VERSION 5.8 ;
BUSBITCHARS "[]" ;
DIVIDERCHAR "/" ;
UNITS
    DATABASE MICRONS 1000 ;
END UNITS

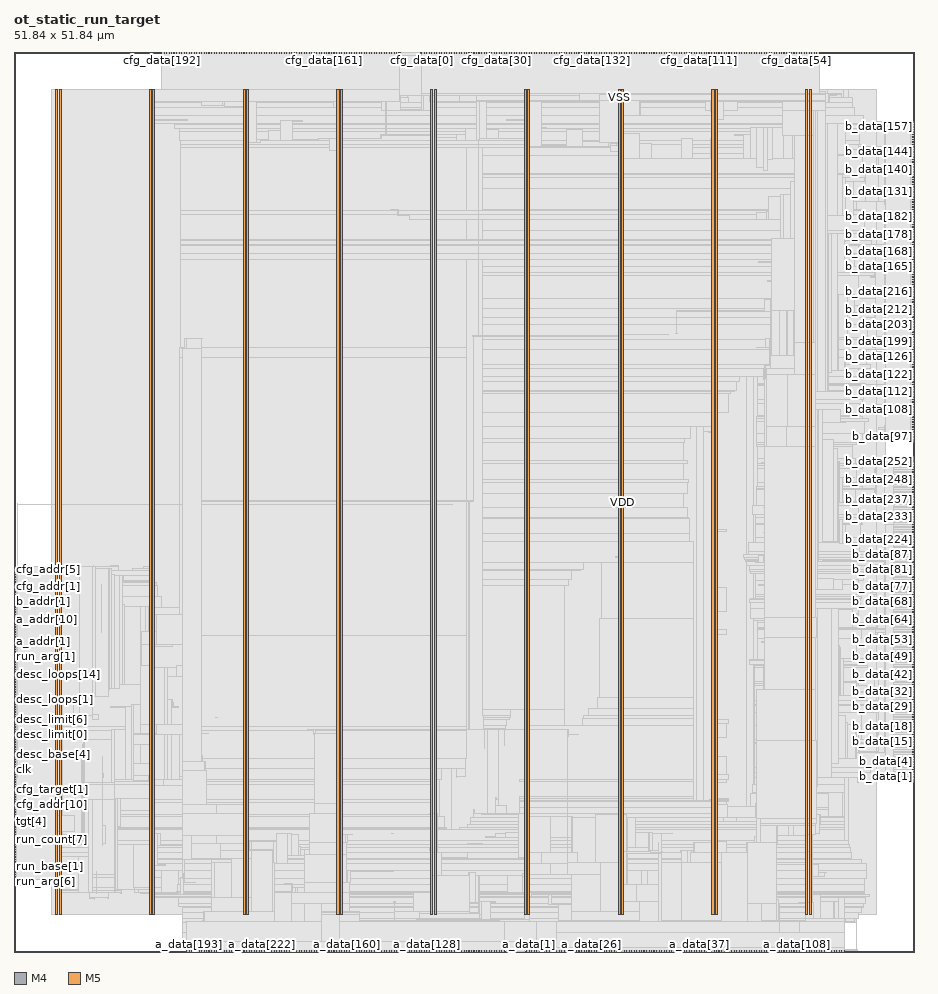
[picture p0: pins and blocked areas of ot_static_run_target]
MACRO ot_static_run_target
  FOREIGN ot_static_run_target 0 0 ;
  CLASS BLOCK ;
  SIZE 51.84 BY 51.84 ;
  PIN a_addr[0]
    DIRECTION OUTPUT ;
    USE SIGNAL ;
    PORT
      LAYER M4 ;
        RECT  0 17.712 0.084 17.736 ;
    END
  END a_addr[0]
  PIN a_addr[10]
    DIRECTION OUTPUT ;
    USE SIGNAL ;
    PORT
      LAYER M4 ;
        RECT  0 19.152 0.084 19.176 ;
    END
  END a_addr[10]
  PIN a_addr[1]
    DIRECTION OUTPUT ;
    USE SIGNAL ;
    PORT
      LAYER M4 ;
        RECT  0 17.856 0.084 17.88 ;
    END
  END a_addr[1]
  PIN a_addr[2]
    DIRECTION OUTPUT ;
    USE SIGNAL ;
    PORT
      LAYER M4 ;
        RECT  0 18 0.084 18.024 ;
    END
  END a_addr[2]
  PIN a_addr[3]
    DIRECTION OUTPUT ;
    USE SIGNAL ;
    PORT
      LAYER M4 ;
        RECT  0 18.144 0.084 18.168 ;
    END
  END a_addr[3]
  PIN a_addr[4]
    DIRECTION OUTPUT ;
    USE SIGNAL ;
    PORT
      LAYER M4 ;
        RECT  0 18.288 0.084 18.312 ;
    END
  END a_addr[4]
  PIN a_addr[5]
    DIRECTION OUTPUT ;
    USE SIGNAL ;
    PORT
      LAYER M4 ;
        RECT  0 18.432 0.084 18.456 ;
    END
  END a_addr[5]
  PIN a_addr[6]
    DIRECTION OUTPUT ;
    USE SIGNAL ;
    PORT
      LAYER M4 ;
        RECT  0 18.576 0.084 18.6 ;
    END
  END a_addr[6]
  PIN a_addr[7]
    DIRECTION OUTPUT ;
    USE SIGNAL ;
    PORT
      LAYER M4 ;
        RECT  0 18.72 0.084 18.744 ;
    END
  END a_addr[7]
  PIN a_addr[8]
    DIRECTION OUTPUT ;
    USE SIGNAL ;
    PORT
      LAYER M4 ;
        RECT  0 18.864 0.084 18.888 ;
    END
  END a_addr[8]
  PIN a_addr[9]
    DIRECTION OUTPUT ;
    USE SIGNAL ;
    PORT
      LAYER M4 ;
        RECT  0 19.008 0.084 19.032 ;
    END
  END a_addr[9]
  PIN a_data[0]
    DIRECTION OUTPUT ;
    USE SIGNAL ;
    PORT
      LAYER M5 ;
        RECT  29.52 0 29.544 0.084 ;
    END
  END a_data[0]
  PIN a_data[100]
    DIRECTION OUTPUT ;
    USE SIGNAL ;
    PORT
      LAYER M5 ;
        RECT  43.92 0 43.944 0.084 ;
    END
  END a_data[100]
  PIN a_data[101]
    DIRECTION OUTPUT ;
    USE SIGNAL ;
    PORT
      LAYER M5 ;
        RECT  44.064 0 44.088 0.084 ;
    END
  END a_data[101]
  PIN a_data[102]
    DIRECTION OUTPUT ;
    USE SIGNAL ;
    PORT
      LAYER M5 ;
        RECT  44.208 0 44.232 0.084 ;
    END
  END a_data[102]
  PIN a_data[103]
    DIRECTION OUTPUT ;
    USE SIGNAL ;
    PORT
      LAYER M5 ;
        RECT  44.352 0 44.376 0.084 ;
    END
  END a_data[103]
  PIN a_data[104]
    DIRECTION OUTPUT ;
    USE SIGNAL ;
    PORT
      LAYER M5 ;
        RECT  44.496 0 44.52 0.084 ;
    END
  END a_data[104]
  PIN a_data[105]
    DIRECTION OUTPUT ;
    USE SIGNAL ;
    PORT
      LAYER M5 ;
        RECT  44.64 0 44.664 0.084 ;
    END
  END a_data[105]
  PIN a_data[106]
    DIRECTION OUTPUT ;
    USE SIGNAL ;
    PORT
      LAYER M5 ;
        RECT  44.784 0 44.808 0.084 ;
    END
  END a_data[106]
  PIN a_data[107]
    DIRECTION OUTPUT ;
    USE SIGNAL ;
    PORT
      LAYER M5 ;
        RECT  44.928 0 44.952 0.084 ;
    END
  END a_data[107]
  PIN a_data[108]
    DIRECTION OUTPUT ;
    USE SIGNAL ;
    PORT
      LAYER M5 ;
        RECT  45.072 0 45.096 0.084 ;
    END
  END a_data[108]
  PIN a_data[109]
    DIRECTION OUTPUT ;
    USE SIGNAL ;
    PORT
      LAYER M5 ;
        RECT  45.216 0 45.24 0.084 ;
    END
  END a_data[109]
  PIN a_data[10]
    DIRECTION OUTPUT ;
    USE SIGNAL ;
    PORT
      LAYER M5 ;
        RECT  30.96 0 30.984 0.084 ;
    END
  END a_data[10]
  PIN a_data[110]
    DIRECTION OUTPUT ;
    USE SIGNAL ;
    PORT
      LAYER M5 ;
        RECT  45.36 0 45.384 0.084 ;
    END
  END a_data[110]
  PIN a_data[111]
    DIRECTION OUTPUT ;
    USE SIGNAL ;
    PORT
      LAYER M5 ;
        RECT  45.504 0 45.528 0.084 ;
    END
  END a_data[111]
  PIN a_data[112]
    DIRECTION OUTPUT ;
    USE SIGNAL ;
    PORT
      LAYER M5 ;
        RECT  45.648 0 45.672 0.084 ;
    END
  END a_data[112]
  PIN a_data[113]
    DIRECTION OUTPUT ;
    USE SIGNAL ;
    PORT
      LAYER M5 ;
        RECT  45.792 0 45.816 0.084 ;
    END
  END a_data[113]
  PIN a_data[114]
    DIRECTION OUTPUT ;
    USE SIGNAL ;
    PORT
      LAYER M5 ;
        RECT  45.936 0 45.96 0.084 ;
    END
  END a_data[114]
  PIN a_data[115]
    DIRECTION OUTPUT ;
    USE SIGNAL ;
    PORT
      LAYER M5 ;
        RECT  46.08 0 46.104 0.084 ;
    END
  END a_data[115]
  PIN a_data[116]
    DIRECTION OUTPUT ;
    USE SIGNAL ;
    PORT
      LAYER M5 ;
        RECT  46.224 0 46.248 0.084 ;
    END
  END a_data[116]
  PIN a_data[117]
    DIRECTION OUTPUT ;
    USE SIGNAL ;
    PORT
      LAYER M5 ;
        RECT  46.368 0 46.392 0.084 ;
    END
  END a_data[117]
  PIN a_data[118]
    DIRECTION OUTPUT ;
    USE SIGNAL ;
    PORT
      LAYER M5 ;
        RECT  46.512 0 46.536 0.084 ;
    END
  END a_data[118]
  PIN a_data[119]
    DIRECTION OUTPUT ;
    USE SIGNAL ;
    PORT
      LAYER M5 ;
        RECT  46.656 0 46.68 0.084 ;
    END
  END a_data[119]
  PIN a_data[11]
    DIRECTION OUTPUT ;
    USE SIGNAL ;
    PORT
      LAYER M5 ;
        RECT  31.104 0 31.128 0.084 ;
    END
  END a_data[11]
  PIN a_data[120]
    DIRECTION OUTPUT ;
    USE SIGNAL ;
    PORT
      LAYER M5 ;
        RECT  46.8 0 46.824 0.084 ;
    END
  END a_data[120]
  PIN a_data[121]
    DIRECTION OUTPUT ;
    USE SIGNAL ;
    PORT
      LAYER M5 ;
        RECT  46.944 0 46.968 0.084 ;
    END
  END a_data[121]
  PIN a_data[122]
    DIRECTION OUTPUT ;
    USE SIGNAL ;
    PORT
      LAYER M5 ;
        RECT  47.088 0 47.112 0.084 ;
    END
  END a_data[122]
  PIN a_data[123]
    DIRECTION OUTPUT ;
    USE SIGNAL ;
    PORT
      LAYER M5 ;
        RECT  47.232 0 47.256 0.084 ;
    END
  END a_data[123]
  PIN a_data[124]
    DIRECTION OUTPUT ;
    USE SIGNAL ;
    PORT
      LAYER M5 ;
        RECT  47.376 0 47.4 0.084 ;
    END
  END a_data[124]
  PIN a_data[125]
    DIRECTION OUTPUT ;
    USE SIGNAL ;
    PORT
      LAYER M5 ;
        RECT  47.52 0 47.544 0.084 ;
    END
  END a_data[125]
  PIN a_data[126]
    DIRECTION OUTPUT ;
    USE SIGNAL ;
    PORT
      LAYER M5 ;
        RECT  47.664 0 47.688 0.084 ;
    END
  END a_data[126]
  PIN a_data[127]
    DIRECTION OUTPUT ;
    USE SIGNAL ;
    PORT
      LAYER M5 ;
        RECT  47.808 0 47.832 0.084 ;
    END
  END a_data[127]
  PIN a_data[128]
    DIRECTION OUTPUT ;
    USE SIGNAL ;
    PORT
      LAYER M5 ;
        RECT  23.76 0 23.784 0.084 ;
    END
  END a_data[128]
  PIN a_data[129]
    DIRECTION OUTPUT ;
    USE SIGNAL ;
    PORT
      LAYER M5 ;
        RECT  23.904 0 23.928 0.084 ;
    END
  END a_data[129]
  PIN a_data[12]
    DIRECTION OUTPUT ;
    USE SIGNAL ;
    PORT
      LAYER M5 ;
        RECT  31.248 0 31.272 0.084 ;
    END
  END a_data[12]
  PIN a_data[130]
    DIRECTION OUTPUT ;
    USE SIGNAL ;
    PORT
      LAYER M5 ;
        RECT  24.048 0 24.072 0.084 ;
    END
  END a_data[130]
  PIN a_data[131]
    DIRECTION OUTPUT ;
    USE SIGNAL ;
    PORT
      LAYER M5 ;
        RECT  24.192 0 24.216 0.084 ;
    END
  END a_data[131]
  PIN a_data[132]
    DIRECTION OUTPUT ;
    USE SIGNAL ;
    PORT
      LAYER M5 ;
        RECT  24.336 0 24.36 0.084 ;
    END
  END a_data[132]
  PIN a_data[133]
    DIRECTION OUTPUT ;
    USE SIGNAL ;
    PORT
      LAYER M5 ;
        RECT  24.48 0 24.504 0.084 ;
    END
  END a_data[133]
  PIN a_data[134]
    DIRECTION OUTPUT ;
    USE SIGNAL ;
    PORT
      LAYER M5 ;
        RECT  24.624 0 24.648 0.084 ;
    END
  END a_data[134]
  PIN a_data[135]
    DIRECTION OUTPUT ;
    USE SIGNAL ;
    PORT
      LAYER M5 ;
        RECT  24.768 0 24.792 0.084 ;
    END
  END a_data[135]
  PIN a_data[136]
    DIRECTION OUTPUT ;
    USE SIGNAL ;
    PORT
      LAYER M5 ;
        RECT  24.912 0 24.936 0.084 ;
    END
  END a_data[136]
  PIN a_data[137]
    DIRECTION OUTPUT ;
    USE SIGNAL ;
    PORT
      LAYER M5 ;
        RECT  25.056 0 25.08 0.084 ;
    END
  END a_data[137]
  PIN a_data[138]
    DIRECTION OUTPUT ;
    USE SIGNAL ;
    PORT
      LAYER M5 ;
        RECT  25.2 0 25.224 0.084 ;
    END
  END a_data[138]
  PIN a_data[139]
    DIRECTION OUTPUT ;
    USE SIGNAL ;
    PORT
      LAYER M5 ;
        RECT  25.344 0 25.368 0.084 ;
    END
  END a_data[139]
  PIN a_data[13]
    DIRECTION OUTPUT ;
    USE SIGNAL ;
    PORT
      LAYER M5 ;
        RECT  31.392 0 31.416 0.084 ;
    END
  END a_data[13]
  PIN a_data[140]
    DIRECTION OUTPUT ;
    USE SIGNAL ;
    PORT
      LAYER M5 ;
        RECT  25.488 0 25.512 0.084 ;
    END
  END a_data[140]
  PIN a_data[141]
    DIRECTION OUTPUT ;
    USE SIGNAL ;
    PORT
      LAYER M5 ;
        RECT  25.632 0 25.656 0.084 ;
    END
  END a_data[141]
  PIN a_data[142]
    DIRECTION OUTPUT ;
    USE SIGNAL ;
    PORT
      LAYER M5 ;
        RECT  25.776 0 25.8 0.084 ;
    END
  END a_data[142]
  PIN a_data[143]
    DIRECTION OUTPUT ;
    USE SIGNAL ;
    PORT
      LAYER M5 ;
        RECT  25.92 0 25.944 0.084 ;
    END
  END a_data[143]
  PIN a_data[144]
    DIRECTION OUTPUT ;
    USE SIGNAL ;
    PORT
      LAYER M5 ;
        RECT  26.064 0 26.088 0.084 ;
    END
  END a_data[144]
  PIN a_data[145]
    DIRECTION OUTPUT ;
    USE SIGNAL ;
    PORT
      LAYER M5 ;
        RECT  26.208 0 26.232 0.084 ;
    END
  END a_data[145]
  PIN a_data[146]
    DIRECTION OUTPUT ;
    USE SIGNAL ;
    PORT
      LAYER M5 ;
        RECT  26.352 0 26.376 0.084 ;
    END
  END a_data[146]
  PIN a_data[147]
    DIRECTION OUTPUT ;
    USE SIGNAL ;
    PORT
      LAYER M5 ;
        RECT  26.496 0 26.52 0.084 ;
    END
  END a_data[147]
  PIN a_data[148]
    DIRECTION OUTPUT ;
    USE SIGNAL ;
    PORT
      LAYER M5 ;
        RECT  26.64 0 26.664 0.084 ;
    END
  END a_data[148]
  PIN a_data[149]
    DIRECTION OUTPUT ;
    USE SIGNAL ;
    PORT
      LAYER M5 ;
        RECT  26.784 0 26.808 0.084 ;
    END
  END a_data[149]
  PIN a_data[14]
    DIRECTION OUTPUT ;
    USE SIGNAL ;
    PORT
      LAYER M5 ;
        RECT  31.536 0 31.56 0.084 ;
    END
  END a_data[14]
  PIN a_data[150]
    DIRECTION OUTPUT ;
    USE SIGNAL ;
    PORT
      LAYER M5 ;
        RECT  26.928 0 26.952 0.084 ;
    END
  END a_data[150]
  PIN a_data[151]
    DIRECTION OUTPUT ;
    USE SIGNAL ;
    PORT
      LAYER M5 ;
        RECT  27.072 0 27.096 0.084 ;
    END
  END a_data[151]
  PIN a_data[152]
    DIRECTION OUTPUT ;
    USE SIGNAL ;
    PORT
      LAYER M5 ;
        RECT  27.216 0 27.24 0.084 ;
    END
  END a_data[152]
  PIN a_data[153]
    DIRECTION OUTPUT ;
    USE SIGNAL ;
    PORT
      LAYER M5 ;
        RECT  27.36 0 27.384 0.084 ;
    END
  END a_data[153]
  PIN a_data[154]
    DIRECTION OUTPUT ;
    USE SIGNAL ;
    PORT
      LAYER M5 ;
        RECT  27.504 0 27.528 0.084 ;
    END
  END a_data[154]
  PIN a_data[155]
    DIRECTION OUTPUT ;
    USE SIGNAL ;
    PORT
      LAYER M5 ;
        RECT  27.648 0 27.672 0.084 ;
    END
  END a_data[155]
  PIN a_data[156]
    DIRECTION OUTPUT ;
    USE SIGNAL ;
    PORT
      LAYER M5 ;
        RECT  27.792 0 27.816 0.084 ;
    END
  END a_data[156]
  PIN a_data[157]
    DIRECTION OUTPUT ;
    USE SIGNAL ;
    PORT
      LAYER M5 ;
        RECT  27.936 0 27.96 0.084 ;
    END
  END a_data[157]
  PIN a_data[158]
    DIRECTION OUTPUT ;
    USE SIGNAL ;
    PORT
      LAYER M5 ;
        RECT  28.08 0 28.104 0.084 ;
    END
  END a_data[158]
  PIN a_data[159]
    DIRECTION OUTPUT ;
    USE SIGNAL ;
    PORT
      LAYER M5 ;
        RECT  28.224 0 28.248 0.084 ;
    END
  END a_data[159]
  PIN a_data[15]
    DIRECTION OUTPUT ;
    USE SIGNAL ;
    PORT
      LAYER M5 ;
        RECT  31.68 0 31.704 0.084 ;
    END
  END a_data[15]
  PIN a_data[160]
    DIRECTION OUTPUT ;
    USE SIGNAL ;
    PORT
      LAYER M5 ;
        RECT  19.152 0 19.176 0.084 ;
    END
  END a_data[160]
  PIN a_data[161]
    DIRECTION OUTPUT ;
    USE SIGNAL ;
    PORT
      LAYER M5 ;
        RECT  19.296 0 19.32 0.084 ;
    END
  END a_data[161]
  PIN a_data[162]
    DIRECTION OUTPUT ;
    USE SIGNAL ;
    PORT
      LAYER M5 ;
        RECT  19.44 0 19.464 0.084 ;
    END
  END a_data[162]
  PIN a_data[163]
    DIRECTION OUTPUT ;
    USE SIGNAL ;
    PORT
      LAYER M5 ;
        RECT  19.584 0 19.608 0.084 ;
    END
  END a_data[163]
  PIN a_data[164]
    DIRECTION OUTPUT ;
    USE SIGNAL ;
    PORT
      LAYER M5 ;
        RECT  19.728 0 19.752 0.084 ;
    END
  END a_data[164]
  PIN a_data[165]
    DIRECTION OUTPUT ;
    USE SIGNAL ;
    PORT
      LAYER M5 ;
        RECT  19.872 0 19.896 0.084 ;
    END
  END a_data[165]
  PIN a_data[166]
    DIRECTION OUTPUT ;
    USE SIGNAL ;
    PORT
      LAYER M5 ;
        RECT  20.016 0 20.04 0.084 ;
    END
  END a_data[166]
  PIN a_data[167]
    DIRECTION OUTPUT ;
    USE SIGNAL ;
    PORT
      LAYER M5 ;
        RECT  20.16 0 20.184 0.084 ;
    END
  END a_data[167]
  PIN a_data[168]
    DIRECTION OUTPUT ;
    USE SIGNAL ;
    PORT
      LAYER M5 ;
        RECT  20.304 0 20.328 0.084 ;
    END
  END a_data[168]
  PIN a_data[169]
    DIRECTION OUTPUT ;
    USE SIGNAL ;
    PORT
      LAYER M5 ;
        RECT  20.448 0 20.472 0.084 ;
    END
  END a_data[169]
  PIN a_data[16]
    DIRECTION OUTPUT ;
    USE SIGNAL ;
    PORT
      LAYER M5 ;
        RECT  31.824 0 31.848 0.084 ;
    END
  END a_data[16]
  PIN a_data[170]
    DIRECTION OUTPUT ;
    USE SIGNAL ;
    PORT
      LAYER M5 ;
        RECT  20.592 0 20.616 0.084 ;
    END
  END a_data[170]
  PIN a_data[171]
    DIRECTION OUTPUT ;
    USE SIGNAL ;
    PORT
      LAYER M5 ;
        RECT  20.736 0 20.76 0.084 ;
    END
  END a_data[171]
  PIN a_data[172]
    DIRECTION OUTPUT ;
    USE SIGNAL ;
    PORT
      LAYER M5 ;
        RECT  20.88 0 20.904 0.084 ;
    END
  END a_data[172]
  PIN a_data[173]
    DIRECTION OUTPUT ;
    USE SIGNAL ;
    PORT
      LAYER M5 ;
        RECT  21.024 0 21.048 0.084 ;
    END
  END a_data[173]
  PIN a_data[174]
    DIRECTION OUTPUT ;
    USE SIGNAL ;
    PORT
      LAYER M5 ;
        RECT  21.168 0 21.192 0.084 ;
    END
  END a_data[174]
  PIN a_data[175]
    DIRECTION OUTPUT ;
    USE SIGNAL ;
    PORT
      LAYER M5 ;
        RECT  21.312 0 21.336 0.084 ;
    END
  END a_data[175]
  PIN a_data[176]
    DIRECTION OUTPUT ;
    USE SIGNAL ;
    PORT
      LAYER M5 ;
        RECT  21.456 0 21.48 0.084 ;
    END
  END a_data[176]
  PIN a_data[177]
    DIRECTION OUTPUT ;
    USE SIGNAL ;
    PORT
      LAYER M5 ;
        RECT  21.6 0 21.624 0.084 ;
    END
  END a_data[177]
  PIN a_data[178]
    DIRECTION OUTPUT ;
    USE SIGNAL ;
    PORT
      LAYER M5 ;
        RECT  21.744 0 21.768 0.084 ;
    END
  END a_data[178]
  PIN a_data[179]
    DIRECTION OUTPUT ;
    USE SIGNAL ;
    PORT
      LAYER M5 ;
        RECT  21.888 0 21.912 0.084 ;
    END
  END a_data[179]
  PIN a_data[17]
    DIRECTION OUTPUT ;
    USE SIGNAL ;
    PORT
      LAYER M5 ;
        RECT  31.968 0 31.992 0.084 ;
    END
  END a_data[17]
  PIN a_data[180]
    DIRECTION OUTPUT ;
    USE SIGNAL ;
    PORT
      LAYER M5 ;
        RECT  22.032 0 22.056 0.084 ;
    END
  END a_data[180]
  PIN a_data[181]
    DIRECTION OUTPUT ;
    USE SIGNAL ;
    PORT
      LAYER M5 ;
        RECT  22.176 0 22.2 0.084 ;
    END
  END a_data[181]
  PIN a_data[182]
    DIRECTION OUTPUT ;
    USE SIGNAL ;
    PORT
      LAYER M5 ;
        RECT  22.32 0 22.344 0.084 ;
    END
  END a_data[182]
  PIN a_data[183]
    DIRECTION OUTPUT ;
    USE SIGNAL ;
    PORT
      LAYER M5 ;
        RECT  22.464 0 22.488 0.084 ;
    END
  END a_data[183]
  PIN a_data[184]
    DIRECTION OUTPUT ;
    USE SIGNAL ;
    PORT
      LAYER M5 ;
        RECT  22.608 0 22.632 0.084 ;
    END
  END a_data[184]
  PIN a_data[185]
    DIRECTION OUTPUT ;
    USE SIGNAL ;
    PORT
      LAYER M5 ;
        RECT  22.752 0 22.776 0.084 ;
    END
  END a_data[185]
  PIN a_data[186]
    DIRECTION OUTPUT ;
    USE SIGNAL ;
    PORT
      LAYER M5 ;
        RECT  22.896 0 22.92 0.084 ;
    END
  END a_data[186]
  PIN a_data[187]
    DIRECTION OUTPUT ;
    USE SIGNAL ;
    PORT
      LAYER M5 ;
        RECT  23.04 0 23.064 0.084 ;
    END
  END a_data[187]
  PIN a_data[188]
    DIRECTION OUTPUT ;
    USE SIGNAL ;
    PORT
      LAYER M5 ;
        RECT  23.184 0 23.208 0.084 ;
    END
  END a_data[188]
  PIN a_data[189]
    DIRECTION OUTPUT ;
    USE SIGNAL ;
    PORT
      LAYER M5 ;
        RECT  23.328 0 23.352 0.084 ;
    END
  END a_data[189]
  PIN a_data[18]
    DIRECTION OUTPUT ;
    USE SIGNAL ;
    PORT
      LAYER M5 ;
        RECT  32.112 0 32.136 0.084 ;
    END
  END a_data[18]
  PIN a_data[190]
    DIRECTION OUTPUT ;
    USE SIGNAL ;
    PORT
      LAYER M5 ;
        RECT  23.472 0 23.496 0.084 ;
    END
  END a_data[190]
  PIN a_data[191]
    DIRECTION OUTPUT ;
    USE SIGNAL ;
    PORT
      LAYER M5 ;
        RECT  23.616 0 23.64 0.084 ;
    END
  END a_data[191]
  PIN a_data[192]
    DIRECTION OUTPUT ;
    USE SIGNAL ;
    PORT
      LAYER M5 ;
        RECT  9.936 0 9.96 0.084 ;
    END
  END a_data[192]
  PIN a_data[193]
    DIRECTION OUTPUT ;
    USE SIGNAL ;
    PORT
      LAYER M5 ;
        RECT  10.08 0 10.104 0.084 ;
    END
  END a_data[193]
  PIN a_data[194]
    DIRECTION OUTPUT ;
    USE SIGNAL ;
    PORT
      LAYER M5 ;
        RECT  10.224 0 10.248 0.084 ;
    END
  END a_data[194]
  PIN a_data[195]
    DIRECTION OUTPUT ;
    USE SIGNAL ;
    PORT
      LAYER M5 ;
        RECT  10.368 0 10.392 0.084 ;
    END
  END a_data[195]
  PIN a_data[196]
    DIRECTION OUTPUT ;
    USE SIGNAL ;
    PORT
      LAYER M5 ;
        RECT  10.512 0 10.536 0.084 ;
    END
  END a_data[196]
  PIN a_data[197]
    DIRECTION OUTPUT ;
    USE SIGNAL ;
    PORT
      LAYER M5 ;
        RECT  10.656 0 10.68 0.084 ;
    END
  END a_data[197]
  PIN a_data[198]
    DIRECTION OUTPUT ;
    USE SIGNAL ;
    PORT
      LAYER M5 ;
        RECT  10.8 0 10.824 0.084 ;
    END
  END a_data[198]
  PIN a_data[199]
    DIRECTION OUTPUT ;
    USE SIGNAL ;
    PORT
      LAYER M5 ;
        RECT  10.944 0 10.968 0.084 ;
    END
  END a_data[199]
  PIN a_data[19]
    DIRECTION OUTPUT ;
    USE SIGNAL ;
    PORT
      LAYER M5 ;
        RECT  32.256 0 32.28 0.084 ;
    END
  END a_data[19]
  PIN a_data[1]
    DIRECTION OUTPUT ;
    USE SIGNAL ;
    PORT
      LAYER M5 ;
        RECT  29.664 0 29.688 0.084 ;
    END
  END a_data[1]
  PIN a_data[200]
    DIRECTION OUTPUT ;
    USE SIGNAL ;
    PORT
      LAYER M5 ;
        RECT  11.088 0 11.112 0.084 ;
    END
  END a_data[200]
  PIN a_data[201]
    DIRECTION OUTPUT ;
    USE SIGNAL ;
    PORT
      LAYER M5 ;
        RECT  11.232 0 11.256 0.084 ;
    END
  END a_data[201]
  PIN a_data[202]
    DIRECTION OUTPUT ;
    USE SIGNAL ;
    PORT
      LAYER M5 ;
        RECT  11.376 0 11.4 0.084 ;
    END
  END a_data[202]
  PIN a_data[203]
    DIRECTION OUTPUT ;
    USE SIGNAL ;
    PORT
      LAYER M5 ;
        RECT  11.52 0 11.544 0.084 ;
    END
  END a_data[203]
  PIN a_data[204]
    DIRECTION OUTPUT ;
    USE SIGNAL ;
    PORT
      LAYER M5 ;
        RECT  11.664 0 11.688 0.084 ;
    END
  END a_data[204]
  PIN a_data[205]
    DIRECTION OUTPUT ;
    USE SIGNAL ;
    PORT
      LAYER M5 ;
        RECT  11.808 0 11.832 0.084 ;
    END
  END a_data[205]
  PIN a_data[206]
    DIRECTION OUTPUT ;
    USE SIGNAL ;
    PORT
      LAYER M5 ;
        RECT  11.952 0 11.976 0.084 ;
    END
  END a_data[206]
  PIN a_data[207]
    DIRECTION OUTPUT ;
    USE SIGNAL ;
    PORT
      LAYER M5 ;
        RECT  12.096 0 12.12 0.084 ;
    END
  END a_data[207]
  PIN a_data[208]
    DIRECTION OUTPUT ;
    USE SIGNAL ;
    PORT
      LAYER M5 ;
        RECT  12.24 0 12.264 0.084 ;
    END
  END a_data[208]
  PIN a_data[209]
    DIRECTION OUTPUT ;
    USE SIGNAL ;
    PORT
      LAYER M5 ;
        RECT  12.384 0 12.408 0.084 ;
    END
  END a_data[209]
  PIN a_data[20]
    DIRECTION OUTPUT ;
    USE SIGNAL ;
    PORT
      LAYER M5 ;
        RECT  32.4 0 32.424 0.084 ;
    END
  END a_data[20]
  PIN a_data[210]
    DIRECTION OUTPUT ;
    USE SIGNAL ;
    PORT
      LAYER M5 ;
        RECT  12.528 0 12.552 0.084 ;
    END
  END a_data[210]
  PIN a_data[211]
    DIRECTION OUTPUT ;
    USE SIGNAL ;
    PORT
      LAYER M5 ;
        RECT  12.672 0 12.696 0.084 ;
    END
  END a_data[211]
  PIN a_data[212]
    DIRECTION OUTPUT ;
    USE SIGNAL ;
    PORT
      LAYER M5 ;
        RECT  12.816 0 12.84 0.084 ;
    END
  END a_data[212]
  PIN a_data[213]
    DIRECTION OUTPUT ;
    USE SIGNAL ;
    PORT
      LAYER M5 ;
        RECT  12.96 0 12.984 0.084 ;
    END
  END a_data[213]
  PIN a_data[214]
    DIRECTION OUTPUT ;
    USE SIGNAL ;
    PORT
      LAYER M5 ;
        RECT  13.104 0 13.128 0.084 ;
    END
  END a_data[214]
  PIN a_data[215]
    DIRECTION OUTPUT ;
    USE SIGNAL ;
    PORT
      LAYER M5 ;
        RECT  13.248 0 13.272 0.084 ;
    END
  END a_data[215]
  PIN a_data[216]
    DIRECTION OUTPUT ;
    USE SIGNAL ;
    PORT
      LAYER M5 ;
        RECT  13.392 0 13.416 0.084 ;
    END
  END a_data[216]
  PIN a_data[217]
    DIRECTION OUTPUT ;
    USE SIGNAL ;
    PORT
      LAYER M5 ;
        RECT  13.536 0 13.56 0.084 ;
    END
  END a_data[217]
  PIN a_data[218]
    DIRECTION OUTPUT ;
    USE SIGNAL ;
    PORT
      LAYER M5 ;
        RECT  13.68 0 13.704 0.084 ;
    END
  END a_data[218]
  PIN a_data[219]
    DIRECTION OUTPUT ;
    USE SIGNAL ;
    PORT
      LAYER M5 ;
        RECT  13.824 0 13.848 0.084 ;
    END
  END a_data[219]
  PIN a_data[21]
    DIRECTION OUTPUT ;
    USE SIGNAL ;
    PORT
      LAYER M5 ;
        RECT  32.544 0 32.568 0.084 ;
    END
  END a_data[21]
  PIN a_data[220]
    DIRECTION OUTPUT ;
    USE SIGNAL ;
    PORT
      LAYER M5 ;
        RECT  13.968 0 13.992 0.084 ;
    END
  END a_data[220]
  PIN a_data[221]
    DIRECTION OUTPUT ;
    USE SIGNAL ;
    PORT
      LAYER M5 ;
        RECT  14.112 0 14.136 0.084 ;
    END
  END a_data[221]
  PIN a_data[222]
    DIRECTION OUTPUT ;
    USE SIGNAL ;
    PORT
      LAYER M5 ;
        RECT  14.256 0 14.28 0.084 ;
    END
  END a_data[222]
  PIN a_data[223]
    DIRECTION OUTPUT ;
    USE SIGNAL ;
    PORT
      LAYER M5 ;
        RECT  14.4 0 14.424 0.084 ;
    END
  END a_data[223]
  PIN a_data[224]
    DIRECTION OUTPUT ;
    USE SIGNAL ;
    PORT
      LAYER M5 ;
        RECT  14.544 0 14.568 0.084 ;
    END
  END a_data[224]
  PIN a_data[225]
    DIRECTION OUTPUT ;
    USE SIGNAL ;
    PORT
      LAYER M5 ;
        RECT  14.688 0 14.712 0.084 ;
    END
  END a_data[225]
  PIN a_data[226]
    DIRECTION OUTPUT ;
    USE SIGNAL ;
    PORT
      LAYER M5 ;
        RECT  14.832 0 14.856 0.084 ;
    END
  END a_data[226]
  PIN a_data[227]
    DIRECTION OUTPUT ;
    USE SIGNAL ;
    PORT
      LAYER M5 ;
        RECT  14.976 0 15 0.084 ;
    END
  END a_data[227]
  PIN a_data[228]
    DIRECTION OUTPUT ;
    USE SIGNAL ;
    PORT
      LAYER M5 ;
        RECT  15.12 0 15.144 0.084 ;
    END
  END a_data[228]
  PIN a_data[229]
    DIRECTION OUTPUT ;
    USE SIGNAL ;
    PORT
      LAYER M5 ;
        RECT  15.264 0 15.288 0.084 ;
    END
  END a_data[229]
  PIN a_data[22]
    DIRECTION OUTPUT ;
    USE SIGNAL ;
    PORT
      LAYER M5 ;
        RECT  32.688 0 32.712 0.084 ;
    END
  END a_data[22]
  PIN a_data[230]
    DIRECTION OUTPUT ;
    USE SIGNAL ;
    PORT
      LAYER M5 ;
        RECT  15.408 0 15.432 0.084 ;
    END
  END a_data[230]
  PIN a_data[231]
    DIRECTION OUTPUT ;
    USE SIGNAL ;
    PORT
      LAYER M5 ;
        RECT  15.552 0 15.576 0.084 ;
    END
  END a_data[231]
  PIN a_data[232]
    DIRECTION OUTPUT ;
    USE SIGNAL ;
    PORT
      LAYER M5 ;
        RECT  15.696 0 15.72 0.084 ;
    END
  END a_data[232]
  PIN a_data[233]
    DIRECTION OUTPUT ;
    USE SIGNAL ;
    PORT
      LAYER M5 ;
        RECT  15.84 0 15.864 0.084 ;
    END
  END a_data[233]
  PIN a_data[234]
    DIRECTION OUTPUT ;
    USE SIGNAL ;
    PORT
      LAYER M5 ;
        RECT  15.984 0 16.008 0.084 ;
    END
  END a_data[234]
  PIN a_data[235]
    DIRECTION OUTPUT ;
    USE SIGNAL ;
    PORT
      LAYER M5 ;
        RECT  16.128 0 16.152 0.084 ;
    END
  END a_data[235]
  PIN a_data[236]
    DIRECTION OUTPUT ;
    USE SIGNAL ;
    PORT
      LAYER M5 ;
        RECT  16.272 0 16.296 0.084 ;
    END
  END a_data[236]
  PIN a_data[237]
    DIRECTION OUTPUT ;
    USE SIGNAL ;
    PORT
      LAYER M5 ;
        RECT  16.416 0 16.44 0.084 ;
    END
  END a_data[237]
  PIN a_data[238]
    DIRECTION OUTPUT ;
    USE SIGNAL ;
    PORT
      LAYER M5 ;
        RECT  16.56 0 16.584 0.084 ;
    END
  END a_data[238]
  PIN a_data[239]
    DIRECTION OUTPUT ;
    USE SIGNAL ;
    PORT
      LAYER M5 ;
        RECT  16.704 0 16.728 0.084 ;
    END
  END a_data[239]
  PIN a_data[23]
    DIRECTION OUTPUT ;
    USE SIGNAL ;
    PORT
      LAYER M5 ;
        RECT  32.832 0 32.856 0.084 ;
    END
  END a_data[23]
  PIN a_data[240]
    DIRECTION OUTPUT ;
    USE SIGNAL ;
    PORT
      LAYER M5 ;
        RECT  16.848 0 16.872 0.084 ;
    END
  END a_data[240]
  PIN a_data[241]
    DIRECTION OUTPUT ;
    USE SIGNAL ;
    PORT
      LAYER M5 ;
        RECT  16.992 0 17.016 0.084 ;
    END
  END a_data[241]
  PIN a_data[242]
    DIRECTION OUTPUT ;
    USE SIGNAL ;
    PORT
      LAYER M5 ;
        RECT  17.136 0 17.16 0.084 ;
    END
  END a_data[242]
  PIN a_data[243]
    DIRECTION OUTPUT ;
    USE SIGNAL ;
    PORT
      LAYER M5 ;
        RECT  17.28 0 17.304 0.084 ;
    END
  END a_data[243]
  PIN a_data[244]
    DIRECTION OUTPUT ;
    USE SIGNAL ;
    PORT
      LAYER M5 ;
        RECT  17.424 0 17.448 0.084 ;
    END
  END a_data[244]
  PIN a_data[245]
    DIRECTION OUTPUT ;
    USE SIGNAL ;
    PORT
      LAYER M5 ;
        RECT  17.568 0 17.592 0.084 ;
    END
  END a_data[245]
  PIN a_data[246]
    DIRECTION OUTPUT ;
    USE SIGNAL ;
    PORT
      LAYER M5 ;
        RECT  17.712 0 17.736 0.084 ;
    END
  END a_data[246]
  PIN a_data[247]
    DIRECTION OUTPUT ;
    USE SIGNAL ;
    PORT
      LAYER M5 ;
        RECT  17.856 0 17.88 0.084 ;
    END
  END a_data[247]
  PIN a_data[248]
    DIRECTION OUTPUT ;
    USE SIGNAL ;
    PORT
      LAYER M5 ;
        RECT  18 0 18.024 0.084 ;
    END
  END a_data[248]
  PIN a_data[249]
    DIRECTION OUTPUT ;
    USE SIGNAL ;
    PORT
      LAYER M5 ;
        RECT  18.144 0 18.168 0.084 ;
    END
  END a_data[249]
  PIN a_data[24]
    DIRECTION OUTPUT ;
    USE SIGNAL ;
    PORT
      LAYER M5 ;
        RECT  32.976 0 33 0.084 ;
    END
  END a_data[24]
  PIN a_data[250]
    DIRECTION OUTPUT ;
    USE SIGNAL ;
    PORT
      LAYER M5 ;
        RECT  18.288 0 18.312 0.084 ;
    END
  END a_data[250]
  PIN a_data[251]
    DIRECTION OUTPUT ;
    USE SIGNAL ;
    PORT
      LAYER M5 ;
        RECT  18.432 0 18.456 0.084 ;
    END
  END a_data[251]
  PIN a_data[252]
    DIRECTION OUTPUT ;
    USE SIGNAL ;
    PORT
      LAYER M5 ;
        RECT  18.576 0 18.6 0.084 ;
    END
  END a_data[252]
  PIN a_data[253]
    DIRECTION OUTPUT ;
    USE SIGNAL ;
    PORT
      LAYER M5 ;
        RECT  18.72 0 18.744 0.084 ;
    END
  END a_data[253]
  PIN a_data[254]
    DIRECTION OUTPUT ;
    USE SIGNAL ;
    PORT
      LAYER M5 ;
        RECT  18.864 0 18.888 0.084 ;
    END
  END a_data[254]
  PIN a_data[255]
    DIRECTION OUTPUT ;
    USE SIGNAL ;
    PORT
      LAYER M5 ;
        RECT  19.008 0 19.032 0.084 ;
    END
  END a_data[255]
  PIN a_data[25]
    DIRECTION OUTPUT ;
    USE SIGNAL ;
    PORT
      LAYER M5 ;
        RECT  33.12 0 33.144 0.084 ;
    END
  END a_data[25]
  PIN a_data[26]
    DIRECTION OUTPUT ;
    USE SIGNAL ;
    PORT
      LAYER M5 ;
        RECT  33.264 0 33.288 0.084 ;
    END
  END a_data[26]
  PIN a_data[27]
    DIRECTION OUTPUT ;
    USE SIGNAL ;
    PORT
      LAYER M5 ;
        RECT  33.408 0 33.432 0.084 ;
    END
  END a_data[27]
  PIN a_data[28]
    DIRECTION OUTPUT ;
    USE SIGNAL ;
    PORT
      LAYER M5 ;
        RECT  33.552 0 33.576 0.084 ;
    END
  END a_data[28]
  PIN a_data[29]
    DIRECTION OUTPUT ;
    USE SIGNAL ;
    PORT
      LAYER M5 ;
        RECT  33.696 0 33.72 0.084 ;
    END
  END a_data[29]
  PIN a_data[2]
    DIRECTION OUTPUT ;
    USE SIGNAL ;
    PORT
      LAYER M5 ;
        RECT  29.808 0 29.832 0.084 ;
    END
  END a_data[2]
  PIN a_data[30]
    DIRECTION OUTPUT ;
    USE SIGNAL ;
    PORT
      LAYER M5 ;
        RECT  33.84 0 33.864 0.084 ;
    END
  END a_data[30]
  PIN a_data[31]
    DIRECTION OUTPUT ;
    USE SIGNAL ;
    PORT
      LAYER M5 ;
        RECT  33.984 0 34.008 0.084 ;
    END
  END a_data[31]
  PIN a_data[32]
    DIRECTION OUTPUT ;
    USE SIGNAL ;
    PORT
      LAYER M5 ;
        RECT  38.736 0 38.76 0.084 ;
    END
  END a_data[32]
  PIN a_data[33]
    DIRECTION OUTPUT ;
    USE SIGNAL ;
    PORT
      LAYER M5 ;
        RECT  38.88 0 38.904 0.084 ;
    END
  END a_data[33]
  PIN a_data[34]
    DIRECTION OUTPUT ;
    USE SIGNAL ;
    PORT
      LAYER M5 ;
        RECT  39.024 0 39.048 0.084 ;
    END
  END a_data[34]
  PIN a_data[35]
    DIRECTION OUTPUT ;
    USE SIGNAL ;
    PORT
      LAYER M5 ;
        RECT  39.168 0 39.192 0.084 ;
    END
  END a_data[35]
  PIN a_data[36]
    DIRECTION OUTPUT ;
    USE SIGNAL ;
    PORT
      LAYER M5 ;
        RECT  39.312 0 39.336 0.084 ;
    END
  END a_data[36]
  PIN a_data[37]
    DIRECTION OUTPUT ;
    USE SIGNAL ;
    PORT
      LAYER M5 ;
        RECT  39.456 0 39.48 0.084 ;
    END
  END a_data[37]
  PIN a_data[38]
    DIRECTION OUTPUT ;
    USE SIGNAL ;
    PORT
      LAYER M5 ;
        RECT  39.6 0 39.624 0.084 ;
    END
  END a_data[38]
  PIN a_data[39]
    DIRECTION OUTPUT ;
    USE SIGNAL ;
    PORT
      LAYER M5 ;
        RECT  39.744 0 39.768 0.084 ;
    END
  END a_data[39]
  PIN a_data[3]
    DIRECTION OUTPUT ;
    USE SIGNAL ;
    PORT
      LAYER M5 ;
        RECT  29.952 0 29.976 0.084 ;
    END
  END a_data[3]
  PIN a_data[40]
    DIRECTION OUTPUT ;
    USE SIGNAL ;
    PORT
      LAYER M5 ;
        RECT  39.888 0 39.912 0.084 ;
    END
  END a_data[40]
  PIN a_data[41]
    DIRECTION OUTPUT ;
    USE SIGNAL ;
    PORT
      LAYER M5 ;
        RECT  40.032 0 40.056 0.084 ;
    END
  END a_data[41]
  PIN a_data[42]
    DIRECTION OUTPUT ;
    USE SIGNAL ;
    PORT
      LAYER M5 ;
        RECT  40.176 0 40.2 0.084 ;
    END
  END a_data[42]
  PIN a_data[43]
    DIRECTION OUTPUT ;
    USE SIGNAL ;
    PORT
      LAYER M5 ;
        RECT  40.32 0 40.344 0.084 ;
    END
  END a_data[43]
  PIN a_data[44]
    DIRECTION OUTPUT ;
    USE SIGNAL ;
    PORT
      LAYER M5 ;
        RECT  40.464 0 40.488 0.084 ;
    END
  END a_data[44]
  PIN a_data[45]
    DIRECTION OUTPUT ;
    USE SIGNAL ;
    PORT
      LAYER M5 ;
        RECT  40.608 0 40.632 0.084 ;
    END
  END a_data[45]
  PIN a_data[46]
    DIRECTION OUTPUT ;
    USE SIGNAL ;
    PORT
      LAYER M5 ;
        RECT  40.752 0 40.776 0.084 ;
    END
  END a_data[46]
  PIN a_data[47]
    DIRECTION OUTPUT ;
    USE SIGNAL ;
    PORT
      LAYER M5 ;
        RECT  40.896 0 40.92 0.084 ;
    END
  END a_data[47]
  PIN a_data[48]
    DIRECTION OUTPUT ;
    USE SIGNAL ;
    PORT
      LAYER M5 ;
        RECT  41.04 0 41.064 0.084 ;
    END
  END a_data[48]
  PIN a_data[49]
    DIRECTION OUTPUT ;
    USE SIGNAL ;
    PORT
      LAYER M5 ;
        RECT  41.184 0 41.208 0.084 ;
    END
  END a_data[49]
  PIN a_data[4]
    DIRECTION OUTPUT ;
    USE SIGNAL ;
    PORT
      LAYER M5 ;
        RECT  30.096 0 30.12 0.084 ;
    END
  END a_data[4]
  PIN a_data[50]
    DIRECTION OUTPUT ;
    USE SIGNAL ;
    PORT
      LAYER M5 ;
        RECT  41.328 0 41.352 0.084 ;
    END
  END a_data[50]
  PIN a_data[51]
    DIRECTION OUTPUT ;
    USE SIGNAL ;
    PORT
      LAYER M5 ;
        RECT  41.472 0 41.496 0.084 ;
    END
  END a_data[51]
  PIN a_data[52]
    DIRECTION OUTPUT ;
    USE SIGNAL ;
    PORT
      LAYER M5 ;
        RECT  41.616 0 41.64 0.084 ;
    END
  END a_data[52]
  PIN a_data[53]
    DIRECTION OUTPUT ;
    USE SIGNAL ;
    PORT
      LAYER M5 ;
        RECT  41.76 0 41.784 0.084 ;
    END
  END a_data[53]
  PIN a_data[54]
    DIRECTION OUTPUT ;
    USE SIGNAL ;
    PORT
      LAYER M5 ;
        RECT  41.904 0 41.928 0.084 ;
    END
  END a_data[54]
  PIN a_data[55]
    DIRECTION OUTPUT ;
    USE SIGNAL ;
    PORT
      LAYER M5 ;
        RECT  42.048 0 42.072 0.084 ;
    END
  END a_data[55]
  PIN a_data[56]
    DIRECTION OUTPUT ;
    USE SIGNAL ;
    PORT
      LAYER M5 ;
        RECT  42.192 0 42.216 0.084 ;
    END
  END a_data[56]
  PIN a_data[57]
    DIRECTION OUTPUT ;
    USE SIGNAL ;
    PORT
      LAYER M5 ;
        RECT  42.336 0 42.36 0.084 ;
    END
  END a_data[57]
  PIN a_data[58]
    DIRECTION OUTPUT ;
    USE SIGNAL ;
    PORT
      LAYER M5 ;
        RECT  42.48 0 42.504 0.084 ;
    END
  END a_data[58]
  PIN a_data[59]
    DIRECTION OUTPUT ;
    USE SIGNAL ;
    PORT
      LAYER M5 ;
        RECT  42.624 0 42.648 0.084 ;
    END
  END a_data[59]
  PIN a_data[5]
    DIRECTION OUTPUT ;
    USE SIGNAL ;
    PORT
      LAYER M5 ;
        RECT  30.24 0 30.264 0.084 ;
    END
  END a_data[5]
  PIN a_data[60]
    DIRECTION OUTPUT ;
    USE SIGNAL ;
    PORT
      LAYER M5 ;
        RECT  42.768 0 42.792 0.084 ;
    END
  END a_data[60]
  PIN a_data[61]
    DIRECTION OUTPUT ;
    USE SIGNAL ;
    PORT
      LAYER M5 ;
        RECT  42.912 0 42.936 0.084 ;
    END
  END a_data[61]
  PIN a_data[62]
    DIRECTION OUTPUT ;
    USE SIGNAL ;
    PORT
      LAYER M5 ;
        RECT  43.056 0 43.08 0.084 ;
    END
  END a_data[62]
  PIN a_data[63]
    DIRECTION OUTPUT ;
    USE SIGNAL ;
    PORT
      LAYER M5 ;
        RECT  43.2 0 43.224 0.084 ;
    END
  END a_data[63]
  PIN a_data[64]
    DIRECTION OUTPUT ;
    USE SIGNAL ;
    PORT
      LAYER M5 ;
        RECT  34.128 0 34.152 0.084 ;
    END
  END a_data[64]
  PIN a_data[65]
    DIRECTION OUTPUT ;
    USE SIGNAL ;
    PORT
      LAYER M5 ;
        RECT  34.272 0 34.296 0.084 ;
    END
  END a_data[65]
  PIN a_data[66]
    DIRECTION OUTPUT ;
    USE SIGNAL ;
    PORT
      LAYER M5 ;
        RECT  34.416 0 34.44 0.084 ;
    END
  END a_data[66]
  PIN a_data[67]
    DIRECTION OUTPUT ;
    USE SIGNAL ;
    PORT
      LAYER M5 ;
        RECT  34.56 0 34.584 0.084 ;
    END
  END a_data[67]
  PIN a_data[68]
    DIRECTION OUTPUT ;
    USE SIGNAL ;
    PORT
      LAYER M5 ;
        RECT  34.704 0 34.728 0.084 ;
    END
  END a_data[68]
  PIN a_data[69]
    DIRECTION OUTPUT ;
    USE SIGNAL ;
    PORT
      LAYER M5 ;
        RECT  34.848 0 34.872 0.084 ;
    END
  END a_data[69]
  PIN a_data[6]
    DIRECTION OUTPUT ;
    USE SIGNAL ;
    PORT
      LAYER M5 ;
        RECT  30.384 0 30.408 0.084 ;
    END
  END a_data[6]
  PIN a_data[70]
    DIRECTION OUTPUT ;
    USE SIGNAL ;
    PORT
      LAYER M5 ;
        RECT  34.992 0 35.016 0.084 ;
    END
  END a_data[70]
  PIN a_data[71]
    DIRECTION OUTPUT ;
    USE SIGNAL ;
    PORT
      LAYER M5 ;
        RECT  35.136 0 35.16 0.084 ;
    END
  END a_data[71]
  PIN a_data[72]
    DIRECTION OUTPUT ;
    USE SIGNAL ;
    PORT
      LAYER M5 ;
        RECT  35.28 0 35.304 0.084 ;
    END
  END a_data[72]
  PIN a_data[73]
    DIRECTION OUTPUT ;
    USE SIGNAL ;
    PORT
      LAYER M5 ;
        RECT  35.424 0 35.448 0.084 ;
    END
  END a_data[73]
  PIN a_data[74]
    DIRECTION OUTPUT ;
    USE SIGNAL ;
    PORT
      LAYER M5 ;
        RECT  35.568 0 35.592 0.084 ;
    END
  END a_data[74]
  PIN a_data[75]
    DIRECTION OUTPUT ;
    USE SIGNAL ;
    PORT
      LAYER M5 ;
        RECT  35.712 0 35.736 0.084 ;
    END
  END a_data[75]
  PIN a_data[76]
    DIRECTION OUTPUT ;
    USE SIGNAL ;
    PORT
      LAYER M5 ;
        RECT  35.856 0 35.88 0.084 ;
    END
  END a_data[76]
  PIN a_data[77]
    DIRECTION OUTPUT ;
    USE SIGNAL ;
    PORT
      LAYER M5 ;
        RECT  36 0 36.024 0.084 ;
    END
  END a_data[77]
  PIN a_data[78]
    DIRECTION OUTPUT ;
    USE SIGNAL ;
    PORT
      LAYER M5 ;
        RECT  36.144 0 36.168 0.084 ;
    END
  END a_data[78]
  PIN a_data[79]
    DIRECTION OUTPUT ;
    USE SIGNAL ;
    PORT
      LAYER M5 ;
        RECT  36.288 0 36.312 0.084 ;
    END
  END a_data[79]
  PIN a_data[7]
    DIRECTION OUTPUT ;
    USE SIGNAL ;
    PORT
      LAYER M5 ;
        RECT  30.528 0 30.552 0.084 ;
    END
  END a_data[7]
  PIN a_data[80]
    DIRECTION OUTPUT ;
    USE SIGNAL ;
    PORT
      LAYER M5 ;
        RECT  36.432 0 36.456 0.084 ;
    END
  END a_data[80]
  PIN a_data[81]
    DIRECTION OUTPUT ;
    USE SIGNAL ;
    PORT
      LAYER M5 ;
        RECT  36.576 0 36.6 0.084 ;
    END
  END a_data[81]
  PIN a_data[82]
    DIRECTION OUTPUT ;
    USE SIGNAL ;
    PORT
      LAYER M5 ;
        RECT  36.72 0 36.744 0.084 ;
    END
  END a_data[82]
  PIN a_data[83]
    DIRECTION OUTPUT ;
    USE SIGNAL ;
    PORT
      LAYER M5 ;
        RECT  36.864 0 36.888 0.084 ;
    END
  END a_data[83]
  PIN a_data[84]
    DIRECTION OUTPUT ;
    USE SIGNAL ;
    PORT
      LAYER M5 ;
        RECT  37.008 0 37.032 0.084 ;
    END
  END a_data[84]
  PIN a_data[85]
    DIRECTION OUTPUT ;
    USE SIGNAL ;
    PORT
      LAYER M5 ;
        RECT  37.152 0 37.176 0.084 ;
    END
  END a_data[85]
  PIN a_data[86]
    DIRECTION OUTPUT ;
    USE SIGNAL ;
    PORT
      LAYER M5 ;
        RECT  37.296 0 37.32 0.084 ;
    END
  END a_data[86]
  PIN a_data[87]
    DIRECTION OUTPUT ;
    USE SIGNAL ;
    PORT
      LAYER M5 ;
        RECT  37.44 0 37.464 0.084 ;
    END
  END a_data[87]
  PIN a_data[88]
    DIRECTION OUTPUT ;
    USE SIGNAL ;
    PORT
      LAYER M5 ;
        RECT  37.584 0 37.608 0.084 ;
    END
  END a_data[88]
  PIN a_data[89]
    DIRECTION OUTPUT ;
    USE SIGNAL ;
    PORT
      LAYER M5 ;
        RECT  37.728 0 37.752 0.084 ;
    END
  END a_data[89]
  PIN a_data[8]
    DIRECTION OUTPUT ;
    USE SIGNAL ;
    PORT
      LAYER M5 ;
        RECT  30.672 0 30.696 0.084 ;
    END
  END a_data[8]
  PIN a_data[90]
    DIRECTION OUTPUT ;
    USE SIGNAL ;
    PORT
      LAYER M5 ;
        RECT  37.872 0 37.896 0.084 ;
    END
  END a_data[90]
  PIN a_data[91]
    DIRECTION OUTPUT ;
    USE SIGNAL ;
    PORT
      LAYER M5 ;
        RECT  38.016 0 38.04 0.084 ;
    END
  END a_data[91]
  PIN a_data[92]
    DIRECTION OUTPUT ;
    USE SIGNAL ;
    PORT
      LAYER M5 ;
        RECT  38.16 0 38.184 0.084 ;
    END
  END a_data[92]
  PIN a_data[93]
    DIRECTION OUTPUT ;
    USE SIGNAL ;
    PORT
      LAYER M5 ;
        RECT  38.304 0 38.328 0.084 ;
    END
  END a_data[93]
  PIN a_data[94]
    DIRECTION OUTPUT ;
    USE SIGNAL ;
    PORT
      LAYER M5 ;
        RECT  38.448 0 38.472 0.084 ;
    END
  END a_data[94]
  PIN a_data[95]
    DIRECTION OUTPUT ;
    USE SIGNAL ;
    PORT
      LAYER M5 ;
        RECT  38.592 0 38.616 0.084 ;
    END
  END a_data[95]
  PIN a_data[96]
    DIRECTION OUTPUT ;
    USE SIGNAL ;
    PORT
      LAYER M5 ;
        RECT  43.344 0 43.368 0.084 ;
    END
  END a_data[96]
  PIN a_data[97]
    DIRECTION OUTPUT ;
    USE SIGNAL ;
    PORT
      LAYER M5 ;
        RECT  43.488 0 43.512 0.084 ;
    END
  END a_data[97]
  PIN a_data[98]
    DIRECTION OUTPUT ;
    USE SIGNAL ;
    PORT
      LAYER M5 ;
        RECT  43.632 0 43.656 0.084 ;
    END
  END a_data[98]
  PIN a_data[99]
    DIRECTION OUTPUT ;
    USE SIGNAL ;
    PORT
      LAYER M5 ;
        RECT  43.776 0 43.8 0.084 ;
    END
  END a_data[99]
  PIN a_data[9]
    DIRECTION OUTPUT ;
    USE SIGNAL ;
    PORT
      LAYER M5 ;
        RECT  30.816 0 30.84 0.084 ;
    END
  END a_data[9]
  PIN a_we
    DIRECTION OUTPUT ;
    USE SIGNAL ;
    PORT
      LAYER M4 ;
        RECT  0 19.296 0.084 19.32 ;
    END
  END a_we
  PIN active
    DIRECTION OUTPUT ;
    USE SIGNAL ;
    PORT
      LAYER M4 ;
        RECT  0 19.44 0.084 19.464 ;
    END
  END active
  PIN b_addr[0]
    DIRECTION OUTPUT ;
    USE SIGNAL ;
    PORT
      LAYER M4 ;
        RECT  0 19.584 0.084 19.608 ;
    END
  END b_addr[0]
  PIN b_addr[1]
    DIRECTION OUTPUT ;
    USE SIGNAL ;
    PORT
      LAYER M4 ;
        RECT  0 19.728 0.084 19.752 ;
    END
  END b_addr[1]
  PIN b_addr[2]
    DIRECTION OUTPUT ;
    USE SIGNAL ;
    PORT
      LAYER M4 ;
        RECT  0 19.872 0.084 19.896 ;
    END
  END b_addr[2]
  PIN b_addr[3]
    DIRECTION OUTPUT ;
    USE SIGNAL ;
    PORT
      LAYER M4 ;
        RECT  0 20.016 0.084 20.04 ;
    END
  END b_addr[3]
  PIN b_addr[4]
    DIRECTION OUTPUT ;
    USE SIGNAL ;
    PORT
      LAYER M4 ;
        RECT  0 20.16 0.084 20.184 ;
    END
  END b_addr[4]
  PIN b_addr[5]
    DIRECTION OUTPUT ;
    USE SIGNAL ;
    PORT
      LAYER M4 ;
        RECT  0 20.304 0.084 20.328 ;
    END
  END b_addr[5]
  PIN b_addr[6]
    DIRECTION OUTPUT ;
    USE SIGNAL ;
    PORT
      LAYER M4 ;
        RECT  0 20.448 0.084 20.472 ;
    END
  END b_addr[6]
  PIN b_addr[7]
    DIRECTION OUTPUT ;
    USE SIGNAL ;
    PORT
      LAYER M4 ;
        RECT  0 20.592 0.084 20.616 ;
    END
  END b_addr[7]
  PIN b_data[0]
    DIRECTION OUTPUT ;
    USE SIGNAL ;
    PORT
      LAYER M4 ;
        RECT  51.756 9.936 51.84 9.96 ;
    END
  END b_data[0]
  PIN b_data[100]
    DIRECTION OUTPUT ;
    USE SIGNAL ;
    PORT
      LAYER M4 ;
        RECT  51.756 30.096 51.84 30.12 ;
    END
  END b_data[100]
  PIN b_data[101]
    DIRECTION OUTPUT ;
    USE SIGNAL ;
    PORT
      LAYER M4 ;
        RECT  51.756 30.24 51.84 30.264 ;
    END
  END b_data[101]
  PIN b_data[102]
    DIRECTION OUTPUT ;
    USE SIGNAL ;
    PORT
      LAYER M4 ;
        RECT  51.756 30.384 51.84 30.408 ;
    END
  END b_data[102]
  PIN b_data[103]
    DIRECTION OUTPUT ;
    USE SIGNAL ;
    PORT
      LAYER M4 ;
        RECT  51.756 30.528 51.84 30.552 ;
    END
  END b_data[103]
  PIN b_data[104]
    DIRECTION OUTPUT ;
    USE SIGNAL ;
    PORT
      LAYER M4 ;
        RECT  51.756 30.672 51.84 30.696 ;
    END
  END b_data[104]
  PIN b_data[105]
    DIRECTION OUTPUT ;
    USE SIGNAL ;
    PORT
      LAYER M4 ;
        RECT  51.756 30.816 51.84 30.84 ;
    END
  END b_data[105]
  PIN b_data[106]
    DIRECTION OUTPUT ;
    USE SIGNAL ;
    PORT
      LAYER M4 ;
        RECT  51.756 30.96 51.84 30.984 ;
    END
  END b_data[106]
  PIN b_data[107]
    DIRECTION OUTPUT ;
    USE SIGNAL ;
    PORT
      LAYER M4 ;
        RECT  51.756 31.104 51.84 31.128 ;
    END
  END b_data[107]
  PIN b_data[108]
    DIRECTION OUTPUT ;
    USE SIGNAL ;
    PORT
      LAYER M4 ;
        RECT  51.756 31.248 51.84 31.272 ;
    END
  END b_data[108]
  PIN b_data[109]
    DIRECTION OUTPUT ;
    USE SIGNAL ;
    PORT
      LAYER M4 ;
        RECT  51.756 31.392 51.84 31.416 ;
    END
  END b_data[109]
  PIN b_data[10]
    DIRECTION OUTPUT ;
    USE SIGNAL ;
    PORT
      LAYER M4 ;
        RECT  51.756 11.376 51.84 11.4 ;
    END
  END b_data[10]
  PIN b_data[110]
    DIRECTION OUTPUT ;
    USE SIGNAL ;
    PORT
      LAYER M4 ;
        RECT  51.756 31.536 51.84 31.56 ;
    END
  END b_data[110]
  PIN b_data[111]
    DIRECTION OUTPUT ;
    USE SIGNAL ;
    PORT
      LAYER M4 ;
        RECT  51.756 31.68 51.84 31.704 ;
    END
  END b_data[111]
  PIN b_data[112]
    DIRECTION OUTPUT ;
    USE SIGNAL ;
    PORT
      LAYER M4 ;
        RECT  51.756 31.824 51.84 31.848 ;
    END
  END b_data[112]
  PIN b_data[113]
    DIRECTION OUTPUT ;
    USE SIGNAL ;
    PORT
      LAYER M4 ;
        RECT  51.756 31.968 51.84 31.992 ;
    END
  END b_data[113]
  PIN b_data[114]
    DIRECTION OUTPUT ;
    USE SIGNAL ;
    PORT
      LAYER M4 ;
        RECT  51.756 32.112 51.84 32.136 ;
    END
  END b_data[114]
  PIN b_data[115]
    DIRECTION OUTPUT ;
    USE SIGNAL ;
    PORT
      LAYER M4 ;
        RECT  51.756 32.256 51.84 32.28 ;
    END
  END b_data[115]
  PIN b_data[116]
    DIRECTION OUTPUT ;
    USE SIGNAL ;
    PORT
      LAYER M4 ;
        RECT  51.756 32.4 51.84 32.424 ;
    END
  END b_data[116]
  PIN b_data[117]
    DIRECTION OUTPUT ;
    USE SIGNAL ;
    PORT
      LAYER M4 ;
        RECT  51.756 32.544 51.84 32.568 ;
    END
  END b_data[117]
  PIN b_data[118]
    DIRECTION OUTPUT ;
    USE SIGNAL ;
    PORT
      LAYER M4 ;
        RECT  51.756 32.688 51.84 32.712 ;
    END
  END b_data[118]
  PIN b_data[119]
    DIRECTION OUTPUT ;
    USE SIGNAL ;
    PORT
      LAYER M4 ;
        RECT  51.756 32.832 51.84 32.856 ;
    END
  END b_data[119]
  PIN b_data[11]
    DIRECTION OUTPUT ;
    USE SIGNAL ;
    PORT
      LAYER M4 ;
        RECT  51.756 11.52 51.84 11.544 ;
    END
  END b_data[11]
  PIN b_data[120]
    DIRECTION OUTPUT ;
    USE SIGNAL ;
    PORT
      LAYER M4 ;
        RECT  51.756 32.976 51.84 33 ;
    END
  END b_data[120]
  PIN b_data[121]
    DIRECTION OUTPUT ;
    USE SIGNAL ;
    PORT
      LAYER M4 ;
        RECT  51.756 33.12 51.84 33.144 ;
    END
  END b_data[121]
  PIN b_data[122]
    DIRECTION OUTPUT ;
    USE SIGNAL ;
    PORT
      LAYER M4 ;
        RECT  51.756 33.264 51.84 33.288 ;
    END
  END b_data[122]
  PIN b_data[123]
    DIRECTION OUTPUT ;
    USE SIGNAL ;
    PORT
      LAYER M4 ;
        RECT  51.756 33.408 51.84 33.432 ;
    END
  END b_data[123]
  PIN b_data[124]
    DIRECTION OUTPUT ;
    USE SIGNAL ;
    PORT
      LAYER M4 ;
        RECT  51.756 33.552 51.84 33.576 ;
    END
  END b_data[124]
  PIN b_data[125]
    DIRECTION OUTPUT ;
    USE SIGNAL ;
    PORT
      LAYER M4 ;
        RECT  51.756 33.696 51.84 33.72 ;
    END
  END b_data[125]
  PIN b_data[126]
    DIRECTION OUTPUT ;
    USE SIGNAL ;
    PORT
      LAYER M4 ;
        RECT  51.756 33.84 51.84 33.864 ;
    END
  END b_data[126]
  PIN b_data[127]
    DIRECTION OUTPUT ;
    USE SIGNAL ;
    PORT
      LAYER M4 ;
        RECT  51.756 33.984 51.84 34.008 ;
    END
  END b_data[127]
  PIN b_data[128]
    DIRECTION OUTPUT ;
    USE SIGNAL ;
    PORT
      LAYER M4 ;
        RECT  51.756 43.344 51.84 43.368 ;
    END
  END b_data[128]
  PIN b_data[129]
    DIRECTION OUTPUT ;
    USE SIGNAL ;
    PORT
      LAYER M4 ;
        RECT  51.756 43.488 51.84 43.512 ;
    END
  END b_data[129]
  PIN b_data[12]
    DIRECTION OUTPUT ;
    USE SIGNAL ;
    PORT
      LAYER M4 ;
        RECT  51.756 11.664 51.84 11.688 ;
    END
  END b_data[12]
  PIN b_data[130]
    DIRECTION OUTPUT ;
    USE SIGNAL ;
    PORT
      LAYER M4 ;
        RECT  51.756 43.632 51.84 43.656 ;
    END
  END b_data[130]
  PIN b_data[131]
    DIRECTION OUTPUT ;
    USE SIGNAL ;
    PORT
      LAYER M4 ;
        RECT  51.756 43.776 51.84 43.8 ;
    END
  END b_data[131]
  PIN b_data[132]
    DIRECTION OUTPUT ;
    USE SIGNAL ;
    PORT
      LAYER M4 ;
        RECT  51.756 43.92 51.84 43.944 ;
    END
  END b_data[132]
  PIN b_data[133]
    DIRECTION OUTPUT ;
    USE SIGNAL ;
    PORT
      LAYER M4 ;
        RECT  51.756 44.064 51.84 44.088 ;
    END
  END b_data[133]
  PIN b_data[134]
    DIRECTION OUTPUT ;
    USE SIGNAL ;
    PORT
      LAYER M4 ;
        RECT  51.756 44.208 51.84 44.232 ;
    END
  END b_data[134]
  PIN b_data[135]
    DIRECTION OUTPUT ;
    USE SIGNAL ;
    PORT
      LAYER M4 ;
        RECT  51.756 44.352 51.84 44.376 ;
    END
  END b_data[135]
  PIN b_data[136]
    DIRECTION OUTPUT ;
    USE SIGNAL ;
    PORT
      LAYER M4 ;
        RECT  51.756 44.496 51.84 44.52 ;
    END
  END b_data[136]
  PIN b_data[137]
    DIRECTION OUTPUT ;
    USE SIGNAL ;
    PORT
      LAYER M4 ;
        RECT  51.756 44.64 51.84 44.664 ;
    END
  END b_data[137]
  PIN b_data[138]
    DIRECTION OUTPUT ;
    USE SIGNAL ;
    PORT
      LAYER M4 ;
        RECT  51.756 44.784 51.84 44.808 ;
    END
  END b_data[138]
  PIN b_data[139]
    DIRECTION OUTPUT ;
    USE SIGNAL ;
    PORT
      LAYER M4 ;
        RECT  51.756 44.928 51.84 44.952 ;
    END
  END b_data[139]
  PIN b_data[13]
    DIRECTION OUTPUT ;
    USE SIGNAL ;
    PORT
      LAYER M4 ;
        RECT  51.756 11.808 51.84 11.832 ;
    END
  END b_data[13]
  PIN b_data[140]
    DIRECTION OUTPUT ;
    USE SIGNAL ;
    PORT
      LAYER M4 ;
        RECT  51.756 45.072 51.84 45.096 ;
    END
  END b_data[140]
  PIN b_data[141]
    DIRECTION OUTPUT ;
    USE SIGNAL ;
    PORT
      LAYER M4 ;
        RECT  51.756 45.216 51.84 45.24 ;
    END
  END b_data[141]
  PIN b_data[142]
    DIRECTION OUTPUT ;
    USE SIGNAL ;
    PORT
      LAYER M4 ;
        RECT  51.756 45.36 51.84 45.384 ;
    END
  END b_data[142]
  PIN b_data[143]
    DIRECTION OUTPUT ;
    USE SIGNAL ;
    PORT
      LAYER M4 ;
        RECT  51.756 45.504 51.84 45.528 ;
    END
  END b_data[143]
  PIN b_data[144]
    DIRECTION OUTPUT ;
    USE SIGNAL ;
    PORT
      LAYER M4 ;
        RECT  51.756 45.648 51.84 45.672 ;
    END
  END b_data[144]
  PIN b_data[145]
    DIRECTION OUTPUT ;
    USE SIGNAL ;
    PORT
      LAYER M4 ;
        RECT  51.756 45.792 51.84 45.816 ;
    END
  END b_data[145]
  PIN b_data[146]
    DIRECTION OUTPUT ;
    USE SIGNAL ;
    PORT
      LAYER M4 ;
        RECT  51.756 45.936 51.84 45.96 ;
    END
  END b_data[146]
  PIN b_data[147]
    DIRECTION OUTPUT ;
    USE SIGNAL ;
    PORT
      LAYER M4 ;
        RECT  51.756 46.08 51.84 46.104 ;
    END
  END b_data[147]
  PIN b_data[148]
    DIRECTION OUTPUT ;
    USE SIGNAL ;
    PORT
      LAYER M4 ;
        RECT  51.756 46.224 51.84 46.248 ;
    END
  END b_data[148]
  PIN b_data[149]
    DIRECTION OUTPUT ;
    USE SIGNAL ;
    PORT
      LAYER M4 ;
        RECT  51.756 46.368 51.84 46.392 ;
    END
  END b_data[149]
  PIN b_data[14]
    DIRECTION OUTPUT ;
    USE SIGNAL ;
    PORT
      LAYER M4 ;
        RECT  51.756 11.952 51.84 11.976 ;
    END
  END b_data[14]
  PIN b_data[150]
    DIRECTION OUTPUT ;
    USE SIGNAL ;
    PORT
      LAYER M4 ;
        RECT  51.756 46.512 51.84 46.536 ;
    END
  END b_data[150]
  PIN b_data[151]
    DIRECTION OUTPUT ;
    USE SIGNAL ;
    PORT
      LAYER M4 ;
        RECT  51.756 46.656 51.84 46.68 ;
    END
  END b_data[151]
  PIN b_data[152]
    DIRECTION OUTPUT ;
    USE SIGNAL ;
    PORT
      LAYER M4 ;
        RECT  51.756 46.8 51.84 46.824 ;
    END
  END b_data[152]
  PIN b_data[153]
    DIRECTION OUTPUT ;
    USE SIGNAL ;
    PORT
      LAYER M4 ;
        RECT  51.756 46.944 51.84 46.968 ;
    END
  END b_data[153]
  PIN b_data[154]
    DIRECTION OUTPUT ;
    USE SIGNAL ;
    PORT
      LAYER M4 ;
        RECT  51.756 47.088 51.84 47.112 ;
    END
  END b_data[154]
  PIN b_data[155]
    DIRECTION OUTPUT ;
    USE SIGNAL ;
    PORT
      LAYER M4 ;
        RECT  51.756 47.232 51.84 47.256 ;
    END
  END b_data[155]
  PIN b_data[156]
    DIRECTION OUTPUT ;
    USE SIGNAL ;
    PORT
      LAYER M4 ;
        RECT  51.756 47.376 51.84 47.4 ;
    END
  END b_data[156]
  PIN b_data[157]
    DIRECTION OUTPUT ;
    USE SIGNAL ;
    PORT
      LAYER M4 ;
        RECT  51.756 47.52 51.84 47.544 ;
    END
  END b_data[157]
  PIN b_data[158]
    DIRECTION OUTPUT ;
    USE SIGNAL ;
    PORT
      LAYER M4 ;
        RECT  51.756 47.664 51.84 47.688 ;
    END
  END b_data[158]
  PIN b_data[159]
    DIRECTION OUTPUT ;
    USE SIGNAL ;
    PORT
      LAYER M4 ;
        RECT  51.756 47.808 51.84 47.832 ;
    END
  END b_data[159]
  PIN b_data[15]
    DIRECTION OUTPUT ;
    USE SIGNAL ;
    PORT
      LAYER M4 ;
        RECT  51.756 12.096 51.84 12.12 ;
    END
  END b_data[15]
  PIN b_data[160]
    DIRECTION OUTPUT ;
    USE SIGNAL ;
    PORT
      LAYER M4 ;
        RECT  51.756 38.736 51.84 38.76 ;
    END
  END b_data[160]
  PIN b_data[161]
    DIRECTION OUTPUT ;
    USE SIGNAL ;
    PORT
      LAYER M4 ;
        RECT  51.756 38.88 51.84 38.904 ;
    END
  END b_data[161]
  PIN b_data[162]
    DIRECTION OUTPUT ;
    USE SIGNAL ;
    PORT
      LAYER M4 ;
        RECT  51.756 39.024 51.84 39.048 ;
    END
  END b_data[162]
  PIN b_data[163]
    DIRECTION OUTPUT ;
    USE SIGNAL ;
    PORT
      LAYER M4 ;
        RECT  51.756 39.168 51.84 39.192 ;
    END
  END b_data[163]
  PIN b_data[164]
    DIRECTION OUTPUT ;
    USE SIGNAL ;
    PORT
      LAYER M4 ;
        RECT  51.756 39.312 51.84 39.336 ;
    END
  END b_data[164]
  PIN b_data[165]
    DIRECTION OUTPUT ;
    USE SIGNAL ;
    PORT
      LAYER M4 ;
        RECT  51.756 39.456 51.84 39.48 ;
    END
  END b_data[165]
  PIN b_data[166]
    DIRECTION OUTPUT ;
    USE SIGNAL ;
    PORT
      LAYER M4 ;
        RECT  51.756 39.6 51.84 39.624 ;
    END
  END b_data[166]
  PIN b_data[167]
    DIRECTION OUTPUT ;
    USE SIGNAL ;
    PORT
      LAYER M4 ;
        RECT  51.756 39.744 51.84 39.768 ;
    END
  END b_data[167]
  PIN b_data[168]
    DIRECTION OUTPUT ;
    USE SIGNAL ;
    PORT
      LAYER M4 ;
        RECT  51.756 39.888 51.84 39.912 ;
    END
  END b_data[168]
  PIN b_data[169]
    DIRECTION OUTPUT ;
    USE SIGNAL ;
    PORT
      LAYER M4 ;
        RECT  51.756 40.032 51.84 40.056 ;
    END
  END b_data[169]
  PIN b_data[16]
    DIRECTION OUTPUT ;
    USE SIGNAL ;
    PORT
      LAYER M4 ;
        RECT  51.756 12.24 51.84 12.264 ;
    END
  END b_data[16]
  PIN b_data[170]
    DIRECTION OUTPUT ;
    USE SIGNAL ;
    PORT
      LAYER M4 ;
        RECT  51.756 40.176 51.84 40.2 ;
    END
  END b_data[170]
  PIN b_data[171]
    DIRECTION OUTPUT ;
    USE SIGNAL ;
    PORT
      LAYER M4 ;
        RECT  51.756 40.32 51.84 40.344 ;
    END
  END b_data[171]
  PIN b_data[172]
    DIRECTION OUTPUT ;
    USE SIGNAL ;
    PORT
      LAYER M4 ;
        RECT  51.756 40.464 51.84 40.488 ;
    END
  END b_data[172]
  PIN b_data[173]
    DIRECTION OUTPUT ;
    USE SIGNAL ;
    PORT
      LAYER M4 ;
        RECT  51.756 40.608 51.84 40.632 ;
    END
  END b_data[173]
  PIN b_data[174]
    DIRECTION OUTPUT ;
    USE SIGNAL ;
    PORT
      LAYER M4 ;
        RECT  51.756 40.752 51.84 40.776 ;
    END
  END b_data[174]
  PIN b_data[175]
    DIRECTION OUTPUT ;
    USE SIGNAL ;
    PORT
      LAYER M4 ;
        RECT  51.756 40.896 51.84 40.92 ;
    END
  END b_data[175]
  PIN b_data[176]
    DIRECTION OUTPUT ;
    USE SIGNAL ;
    PORT
      LAYER M4 ;
        RECT  51.756 41.04 51.84 41.064 ;
    END
  END b_data[176]
  PIN b_data[177]
    DIRECTION OUTPUT ;
    USE SIGNAL ;
    PORT
      LAYER M4 ;
        RECT  51.756 41.184 51.84 41.208 ;
    END
  END b_data[177]
  PIN b_data[178]
    DIRECTION OUTPUT ;
    USE SIGNAL ;
    PORT
      LAYER M4 ;
        RECT  51.756 41.328 51.84 41.352 ;
    END
  END b_data[178]
  PIN b_data[179]
    DIRECTION OUTPUT ;
    USE SIGNAL ;
    PORT
      LAYER M4 ;
        RECT  51.756 41.472 51.84 41.496 ;
    END
  END b_data[179]
  PIN b_data[17]
    DIRECTION OUTPUT ;
    USE SIGNAL ;
    PORT
      LAYER M4 ;
        RECT  51.756 12.384 51.84 12.408 ;
    END
  END b_data[17]
  PIN b_data[180]
    DIRECTION OUTPUT ;
    USE SIGNAL ;
    PORT
      LAYER M4 ;
        RECT  51.756 41.616 51.84 41.64 ;
    END
  END b_data[180]
  PIN b_data[181]
    DIRECTION OUTPUT ;
    USE SIGNAL ;
    PORT
      LAYER M4 ;
        RECT  51.756 41.76 51.84 41.784 ;
    END
  END b_data[181]
  PIN b_data[182]
    DIRECTION OUTPUT ;
    USE SIGNAL ;
    PORT
      LAYER M4 ;
        RECT  51.756 41.904 51.84 41.928 ;
    END
  END b_data[182]
  PIN b_data[183]
    DIRECTION OUTPUT ;
    USE SIGNAL ;
    PORT
      LAYER M4 ;
        RECT  51.756 42.048 51.84 42.072 ;
    END
  END b_data[183]
  PIN b_data[184]
    DIRECTION OUTPUT ;
    USE SIGNAL ;
    PORT
      LAYER M4 ;
        RECT  51.756 42.192 51.84 42.216 ;
    END
  END b_data[184]
  PIN b_data[185]
    DIRECTION OUTPUT ;
    USE SIGNAL ;
    PORT
      LAYER M4 ;
        RECT  51.756 42.336 51.84 42.36 ;
    END
  END b_data[185]
  PIN b_data[186]
    DIRECTION OUTPUT ;
    USE SIGNAL ;
    PORT
      LAYER M4 ;
        RECT  51.756 42.48 51.84 42.504 ;
    END
  END b_data[186]
  PIN b_data[187]
    DIRECTION OUTPUT ;
    USE SIGNAL ;
    PORT
      LAYER M4 ;
        RECT  51.756 42.624 51.84 42.648 ;
    END
  END b_data[187]
  PIN b_data[188]
    DIRECTION OUTPUT ;
    USE SIGNAL ;
    PORT
      LAYER M4 ;
        RECT  51.756 42.768 51.84 42.792 ;
    END
  END b_data[188]
  PIN b_data[189]
    DIRECTION OUTPUT ;
    USE SIGNAL ;
    PORT
      LAYER M4 ;
        RECT  51.756 42.912 51.84 42.936 ;
    END
  END b_data[189]
  PIN b_data[18]
    DIRECTION OUTPUT ;
    USE SIGNAL ;
    PORT
      LAYER M4 ;
        RECT  51.756 12.528 51.84 12.552 ;
    END
  END b_data[18]
  PIN b_data[190]
    DIRECTION OUTPUT ;
    USE SIGNAL ;
    PORT
      LAYER M4 ;
        RECT  51.756 43.056 51.84 43.08 ;
    END
  END b_data[190]
  PIN b_data[191]
    DIRECTION OUTPUT ;
    USE SIGNAL ;
    PORT
      LAYER M4 ;
        RECT  51.756 43.2 51.84 43.224 ;
    END
  END b_data[191]
  PIN b_data[192]
    DIRECTION OUTPUT ;
    USE SIGNAL ;
    PORT
      LAYER M4 ;
        RECT  51.756 34.128 51.84 34.152 ;
    END
  END b_data[192]
  PIN b_data[193]
    DIRECTION OUTPUT ;
    USE SIGNAL ;
    PORT
      LAYER M4 ;
        RECT  51.756 34.272 51.84 34.296 ;
    END
  END b_data[193]
  PIN b_data[194]
    DIRECTION OUTPUT ;
    USE SIGNAL ;
    PORT
      LAYER M4 ;
        RECT  51.756 34.416 51.84 34.44 ;
    END
  END b_data[194]
  PIN b_data[195]
    DIRECTION OUTPUT ;
    USE SIGNAL ;
    PORT
      LAYER M4 ;
        RECT  51.756 34.56 51.84 34.584 ;
    END
  END b_data[195]
  PIN b_data[196]
    DIRECTION OUTPUT ;
    USE SIGNAL ;
    PORT
      LAYER M4 ;
        RECT  51.756 34.704 51.84 34.728 ;
    END
  END b_data[196]
  PIN b_data[197]
    DIRECTION OUTPUT ;
    USE SIGNAL ;
    PORT
      LAYER M4 ;
        RECT  51.756 34.848 51.84 34.872 ;
    END
  END b_data[197]
  PIN b_data[198]
    DIRECTION OUTPUT ;
    USE SIGNAL ;
    PORT
      LAYER M4 ;
        RECT  51.756 34.992 51.84 35.016 ;
    END
  END b_data[198]
  PIN b_data[199]
    DIRECTION OUTPUT ;
    USE SIGNAL ;
    PORT
      LAYER M4 ;
        RECT  51.756 35.136 51.84 35.16 ;
    END
  END b_data[199]
  PIN b_data[19]
    DIRECTION OUTPUT ;
    USE SIGNAL ;
    PORT
      LAYER M4 ;
        RECT  51.756 12.672 51.84 12.696 ;
    END
  END b_data[19]
  PIN b_data[1]
    DIRECTION OUTPUT ;
    USE SIGNAL ;
    PORT
      LAYER M4 ;
        RECT  51.756 10.08 51.84 10.104 ;
    END
  END b_data[1]
  PIN b_data[200]
    DIRECTION OUTPUT ;
    USE SIGNAL ;
    PORT
      LAYER M4 ;
        RECT  51.756 35.28 51.84 35.304 ;
    END
  END b_data[200]
  PIN b_data[201]
    DIRECTION OUTPUT ;
    USE SIGNAL ;
    PORT
      LAYER M4 ;
        RECT  51.756 35.424 51.84 35.448 ;
    END
  END b_data[201]
  PIN b_data[202]
    DIRECTION OUTPUT ;
    USE SIGNAL ;
    PORT
      LAYER M4 ;
        RECT  51.756 35.568 51.84 35.592 ;
    END
  END b_data[202]
  PIN b_data[203]
    DIRECTION OUTPUT ;
    USE SIGNAL ;
    PORT
      LAYER M4 ;
        RECT  51.756 35.712 51.84 35.736 ;
    END
  END b_data[203]
  PIN b_data[204]
    DIRECTION OUTPUT ;
    USE SIGNAL ;
    PORT
      LAYER M4 ;
        RECT  51.756 35.856 51.84 35.88 ;
    END
  END b_data[204]
  PIN b_data[205]
    DIRECTION OUTPUT ;
    USE SIGNAL ;
    PORT
      LAYER M4 ;
        RECT  51.756 36 51.84 36.024 ;
    END
  END b_data[205]
  PIN b_data[206]
    DIRECTION OUTPUT ;
    USE SIGNAL ;
    PORT
      LAYER M4 ;
        RECT  51.756 36.144 51.84 36.168 ;
    END
  END b_data[206]
  PIN b_data[207]
    DIRECTION OUTPUT ;
    USE SIGNAL ;
    PORT
      LAYER M4 ;
        RECT  51.756 36.288 51.84 36.312 ;
    END
  END b_data[207]
  PIN b_data[208]
    DIRECTION OUTPUT ;
    USE SIGNAL ;
    PORT
      LAYER M4 ;
        RECT  51.756 36.432 51.84 36.456 ;
    END
  END b_data[208]
  PIN b_data[209]
    DIRECTION OUTPUT ;
    USE SIGNAL ;
    PORT
      LAYER M4 ;
        RECT  51.756 36.576 51.84 36.6 ;
    END
  END b_data[209]
  PIN b_data[20]
    DIRECTION OUTPUT ;
    USE SIGNAL ;
    PORT
      LAYER M4 ;
        RECT  51.756 12.816 51.84 12.84 ;
    END
  END b_data[20]
  PIN b_data[210]
    DIRECTION OUTPUT ;
    USE SIGNAL ;
    PORT
      LAYER M4 ;
        RECT  51.756 36.72 51.84 36.744 ;
    END
  END b_data[210]
  PIN b_data[211]
    DIRECTION OUTPUT ;
    USE SIGNAL ;
    PORT
      LAYER M4 ;
        RECT  51.756 36.864 51.84 36.888 ;
    END
  END b_data[211]
  PIN b_data[212]
    DIRECTION OUTPUT ;
    USE SIGNAL ;
    PORT
      LAYER M4 ;
        RECT  51.756 37.008 51.84 37.032 ;
    END
  END b_data[212]
  PIN b_data[213]
    DIRECTION OUTPUT ;
    USE SIGNAL ;
    PORT
      LAYER M4 ;
        RECT  51.756 37.152 51.84 37.176 ;
    END
  END b_data[213]
  PIN b_data[214]
    DIRECTION OUTPUT ;
    USE SIGNAL ;
    PORT
      LAYER M4 ;
        RECT  51.756 37.296 51.84 37.32 ;
    END
  END b_data[214]
  PIN b_data[215]
    DIRECTION OUTPUT ;
    USE SIGNAL ;
    PORT
      LAYER M4 ;
        RECT  51.756 37.44 51.84 37.464 ;
    END
  END b_data[215]
  PIN b_data[216]
    DIRECTION OUTPUT ;
    USE SIGNAL ;
    PORT
      LAYER M4 ;
        RECT  51.756 37.584 51.84 37.608 ;
    END
  END b_data[216]
  PIN b_data[217]
    DIRECTION OUTPUT ;
    USE SIGNAL ;
    PORT
      LAYER M4 ;
        RECT  51.756 37.728 51.84 37.752 ;
    END
  END b_data[217]
  PIN b_data[218]
    DIRECTION OUTPUT ;
    USE SIGNAL ;
    PORT
      LAYER M4 ;
        RECT  51.756 37.872 51.84 37.896 ;
    END
  END b_data[218]
  PIN b_data[219]
    DIRECTION OUTPUT ;
    USE SIGNAL ;
    PORT
      LAYER M4 ;
        RECT  51.756 38.016 51.84 38.04 ;
    END
  END b_data[219]
  PIN b_data[21]
    DIRECTION OUTPUT ;
    USE SIGNAL ;
    PORT
      LAYER M4 ;
        RECT  51.756 12.96 51.84 12.984 ;
    END
  END b_data[21]
  PIN b_data[220]
    DIRECTION OUTPUT ;
    USE SIGNAL ;
    PORT
      LAYER M4 ;
        RECT  51.756 38.16 51.84 38.184 ;
    END
  END b_data[220]
  PIN b_data[221]
    DIRECTION OUTPUT ;
    USE SIGNAL ;
    PORT
      LAYER M4 ;
        RECT  51.756 38.304 51.84 38.328 ;
    END
  END b_data[221]
  PIN b_data[222]
    DIRECTION OUTPUT ;
    USE SIGNAL ;
    PORT
      LAYER M4 ;
        RECT  51.756 38.448 51.84 38.472 ;
    END
  END b_data[222]
  PIN b_data[223]
    DIRECTION OUTPUT ;
    USE SIGNAL ;
    PORT
      LAYER M4 ;
        RECT  51.756 38.592 51.84 38.616 ;
    END
  END b_data[223]
  PIN b_data[224]
    DIRECTION OUTPUT ;
    USE SIGNAL ;
    PORT
      LAYER M4 ;
        RECT  51.756 23.76 51.84 23.784 ;
    END
  END b_data[224]
  PIN b_data[225]
    DIRECTION OUTPUT ;
    USE SIGNAL ;
    PORT
      LAYER M4 ;
        RECT  51.756 23.904 51.84 23.928 ;
    END
  END b_data[225]
  PIN b_data[226]
    DIRECTION OUTPUT ;
    USE SIGNAL ;
    PORT
      LAYER M4 ;
        RECT  51.756 24.048 51.84 24.072 ;
    END
  END b_data[226]
  PIN b_data[227]
    DIRECTION OUTPUT ;
    USE SIGNAL ;
    PORT
      LAYER M4 ;
        RECT  51.756 24.192 51.84 24.216 ;
    END
  END b_data[227]
  PIN b_data[228]
    DIRECTION OUTPUT ;
    USE SIGNAL ;
    PORT
      LAYER M4 ;
        RECT  51.756 24.336 51.84 24.36 ;
    END
  END b_data[228]
  PIN b_data[229]
    DIRECTION OUTPUT ;
    USE SIGNAL ;
    PORT
      LAYER M4 ;
        RECT  51.756 24.48 51.84 24.504 ;
    END
  END b_data[229]
  PIN b_data[22]
    DIRECTION OUTPUT ;
    USE SIGNAL ;
    PORT
      LAYER M4 ;
        RECT  51.756 13.104 51.84 13.128 ;
    END
  END b_data[22]
  PIN b_data[230]
    DIRECTION OUTPUT ;
    USE SIGNAL ;
    PORT
      LAYER M4 ;
        RECT  51.756 24.624 51.84 24.648 ;
    END
  END b_data[230]
  PIN b_data[231]
    DIRECTION OUTPUT ;
    USE SIGNAL ;
    PORT
      LAYER M4 ;
        RECT  51.756 24.768 51.84 24.792 ;
    END
  END b_data[231]
  PIN b_data[232]
    DIRECTION OUTPUT ;
    USE SIGNAL ;
    PORT
      LAYER M4 ;
        RECT  51.756 24.912 51.84 24.936 ;
    END
  END b_data[232]
  PIN b_data[233]
    DIRECTION OUTPUT ;
    USE SIGNAL ;
    PORT
      LAYER M4 ;
        RECT  51.756 25.056 51.84 25.08 ;
    END
  END b_data[233]
  PIN b_data[234]
    DIRECTION OUTPUT ;
    USE SIGNAL ;
    PORT
      LAYER M4 ;
        RECT  51.756 25.2 51.84 25.224 ;
    END
  END b_data[234]
  PIN b_data[235]
    DIRECTION OUTPUT ;
    USE SIGNAL ;
    PORT
      LAYER M4 ;
        RECT  51.756 25.344 51.84 25.368 ;
    END
  END b_data[235]
  PIN b_data[236]
    DIRECTION OUTPUT ;
    USE SIGNAL ;
    PORT
      LAYER M4 ;
        RECT  51.756 25.488 51.84 25.512 ;
    END
  END b_data[236]
  PIN b_data[237]
    DIRECTION OUTPUT ;
    USE SIGNAL ;
    PORT
      LAYER M4 ;
        RECT  51.756 25.632 51.84 25.656 ;
    END
  END b_data[237]
  PIN b_data[238]
    DIRECTION OUTPUT ;
    USE SIGNAL ;
    PORT
      LAYER M4 ;
        RECT  51.756 25.776 51.84 25.8 ;
    END
  END b_data[238]
  PIN b_data[239]
    DIRECTION OUTPUT ;
    USE SIGNAL ;
    PORT
      LAYER M4 ;
        RECT  51.756 25.92 51.84 25.944 ;
    END
  END b_data[239]
  PIN b_data[23]
    DIRECTION OUTPUT ;
    USE SIGNAL ;
    PORT
      LAYER M4 ;
        RECT  51.756 13.248 51.84 13.272 ;
    END
  END b_data[23]
  PIN b_data[240]
    DIRECTION OUTPUT ;
    USE SIGNAL ;
    PORT
      LAYER M4 ;
        RECT  51.756 26.064 51.84 26.088 ;
    END
  END b_data[240]
  PIN b_data[241]
    DIRECTION OUTPUT ;
    USE SIGNAL ;
    PORT
      LAYER M4 ;
        RECT  51.756 26.208 51.84 26.232 ;
    END
  END b_data[241]
  PIN b_data[242]
    DIRECTION OUTPUT ;
    USE SIGNAL ;
    PORT
      LAYER M4 ;
        RECT  51.756 26.352 51.84 26.376 ;
    END
  END b_data[242]
  PIN b_data[243]
    DIRECTION OUTPUT ;
    USE SIGNAL ;
    PORT
      LAYER M4 ;
        RECT  51.756 26.496 51.84 26.52 ;
    END
  END b_data[243]
  PIN b_data[244]
    DIRECTION OUTPUT ;
    USE SIGNAL ;
    PORT
      LAYER M4 ;
        RECT  51.756 26.64 51.84 26.664 ;
    END
  END b_data[244]
  PIN b_data[245]
    DIRECTION OUTPUT ;
    USE SIGNAL ;
    PORT
      LAYER M4 ;
        RECT  51.756 26.784 51.84 26.808 ;
    END
  END b_data[245]
  PIN b_data[246]
    DIRECTION OUTPUT ;
    USE SIGNAL ;
    PORT
      LAYER M4 ;
        RECT  51.756 26.928 51.84 26.952 ;
    END
  END b_data[246]
  PIN b_data[247]
    DIRECTION OUTPUT ;
    USE SIGNAL ;
    PORT
      LAYER M4 ;
        RECT  51.756 27.072 51.84 27.096 ;
    END
  END b_data[247]
  PIN b_data[248]
    DIRECTION OUTPUT ;
    USE SIGNAL ;
    PORT
      LAYER M4 ;
        RECT  51.756 27.216 51.84 27.24 ;
    END
  END b_data[248]
  PIN b_data[249]
    DIRECTION OUTPUT ;
    USE SIGNAL ;
    PORT
      LAYER M4 ;
        RECT  51.756 27.36 51.84 27.384 ;
    END
  END b_data[249]
  PIN b_data[24]
    DIRECTION OUTPUT ;
    USE SIGNAL ;
    PORT
      LAYER M4 ;
        RECT  51.756 13.392 51.84 13.416 ;
    END
  END b_data[24]
  PIN b_data[250]
    DIRECTION OUTPUT ;
    USE SIGNAL ;
    PORT
      LAYER M4 ;
        RECT  51.756 27.504 51.84 27.528 ;
    END
  END b_data[250]
  PIN b_data[251]
    DIRECTION OUTPUT ;
    USE SIGNAL ;
    PORT
      LAYER M4 ;
        RECT  51.756 27.648 51.84 27.672 ;
    END
  END b_data[251]
  PIN b_data[252]
    DIRECTION OUTPUT ;
    USE SIGNAL ;
    PORT
      LAYER M4 ;
        RECT  51.756 27.792 51.84 27.816 ;
    END
  END b_data[252]
  PIN b_data[253]
    DIRECTION OUTPUT ;
    USE SIGNAL ;
    PORT
      LAYER M4 ;
        RECT  51.756 27.936 51.84 27.96 ;
    END
  END b_data[253]
  PIN b_data[254]
    DIRECTION OUTPUT ;
    USE SIGNAL ;
    PORT
      LAYER M4 ;
        RECT  51.756 28.08 51.84 28.104 ;
    END
  END b_data[254]
  PIN b_data[255]
    DIRECTION OUTPUT ;
    USE SIGNAL ;
    PORT
      LAYER M4 ;
        RECT  51.756 28.224 51.84 28.248 ;
    END
  END b_data[255]
  PIN b_data[25]
    DIRECTION OUTPUT ;
    USE SIGNAL ;
    PORT
      LAYER M4 ;
        RECT  51.756 13.536 51.84 13.56 ;
    END
  END b_data[25]
  PIN b_data[26]
    DIRECTION OUTPUT ;
    USE SIGNAL ;
    PORT
      LAYER M4 ;
        RECT  51.756 13.68 51.84 13.704 ;
    END
  END b_data[26]
  PIN b_data[27]
    DIRECTION OUTPUT ;
    USE SIGNAL ;
    PORT
      LAYER M4 ;
        RECT  51.756 13.824 51.84 13.848 ;
    END
  END b_data[27]
  PIN b_data[28]
    DIRECTION OUTPUT ;
    USE SIGNAL ;
    PORT
      LAYER M4 ;
        RECT  51.756 13.968 51.84 13.992 ;
    END
  END b_data[28]
  PIN b_data[29]
    DIRECTION OUTPUT ;
    USE SIGNAL ;
    PORT
      LAYER M4 ;
        RECT  51.756 14.112 51.84 14.136 ;
    END
  END b_data[29]
  PIN b_data[2]
    DIRECTION OUTPUT ;
    USE SIGNAL ;
    PORT
      LAYER M4 ;
        RECT  51.756 10.224 51.84 10.248 ;
    END
  END b_data[2]
  PIN b_data[30]
    DIRECTION OUTPUT ;
    USE SIGNAL ;
    PORT
      LAYER M4 ;
        RECT  51.756 14.256 51.84 14.28 ;
    END
  END b_data[30]
  PIN b_data[31]
    DIRECTION OUTPUT ;
    USE SIGNAL ;
    PORT
      LAYER M4 ;
        RECT  51.756 14.4 51.84 14.424 ;
    END
  END b_data[31]
  PIN b_data[32]
    DIRECTION OUTPUT ;
    USE SIGNAL ;
    PORT
      LAYER M4 ;
        RECT  51.756 14.544 51.84 14.568 ;
    END
  END b_data[32]
  PIN b_data[33]
    DIRECTION OUTPUT ;
    USE SIGNAL ;
    PORT
      LAYER M4 ;
        RECT  51.756 14.688 51.84 14.712 ;
    END
  END b_data[33]
  PIN b_data[34]
    DIRECTION OUTPUT ;
    USE SIGNAL ;
    PORT
      LAYER M4 ;
        RECT  51.756 14.832 51.84 14.856 ;
    END
  END b_data[34]
  PIN b_data[35]
    DIRECTION OUTPUT ;
    USE SIGNAL ;
    PORT
      LAYER M4 ;
        RECT  51.756 14.976 51.84 15 ;
    END
  END b_data[35]
  PIN b_data[36]
    DIRECTION OUTPUT ;
    USE SIGNAL ;
    PORT
      LAYER M4 ;
        RECT  51.756 15.12 51.84 15.144 ;
    END
  END b_data[36]
  PIN b_data[37]
    DIRECTION OUTPUT ;
    USE SIGNAL ;
    PORT
      LAYER M4 ;
        RECT  51.756 15.264 51.84 15.288 ;
    END
  END b_data[37]
  PIN b_data[38]
    DIRECTION OUTPUT ;
    USE SIGNAL ;
    PORT
      LAYER M4 ;
        RECT  51.756 15.408 51.84 15.432 ;
    END
  END b_data[38]
  PIN b_data[39]
    DIRECTION OUTPUT ;
    USE SIGNAL ;
    PORT
      LAYER M4 ;
        RECT  51.756 15.552 51.84 15.576 ;
    END
  END b_data[39]
  PIN b_data[3]
    DIRECTION OUTPUT ;
    USE SIGNAL ;
    PORT
      LAYER M4 ;
        RECT  51.756 10.368 51.84 10.392 ;
    END
  END b_data[3]
  PIN b_data[40]
    DIRECTION OUTPUT ;
    USE SIGNAL ;
    PORT
      LAYER M4 ;
        RECT  51.756 15.696 51.84 15.72 ;
    END
  END b_data[40]
  PIN b_data[41]
    DIRECTION OUTPUT ;
    USE SIGNAL ;
    PORT
      LAYER M4 ;
        RECT  51.756 15.84 51.84 15.864 ;
    END
  END b_data[41]
  PIN b_data[42]
    DIRECTION OUTPUT ;
    USE SIGNAL ;
    PORT
      LAYER M4 ;
        RECT  51.756 15.984 51.84 16.008 ;
    END
  END b_data[42]
  PIN b_data[43]
    DIRECTION OUTPUT ;
    USE SIGNAL ;
    PORT
      LAYER M4 ;
        RECT  51.756 16.128 51.84 16.152 ;
    END
  END b_data[43]
  PIN b_data[44]
    DIRECTION OUTPUT ;
    USE SIGNAL ;
    PORT
      LAYER M4 ;
        RECT  51.756 16.272 51.84 16.296 ;
    END
  END b_data[44]
  PIN b_data[45]
    DIRECTION OUTPUT ;
    USE SIGNAL ;
    PORT
      LAYER M4 ;
        RECT  51.756 16.416 51.84 16.44 ;
    END
  END b_data[45]
  PIN b_data[46]
    DIRECTION OUTPUT ;
    USE SIGNAL ;
    PORT
      LAYER M4 ;
        RECT  51.756 16.56 51.84 16.584 ;
    END
  END b_data[46]
  PIN b_data[47]
    DIRECTION OUTPUT ;
    USE SIGNAL ;
    PORT
      LAYER M4 ;
        RECT  51.756 16.704 51.84 16.728 ;
    END
  END b_data[47]
  PIN b_data[48]
    DIRECTION OUTPUT ;
    USE SIGNAL ;
    PORT
      LAYER M4 ;
        RECT  51.756 16.848 51.84 16.872 ;
    END
  END b_data[48]
  PIN b_data[49]
    DIRECTION OUTPUT ;
    USE SIGNAL ;
    PORT
      LAYER M4 ;
        RECT  51.756 16.992 51.84 17.016 ;
    END
  END b_data[49]
  PIN b_data[4]
    DIRECTION OUTPUT ;
    USE SIGNAL ;
    PORT
      LAYER M4 ;
        RECT  51.756 10.512 51.84 10.536 ;
    END
  END b_data[4]
  PIN b_data[50]
    DIRECTION OUTPUT ;
    USE SIGNAL ;
    PORT
      LAYER M4 ;
        RECT  51.756 17.136 51.84 17.16 ;
    END
  END b_data[50]
  PIN b_data[51]
    DIRECTION OUTPUT ;
    USE SIGNAL ;
    PORT
      LAYER M4 ;
        RECT  51.756 17.28 51.84 17.304 ;
    END
  END b_data[51]
  PIN b_data[52]
    DIRECTION OUTPUT ;
    USE SIGNAL ;
    PORT
      LAYER M4 ;
        RECT  51.756 17.424 51.84 17.448 ;
    END
  END b_data[52]
  PIN b_data[53]
    DIRECTION OUTPUT ;
    USE SIGNAL ;
    PORT
      LAYER M4 ;
        RECT  51.756 17.568 51.84 17.592 ;
    END
  END b_data[53]
  PIN b_data[54]
    DIRECTION OUTPUT ;
    USE SIGNAL ;
    PORT
      LAYER M4 ;
        RECT  51.756 17.712 51.84 17.736 ;
    END
  END b_data[54]
  PIN b_data[55]
    DIRECTION OUTPUT ;
    USE SIGNAL ;
    PORT
      LAYER M4 ;
        RECT  51.756 17.856 51.84 17.88 ;
    END
  END b_data[55]
  PIN b_data[56]
    DIRECTION OUTPUT ;
    USE SIGNAL ;
    PORT
      LAYER M4 ;
        RECT  51.756 18 51.84 18.024 ;
    END
  END b_data[56]
  PIN b_data[57]
    DIRECTION OUTPUT ;
    USE SIGNAL ;
    PORT
      LAYER M4 ;
        RECT  51.756 18.144 51.84 18.168 ;
    END
  END b_data[57]
  PIN b_data[58]
    DIRECTION OUTPUT ;
    USE SIGNAL ;
    PORT
      LAYER M4 ;
        RECT  51.756 18.288 51.84 18.312 ;
    END
  END b_data[58]
  PIN b_data[59]
    DIRECTION OUTPUT ;
    USE SIGNAL ;
    PORT
      LAYER M4 ;
        RECT  51.756 18.432 51.84 18.456 ;
    END
  END b_data[59]
  PIN b_data[5]
    DIRECTION OUTPUT ;
    USE SIGNAL ;
    PORT
      LAYER M4 ;
        RECT  51.756 10.656 51.84 10.68 ;
    END
  END b_data[5]
  PIN b_data[60]
    DIRECTION OUTPUT ;
    USE SIGNAL ;
    PORT
      LAYER M4 ;
        RECT  51.756 18.576 51.84 18.6 ;
    END
  END b_data[60]
  PIN b_data[61]
    DIRECTION OUTPUT ;
    USE SIGNAL ;
    PORT
      LAYER M4 ;
        RECT  51.756 18.72 51.84 18.744 ;
    END
  END b_data[61]
  PIN b_data[62]
    DIRECTION OUTPUT ;
    USE SIGNAL ;
    PORT
      LAYER M4 ;
        RECT  51.756 18.864 51.84 18.888 ;
    END
  END b_data[62]
  PIN b_data[63]
    DIRECTION OUTPUT ;
    USE SIGNAL ;
    PORT
      LAYER M4 ;
        RECT  51.756 19.008 51.84 19.032 ;
    END
  END b_data[63]
  PIN b_data[64]
    DIRECTION OUTPUT ;
    USE SIGNAL ;
    PORT
      LAYER M4 ;
        RECT  51.756 19.152 51.84 19.176 ;
    END
  END b_data[64]
  PIN b_data[65]
    DIRECTION OUTPUT ;
    USE SIGNAL ;
    PORT
      LAYER M4 ;
        RECT  51.756 19.296 51.84 19.32 ;
    END
  END b_data[65]
  PIN b_data[66]
    DIRECTION OUTPUT ;
    USE SIGNAL ;
    PORT
      LAYER M4 ;
        RECT  51.756 19.44 51.84 19.464 ;
    END
  END b_data[66]
  PIN b_data[67]
    DIRECTION OUTPUT ;
    USE SIGNAL ;
    PORT
      LAYER M4 ;
        RECT  51.756 19.584 51.84 19.608 ;
    END
  END b_data[67]
  PIN b_data[68]
    DIRECTION OUTPUT ;
    USE SIGNAL ;
    PORT
      LAYER M4 ;
        RECT  51.756 19.728 51.84 19.752 ;
    END
  END b_data[68]
  PIN b_data[69]
    DIRECTION OUTPUT ;
    USE SIGNAL ;
    PORT
      LAYER M4 ;
        RECT  51.756 19.872 51.84 19.896 ;
    END
  END b_data[69]
  PIN b_data[6]
    DIRECTION OUTPUT ;
    USE SIGNAL ;
    PORT
      LAYER M4 ;
        RECT  51.756 10.8 51.84 10.824 ;
    END
  END b_data[6]
  PIN b_data[70]
    DIRECTION OUTPUT ;
    USE SIGNAL ;
    PORT
      LAYER M4 ;
        RECT  51.756 20.016 51.84 20.04 ;
    END
  END b_data[70]
  PIN b_data[71]
    DIRECTION OUTPUT ;
    USE SIGNAL ;
    PORT
      LAYER M4 ;
        RECT  51.756 20.16 51.84 20.184 ;
    END
  END b_data[71]
  PIN b_data[72]
    DIRECTION OUTPUT ;
    USE SIGNAL ;
    PORT
      LAYER M4 ;
        RECT  51.756 20.304 51.84 20.328 ;
    END
  END b_data[72]
  PIN b_data[73]
    DIRECTION OUTPUT ;
    USE SIGNAL ;
    PORT
      LAYER M4 ;
        RECT  51.756 20.448 51.84 20.472 ;
    END
  END b_data[73]
  PIN b_data[74]
    DIRECTION OUTPUT ;
    USE SIGNAL ;
    PORT
      LAYER M4 ;
        RECT  51.756 20.592 51.84 20.616 ;
    END
  END b_data[74]
  PIN b_data[75]
    DIRECTION OUTPUT ;
    USE SIGNAL ;
    PORT
      LAYER M4 ;
        RECT  51.756 20.736 51.84 20.76 ;
    END
  END b_data[75]
  PIN b_data[76]
    DIRECTION OUTPUT ;
    USE SIGNAL ;
    PORT
      LAYER M4 ;
        RECT  51.756 20.88 51.84 20.904 ;
    END
  END b_data[76]
  PIN b_data[77]
    DIRECTION OUTPUT ;
    USE SIGNAL ;
    PORT
      LAYER M4 ;
        RECT  51.756 21.024 51.84 21.048 ;
    END
  END b_data[77]
  PIN b_data[78]
    DIRECTION OUTPUT ;
    USE SIGNAL ;
    PORT
      LAYER M4 ;
        RECT  51.756 21.168 51.84 21.192 ;
    END
  END b_data[78]
  PIN b_data[79]
    DIRECTION OUTPUT ;
    USE SIGNAL ;
    PORT
      LAYER M4 ;
        RECT  51.756 21.312 51.84 21.336 ;
    END
  END b_data[79]
  PIN b_data[7]
    DIRECTION OUTPUT ;
    USE SIGNAL ;
    PORT
      LAYER M4 ;
        RECT  51.756 10.944 51.84 10.968 ;
    END
  END b_data[7]
  PIN b_data[80]
    DIRECTION OUTPUT ;
    USE SIGNAL ;
    PORT
      LAYER M4 ;
        RECT  51.756 21.456 51.84 21.48 ;
    END
  END b_data[80]
  PIN b_data[81]
    DIRECTION OUTPUT ;
    USE SIGNAL ;
    PORT
      LAYER M4 ;
        RECT  51.756 21.6 51.84 21.624 ;
    END
  END b_data[81]
  PIN b_data[82]
    DIRECTION OUTPUT ;
    USE SIGNAL ;
    PORT
      LAYER M4 ;
        RECT  51.756 21.744 51.84 21.768 ;
    END
  END b_data[82]
  PIN b_data[83]
    DIRECTION OUTPUT ;
    USE SIGNAL ;
    PORT
      LAYER M4 ;
        RECT  51.756 21.888 51.84 21.912 ;
    END
  END b_data[83]
  PIN b_data[84]
    DIRECTION OUTPUT ;
    USE SIGNAL ;
    PORT
      LAYER M4 ;
        RECT  51.756 22.032 51.84 22.056 ;
    END
  END b_data[84]
  PIN b_data[85]
    DIRECTION OUTPUT ;
    USE SIGNAL ;
    PORT
      LAYER M4 ;
        RECT  51.756 22.176 51.84 22.2 ;
    END
  END b_data[85]
  PIN b_data[86]
    DIRECTION OUTPUT ;
    USE SIGNAL ;
    PORT
      LAYER M4 ;
        RECT  51.756 22.32 51.84 22.344 ;
    END
  END b_data[86]
  PIN b_data[87]
    DIRECTION OUTPUT ;
    USE SIGNAL ;
    PORT
      LAYER M4 ;
        RECT  51.756 22.464 51.84 22.488 ;
    END
  END b_data[87]
  PIN b_data[88]
    DIRECTION OUTPUT ;
    USE SIGNAL ;
    PORT
      LAYER M4 ;
        RECT  51.756 22.608 51.84 22.632 ;
    END
  END b_data[88]
  PIN b_data[89]
    DIRECTION OUTPUT ;
    USE SIGNAL ;
    PORT
      LAYER M4 ;
        RECT  51.756 22.752 51.84 22.776 ;
    END
  END b_data[89]
  PIN b_data[8]
    DIRECTION OUTPUT ;
    USE SIGNAL ;
    PORT
      LAYER M4 ;
        RECT  51.756 11.088 51.84 11.112 ;
    END
  END b_data[8]
  PIN b_data[90]
    DIRECTION OUTPUT ;
    USE SIGNAL ;
    PORT
      LAYER M4 ;
        RECT  51.756 22.896 51.84 22.92 ;
    END
  END b_data[90]
  PIN b_data[91]
    DIRECTION OUTPUT ;
    USE SIGNAL ;
    PORT
      LAYER M4 ;
        RECT  51.756 23.04 51.84 23.064 ;
    END
  END b_data[91]
  PIN b_data[92]
    DIRECTION OUTPUT ;
    USE SIGNAL ;
    PORT
      LAYER M4 ;
        RECT  51.756 23.184 51.84 23.208 ;
    END
  END b_data[92]
  PIN b_data[93]
    DIRECTION OUTPUT ;
    USE SIGNAL ;
    PORT
      LAYER M4 ;
        RECT  51.756 23.328 51.84 23.352 ;
    END
  END b_data[93]
  PIN b_data[94]
    DIRECTION OUTPUT ;
    USE SIGNAL ;
    PORT
      LAYER M4 ;
        RECT  51.756 23.472 51.84 23.496 ;
    END
  END b_data[94]
  PIN b_data[95]
    DIRECTION OUTPUT ;
    USE SIGNAL ;
    PORT
      LAYER M4 ;
        RECT  51.756 23.616 51.84 23.64 ;
    END
  END b_data[95]
  PIN b_data[96]
    DIRECTION OUTPUT ;
    USE SIGNAL ;
    PORT
      LAYER M4 ;
        RECT  51.756 29.52 51.84 29.544 ;
    END
  END b_data[96]
  PIN b_data[97]
    DIRECTION OUTPUT ;
    USE SIGNAL ;
    PORT
      LAYER M4 ;
        RECT  51.756 29.664 51.84 29.688 ;
    END
  END b_data[97]
  PIN b_data[98]
    DIRECTION OUTPUT ;
    USE SIGNAL ;
    PORT
      LAYER M4 ;
        RECT  51.756 29.808 51.84 29.832 ;
    END
  END b_data[98]
  PIN b_data[99]
    DIRECTION OUTPUT ;
    USE SIGNAL ;
    PORT
      LAYER M4 ;
        RECT  51.756 29.952 51.84 29.976 ;
    END
  END b_data[99]
  PIN b_data[9]
    DIRECTION OUTPUT ;
    USE SIGNAL ;
    PORT
      LAYER M4 ;
        RECT  51.756 11.232 51.84 11.256 ;
    END
  END b_data[9]
  PIN b_we
    DIRECTION OUTPUT ;
    USE SIGNAL ;
    PORT
      LAYER M4 ;
        RECT  0 20.736 0.084 20.76 ;
    END
  END b_we
  PIN cfg_addr[0]
    DIRECTION INPUT ;
    USE SIGNAL ;
    PORT
      LAYER M4 ;
        RECT  0 20.88 0.084 20.904 ;
    END
  END cfg_addr[0]
  PIN cfg_addr[10]
    DIRECTION INPUT ;
    USE SIGNAL ;
    PORT
      LAYER M4 ;
        RECT  0 8.496 0.084 8.52 ;
    END
  END cfg_addr[10]
  PIN cfg_addr[11]
    DIRECTION INPUT ;
    USE SIGNAL ;
    PORT
      LAYER M4 ;
        RECT  0 8.64 0.084 8.664 ;
    END
  END cfg_addr[11]
  PIN cfg_addr[1]
    DIRECTION INPUT ;
    USE SIGNAL ;
    PORT
      LAYER M4 ;
        RECT  0 21.024 0.084 21.048 ;
    END
  END cfg_addr[1]
  PIN cfg_addr[2]
    DIRECTION INPUT ;
    USE SIGNAL ;
    PORT
      LAYER M4 ;
        RECT  0 21.168 0.084 21.192 ;
    END
  END cfg_addr[2]
  PIN cfg_addr[3]
    DIRECTION INPUT ;
    USE SIGNAL ;
    PORT
      LAYER M4 ;
        RECT  0 21.312 0.084 21.336 ;
    END
  END cfg_addr[3]
  PIN cfg_addr[4]
    DIRECTION INPUT ;
    USE SIGNAL ;
    PORT
      LAYER M4 ;
        RECT  0 21.456 0.084 21.48 ;
    END
  END cfg_addr[4]
  PIN cfg_addr[5]
    DIRECTION INPUT ;
    USE SIGNAL ;
    PORT
      LAYER M4 ;
        RECT  0 21.6 0.084 21.624 ;
    END
  END cfg_addr[5]
  PIN cfg_addr[6]
    DIRECTION INPUT ;
    USE SIGNAL ;
    PORT
      LAYER M4 ;
        RECT  0 21.744 0.084 21.768 ;
    END
  END cfg_addr[6]
  PIN cfg_addr[7]
    DIRECTION INPUT ;
    USE SIGNAL ;
    PORT
      LAYER M4 ;
        RECT  0 21.888 0.084 21.912 ;
    END
  END cfg_addr[7]
  PIN cfg_addr[8]
    DIRECTION INPUT ;
    USE SIGNAL ;
    PORT
      LAYER M4 ;
        RECT  0 22.032 0.084 22.056 ;
    END
  END cfg_addr[8]
  PIN cfg_addr[9]
    DIRECTION INPUT ;
    USE SIGNAL ;
    PORT
      LAYER M4 ;
        RECT  0 22.176 0.084 22.2 ;
    END
  END cfg_addr[9]
  PIN cfg_data[0]
    DIRECTION INPUT ;
    USE SIGNAL ;
    PORT
      LAYER M5 ;
        RECT  23.472 51.756 23.496 51.84 ;
    END
  END cfg_data[0]
  PIN cfg_data[100]
    DIRECTION INPUT ;
    USE SIGNAL ;
    PORT
      LAYER M5 ;
        RECT  37.872 51.756 37.896 51.84 ;
    END
  END cfg_data[100]
  PIN cfg_data[101]
    DIRECTION INPUT ;
    USE SIGNAL ;
    PORT
      LAYER M5 ;
        RECT  38.016 51.756 38.04 51.84 ;
    END
  END cfg_data[101]
  PIN cfg_data[102]
    DIRECTION INPUT ;
    USE SIGNAL ;
    PORT
      LAYER M5 ;
        RECT  38.16 51.756 38.184 51.84 ;
    END
  END cfg_data[102]
  PIN cfg_data[103]
    DIRECTION INPUT ;
    USE SIGNAL ;
    PORT
      LAYER M5 ;
        RECT  38.304 51.756 38.328 51.84 ;
    END
  END cfg_data[103]
  PIN cfg_data[104]
    DIRECTION INPUT ;
    USE SIGNAL ;
    PORT
      LAYER M5 ;
        RECT  38.448 51.756 38.472 51.84 ;
    END
  END cfg_data[104]
  PIN cfg_data[105]
    DIRECTION INPUT ;
    USE SIGNAL ;
    PORT
      LAYER M5 ;
        RECT  38.592 51.756 38.616 51.84 ;
    END
  END cfg_data[105]
  PIN cfg_data[106]
    DIRECTION INPUT ;
    USE SIGNAL ;
    PORT
      LAYER M5 ;
        RECT  38.736 51.756 38.76 51.84 ;
    END
  END cfg_data[106]
  PIN cfg_data[107]
    DIRECTION INPUT ;
    USE SIGNAL ;
    PORT
      LAYER M5 ;
        RECT  38.88 51.756 38.904 51.84 ;
    END
  END cfg_data[107]
  PIN cfg_data[108]
    DIRECTION INPUT ;
    USE SIGNAL ;
    PORT
      LAYER M5 ;
        RECT  39.024 51.756 39.048 51.84 ;
    END
  END cfg_data[108]
  PIN cfg_data[109]
    DIRECTION INPUT ;
    USE SIGNAL ;
    PORT
      LAYER M5 ;
        RECT  39.168 51.756 39.192 51.84 ;
    END
  END cfg_data[109]
  PIN cfg_data[10]
    DIRECTION INPUT ;
    USE SIGNAL ;
    PORT
      LAYER M5 ;
        RECT  24.912 51.756 24.936 51.84 ;
    END
  END cfg_data[10]
  PIN cfg_data[110]
    DIRECTION INPUT ;
    USE SIGNAL ;
    PORT
      LAYER M5 ;
        RECT  39.312 51.756 39.336 51.84 ;
    END
  END cfg_data[110]
  PIN cfg_data[111]
    DIRECTION INPUT ;
    USE SIGNAL ;
    PORT
      LAYER M5 ;
        RECT  39.456 51.756 39.48 51.84 ;
    END
  END cfg_data[111]
  PIN cfg_data[112]
    DIRECTION INPUT ;
    USE SIGNAL ;
    PORT
      LAYER M5 ;
        RECT  39.6 51.756 39.624 51.84 ;
    END
  END cfg_data[112]
  PIN cfg_data[113]
    DIRECTION INPUT ;
    USE SIGNAL ;
    PORT
      LAYER M5 ;
        RECT  39.744 51.756 39.768 51.84 ;
    END
  END cfg_data[113]
  PIN cfg_data[114]
    DIRECTION INPUT ;
    USE SIGNAL ;
    PORT
      LAYER M5 ;
        RECT  39.888 51.756 39.912 51.84 ;
    END
  END cfg_data[114]
  PIN cfg_data[115]
    DIRECTION INPUT ;
    USE SIGNAL ;
    PORT
      LAYER M5 ;
        RECT  40.032 51.756 40.056 51.84 ;
    END
  END cfg_data[115]
  PIN cfg_data[116]
    DIRECTION INPUT ;
    USE SIGNAL ;
    PORT
      LAYER M5 ;
        RECT  40.176 51.756 40.2 51.84 ;
    END
  END cfg_data[116]
  PIN cfg_data[117]
    DIRECTION INPUT ;
    USE SIGNAL ;
    PORT
      LAYER M5 ;
        RECT  40.32 51.756 40.344 51.84 ;
    END
  END cfg_data[117]
  PIN cfg_data[118]
    DIRECTION INPUT ;
    USE SIGNAL ;
    PORT
      LAYER M5 ;
        RECT  40.464 51.756 40.488 51.84 ;
    END
  END cfg_data[118]
  PIN cfg_data[119]
    DIRECTION INPUT ;
    USE SIGNAL ;
    PORT
      LAYER M5 ;
        RECT  40.608 51.756 40.632 51.84 ;
    END
  END cfg_data[119]
  PIN cfg_data[11]
    DIRECTION INPUT ;
    USE SIGNAL ;
    PORT
      LAYER M5 ;
        RECT  25.056 51.756 25.08 51.84 ;
    END
  END cfg_data[11]
  PIN cfg_data[120]
    DIRECTION INPUT ;
    USE SIGNAL ;
    PORT
      LAYER M5 ;
        RECT  40.752 51.756 40.776 51.84 ;
    END
  END cfg_data[120]
  PIN cfg_data[121]
    DIRECTION INPUT ;
    USE SIGNAL ;
    PORT
      LAYER M5 ;
        RECT  40.896 51.756 40.92 51.84 ;
    END
  END cfg_data[121]
  PIN cfg_data[122]
    DIRECTION INPUT ;
    USE SIGNAL ;
    PORT
      LAYER M5 ;
        RECT  41.04 51.756 41.064 51.84 ;
    END
  END cfg_data[122]
  PIN cfg_data[123]
    DIRECTION INPUT ;
    USE SIGNAL ;
    PORT
      LAYER M5 ;
        RECT  41.184 51.756 41.208 51.84 ;
    END
  END cfg_data[123]
  PIN cfg_data[124]
    DIRECTION INPUT ;
    USE SIGNAL ;
    PORT
      LAYER M5 ;
        RECT  41.328 51.756 41.352 51.84 ;
    END
  END cfg_data[124]
  PIN cfg_data[125]
    DIRECTION INPUT ;
    USE SIGNAL ;
    PORT
      LAYER M5 ;
        RECT  41.472 51.756 41.496 51.84 ;
    END
  END cfg_data[125]
  PIN cfg_data[126]
    DIRECTION INPUT ;
    USE SIGNAL ;
    PORT
      LAYER M5 ;
        RECT  41.616 51.756 41.64 51.84 ;
    END
  END cfg_data[126]
  PIN cfg_data[127]
    DIRECTION INPUT ;
    USE SIGNAL ;
    PORT
      LAYER M5 ;
        RECT  41.76 51.756 41.784 51.84 ;
    END
  END cfg_data[127]
  PIN cfg_data[128]
    DIRECTION INPUT ;
    USE SIGNAL ;
    PORT
      LAYER M5 ;
        RECT  32.688 51.756 32.712 51.84 ;
    END
  END cfg_data[128]
  PIN cfg_data[129]
    DIRECTION INPUT ;
    USE SIGNAL ;
    PORT
      LAYER M5 ;
        RECT  32.832 51.756 32.856 51.84 ;
    END
  END cfg_data[129]
  PIN cfg_data[12]
    DIRECTION INPUT ;
    USE SIGNAL ;
    PORT
      LAYER M5 ;
        RECT  25.2 51.756 25.224 51.84 ;
    END
  END cfg_data[12]
  PIN cfg_data[130]
    DIRECTION INPUT ;
    USE SIGNAL ;
    PORT
      LAYER M5 ;
        RECT  32.976 51.756 33 51.84 ;
    END
  END cfg_data[130]
  PIN cfg_data[131]
    DIRECTION INPUT ;
    USE SIGNAL ;
    PORT
      LAYER M5 ;
        RECT  33.12 51.756 33.144 51.84 ;
    END
  END cfg_data[131]
  PIN cfg_data[132]
    DIRECTION INPUT ;
    USE SIGNAL ;
    PORT
      LAYER M5 ;
        RECT  33.264 51.756 33.288 51.84 ;
    END
  END cfg_data[132]
  PIN cfg_data[133]
    DIRECTION INPUT ;
    USE SIGNAL ;
    PORT
      LAYER M5 ;
        RECT  33.408 51.756 33.432 51.84 ;
    END
  END cfg_data[133]
  PIN cfg_data[134]
    DIRECTION INPUT ;
    USE SIGNAL ;
    PORT
      LAYER M5 ;
        RECT  33.552 51.756 33.576 51.84 ;
    END
  END cfg_data[134]
  PIN cfg_data[135]
    DIRECTION INPUT ;
    USE SIGNAL ;
    PORT
      LAYER M5 ;
        RECT  33.696 51.756 33.72 51.84 ;
    END
  END cfg_data[135]
  PIN cfg_data[136]
    DIRECTION INPUT ;
    USE SIGNAL ;
    PORT
      LAYER M5 ;
        RECT  33.84 51.756 33.864 51.84 ;
    END
  END cfg_data[136]
  PIN cfg_data[137]
    DIRECTION INPUT ;
    USE SIGNAL ;
    PORT
      LAYER M5 ;
        RECT  33.984 51.756 34.008 51.84 ;
    END
  END cfg_data[137]
  PIN cfg_data[138]
    DIRECTION INPUT ;
    USE SIGNAL ;
    PORT
      LAYER M5 ;
        RECT  34.128 51.756 34.152 51.84 ;
    END
  END cfg_data[138]
  PIN cfg_data[139]
    DIRECTION INPUT ;
    USE SIGNAL ;
    PORT
      LAYER M5 ;
        RECT  34.272 51.756 34.296 51.84 ;
    END
  END cfg_data[139]
  PIN cfg_data[13]
    DIRECTION INPUT ;
    USE SIGNAL ;
    PORT
      LAYER M5 ;
        RECT  25.344 51.756 25.368 51.84 ;
    END
  END cfg_data[13]
  PIN cfg_data[140]
    DIRECTION INPUT ;
    USE SIGNAL ;
    PORT
      LAYER M5 ;
        RECT  34.416 51.756 34.44 51.84 ;
    END
  END cfg_data[140]
  PIN cfg_data[141]
    DIRECTION INPUT ;
    USE SIGNAL ;
    PORT
      LAYER M5 ;
        RECT  34.56 51.756 34.584 51.84 ;
    END
  END cfg_data[141]
  PIN cfg_data[142]
    DIRECTION INPUT ;
    USE SIGNAL ;
    PORT
      LAYER M5 ;
        RECT  34.704 51.756 34.728 51.84 ;
    END
  END cfg_data[142]
  PIN cfg_data[143]
    DIRECTION INPUT ;
    USE SIGNAL ;
    PORT
      LAYER M5 ;
        RECT  34.848 51.756 34.872 51.84 ;
    END
  END cfg_data[143]
  PIN cfg_data[144]
    DIRECTION INPUT ;
    USE SIGNAL ;
    PORT
      LAYER M5 ;
        RECT  34.992 51.756 35.016 51.84 ;
    END
  END cfg_data[144]
  PIN cfg_data[145]
    DIRECTION INPUT ;
    USE SIGNAL ;
    PORT
      LAYER M5 ;
        RECT  35.136 51.756 35.16 51.84 ;
    END
  END cfg_data[145]
  PIN cfg_data[146]
    DIRECTION INPUT ;
    USE SIGNAL ;
    PORT
      LAYER M5 ;
        RECT  35.28 51.756 35.304 51.84 ;
    END
  END cfg_data[146]
  PIN cfg_data[147]
    DIRECTION INPUT ;
    USE SIGNAL ;
    PORT
      LAYER M5 ;
        RECT  35.424 51.756 35.448 51.84 ;
    END
  END cfg_data[147]
  PIN cfg_data[148]
    DIRECTION INPUT ;
    USE SIGNAL ;
    PORT
      LAYER M5 ;
        RECT  35.568 51.756 35.592 51.84 ;
    END
  END cfg_data[148]
  PIN cfg_data[149]
    DIRECTION INPUT ;
    USE SIGNAL ;
    PORT
      LAYER M5 ;
        RECT  35.712 51.756 35.736 51.84 ;
    END
  END cfg_data[149]
  PIN cfg_data[14]
    DIRECTION INPUT ;
    USE SIGNAL ;
    PORT
      LAYER M5 ;
        RECT  25.488 51.756 25.512 51.84 ;
    END
  END cfg_data[14]
  PIN cfg_data[150]
    DIRECTION INPUT ;
    USE SIGNAL ;
    PORT
      LAYER M5 ;
        RECT  35.856 51.756 35.88 51.84 ;
    END
  END cfg_data[150]
  PIN cfg_data[151]
    DIRECTION INPUT ;
    USE SIGNAL ;
    PORT
      LAYER M5 ;
        RECT  36 51.756 36.024 51.84 ;
    END
  END cfg_data[151]
  PIN cfg_data[152]
    DIRECTION INPUT ;
    USE SIGNAL ;
    PORT
      LAYER M5 ;
        RECT  36.144 51.756 36.168 51.84 ;
    END
  END cfg_data[152]
  PIN cfg_data[153]
    DIRECTION INPUT ;
    USE SIGNAL ;
    PORT
      LAYER M5 ;
        RECT  36.288 51.756 36.312 51.84 ;
    END
  END cfg_data[153]
  PIN cfg_data[154]
    DIRECTION INPUT ;
    USE SIGNAL ;
    PORT
      LAYER M5 ;
        RECT  36.432 51.756 36.456 51.84 ;
    END
  END cfg_data[154]
  PIN cfg_data[155]
    DIRECTION INPUT ;
    USE SIGNAL ;
    PORT
      LAYER M5 ;
        RECT  36.576 51.756 36.6 51.84 ;
    END
  END cfg_data[155]
  PIN cfg_data[156]
    DIRECTION INPUT ;
    USE SIGNAL ;
    PORT
      LAYER M5 ;
        RECT  36.72 51.756 36.744 51.84 ;
    END
  END cfg_data[156]
  PIN cfg_data[157]
    DIRECTION INPUT ;
    USE SIGNAL ;
    PORT
      LAYER M5 ;
        RECT  36.864 51.756 36.888 51.84 ;
    END
  END cfg_data[157]
  PIN cfg_data[158]
    DIRECTION INPUT ;
    USE SIGNAL ;
    PORT
      LAYER M5 ;
        RECT  37.008 51.756 37.032 51.84 ;
    END
  END cfg_data[158]
  PIN cfg_data[159]
    DIRECTION INPUT ;
    USE SIGNAL ;
    PORT
      LAYER M5 ;
        RECT  37.152 51.756 37.176 51.84 ;
    END
  END cfg_data[159]
  PIN cfg_data[15]
    DIRECTION INPUT ;
    USE SIGNAL ;
    PORT
      LAYER M5 ;
        RECT  25.632 51.756 25.656 51.84 ;
    END
  END cfg_data[15]
  PIN cfg_data[160]
    DIRECTION INPUT ;
    USE SIGNAL ;
    PORT
      LAYER M5 ;
        RECT  17.712 51.756 17.736 51.84 ;
    END
  END cfg_data[160]
  PIN cfg_data[161]
    DIRECTION INPUT ;
    USE SIGNAL ;
    PORT
      LAYER M5 ;
        RECT  17.856 51.756 17.88 51.84 ;
    END
  END cfg_data[161]
  PIN cfg_data[162]
    DIRECTION INPUT ;
    USE SIGNAL ;
    PORT
      LAYER M5 ;
        RECT  18 51.756 18.024 51.84 ;
    END
  END cfg_data[162]
  PIN cfg_data[163]
    DIRECTION INPUT ;
    USE SIGNAL ;
    PORT
      LAYER M5 ;
        RECT  18.144 51.756 18.168 51.84 ;
    END
  END cfg_data[163]
  PIN cfg_data[164]
    DIRECTION INPUT ;
    USE SIGNAL ;
    PORT
      LAYER M5 ;
        RECT  18.288 51.756 18.312 51.84 ;
    END
  END cfg_data[164]
  PIN cfg_data[165]
    DIRECTION INPUT ;
    USE SIGNAL ;
    PORT
      LAYER M5 ;
        RECT  18.432 51.756 18.456 51.84 ;
    END
  END cfg_data[165]
  PIN cfg_data[166]
    DIRECTION INPUT ;
    USE SIGNAL ;
    PORT
      LAYER M5 ;
        RECT  18.576 51.756 18.6 51.84 ;
    END
  END cfg_data[166]
  PIN cfg_data[167]
    DIRECTION INPUT ;
    USE SIGNAL ;
    PORT
      LAYER M5 ;
        RECT  18.72 51.756 18.744 51.84 ;
    END
  END cfg_data[167]
  PIN cfg_data[168]
    DIRECTION INPUT ;
    USE SIGNAL ;
    PORT
      LAYER M5 ;
        RECT  18.864 51.756 18.888 51.84 ;
    END
  END cfg_data[168]
  PIN cfg_data[169]
    DIRECTION INPUT ;
    USE SIGNAL ;
    PORT
      LAYER M5 ;
        RECT  19.008 51.756 19.032 51.84 ;
    END
  END cfg_data[169]
  PIN cfg_data[16]
    DIRECTION INPUT ;
    USE SIGNAL ;
    PORT
      LAYER M5 ;
        RECT  25.776 51.756 25.8 51.84 ;
    END
  END cfg_data[16]
  PIN cfg_data[170]
    DIRECTION INPUT ;
    USE SIGNAL ;
    PORT
      LAYER M5 ;
        RECT  19.152 51.756 19.176 51.84 ;
    END
  END cfg_data[170]
  PIN cfg_data[171]
    DIRECTION INPUT ;
    USE SIGNAL ;
    PORT
      LAYER M5 ;
        RECT  19.296 51.756 19.32 51.84 ;
    END
  END cfg_data[171]
  PIN cfg_data[172]
    DIRECTION INPUT ;
    USE SIGNAL ;
    PORT
      LAYER M5 ;
        RECT  19.44 51.756 19.464 51.84 ;
    END
  END cfg_data[172]
  PIN cfg_data[173]
    DIRECTION INPUT ;
    USE SIGNAL ;
    PORT
      LAYER M5 ;
        RECT  19.584 51.756 19.608 51.84 ;
    END
  END cfg_data[173]
  PIN cfg_data[174]
    DIRECTION INPUT ;
    USE SIGNAL ;
    PORT
      LAYER M5 ;
        RECT  19.728 51.756 19.752 51.84 ;
    END
  END cfg_data[174]
  PIN cfg_data[175]
    DIRECTION INPUT ;
    USE SIGNAL ;
    PORT
      LAYER M5 ;
        RECT  19.872 51.756 19.896 51.84 ;
    END
  END cfg_data[175]
  PIN cfg_data[176]
    DIRECTION INPUT ;
    USE SIGNAL ;
    PORT
      LAYER M5 ;
        RECT  20.016 51.756 20.04 51.84 ;
    END
  END cfg_data[176]
  PIN cfg_data[177]
    DIRECTION INPUT ;
    USE SIGNAL ;
    PORT
      LAYER M5 ;
        RECT  20.16 51.756 20.184 51.84 ;
    END
  END cfg_data[177]
  PIN cfg_data[178]
    DIRECTION INPUT ;
    USE SIGNAL ;
    PORT
      LAYER M5 ;
        RECT  20.304 51.756 20.328 51.84 ;
    END
  END cfg_data[178]
  PIN cfg_data[179]
    DIRECTION INPUT ;
    USE SIGNAL ;
    PORT
      LAYER M5 ;
        RECT  20.448 51.756 20.472 51.84 ;
    END
  END cfg_data[179]
  PIN cfg_data[17]
    DIRECTION INPUT ;
    USE SIGNAL ;
    PORT
      LAYER M5 ;
        RECT  25.92 51.756 25.944 51.84 ;
    END
  END cfg_data[17]
  PIN cfg_data[180]
    DIRECTION INPUT ;
    USE SIGNAL ;
    PORT
      LAYER M5 ;
        RECT  20.592 51.756 20.616 51.84 ;
    END
  END cfg_data[180]
  PIN cfg_data[181]
    DIRECTION INPUT ;
    USE SIGNAL ;
    PORT
      LAYER M5 ;
        RECT  20.736 51.756 20.76 51.84 ;
    END
  END cfg_data[181]
  PIN cfg_data[182]
    DIRECTION INPUT ;
    USE SIGNAL ;
    PORT
      LAYER M5 ;
        RECT  20.88 51.756 20.904 51.84 ;
    END
  END cfg_data[182]
  PIN cfg_data[183]
    DIRECTION INPUT ;
    USE SIGNAL ;
    PORT
      LAYER M5 ;
        RECT  21.024 51.756 21.048 51.84 ;
    END
  END cfg_data[183]
  PIN cfg_data[184]
    DIRECTION INPUT ;
    USE SIGNAL ;
    PORT
      LAYER M5 ;
        RECT  21.168 51.756 21.192 51.84 ;
    END
  END cfg_data[184]
  PIN cfg_data[185]
    DIRECTION INPUT ;
    USE SIGNAL ;
    PORT
      LAYER M5 ;
        RECT  21.312 51.756 21.336 51.84 ;
    END
  END cfg_data[185]
  PIN cfg_data[186]
    DIRECTION INPUT ;
    USE SIGNAL ;
    PORT
      LAYER M5 ;
        RECT  21.456 51.756 21.48 51.84 ;
    END
  END cfg_data[186]
  PIN cfg_data[187]
    DIRECTION INPUT ;
    USE SIGNAL ;
    PORT
      LAYER M5 ;
        RECT  21.6 51.756 21.624 51.84 ;
    END
  END cfg_data[187]
  PIN cfg_data[188]
    DIRECTION INPUT ;
    USE SIGNAL ;
    PORT
      LAYER M5 ;
        RECT  21.744 51.756 21.768 51.84 ;
    END
  END cfg_data[188]
  PIN cfg_data[189]
    DIRECTION INPUT ;
    USE SIGNAL ;
    PORT
      LAYER M5 ;
        RECT  21.888 51.756 21.912 51.84 ;
    END
  END cfg_data[189]
  PIN cfg_data[18]
    DIRECTION INPUT ;
    USE SIGNAL ;
    PORT
      LAYER M5 ;
        RECT  26.064 51.756 26.088 51.84 ;
    END
  END cfg_data[18]
  PIN cfg_data[190]
    DIRECTION INPUT ;
    USE SIGNAL ;
    PORT
      LAYER M5 ;
        RECT  22.032 51.756 22.056 51.84 ;
    END
  END cfg_data[190]
  PIN cfg_data[191]
    DIRECTION INPUT ;
    USE SIGNAL ;
    PORT
      LAYER M5 ;
        RECT  22.176 51.756 22.2 51.84 ;
    END
  END cfg_data[191]
  PIN cfg_data[192]
    DIRECTION INPUT ;
    USE SIGNAL ;
    PORT
      LAYER M5 ;
        RECT  8.496 51.756 8.52 51.84 ;
    END
  END cfg_data[192]
  PIN cfg_data[193]
    DIRECTION INPUT ;
    USE SIGNAL ;
    PORT
      LAYER M5 ;
        RECT  8.64 51.756 8.664 51.84 ;
    END
  END cfg_data[193]
  PIN cfg_data[194]
    DIRECTION INPUT ;
    USE SIGNAL ;
    PORT
      LAYER M5 ;
        RECT  8.784 51.756 8.808 51.84 ;
    END
  END cfg_data[194]
  PIN cfg_data[195]
    DIRECTION INPUT ;
    USE SIGNAL ;
    PORT
      LAYER M5 ;
        RECT  8.928 51.756 8.952 51.84 ;
    END
  END cfg_data[195]
  PIN cfg_data[196]
    DIRECTION INPUT ;
    USE SIGNAL ;
    PORT
      LAYER M5 ;
        RECT  9.072 51.756 9.096 51.84 ;
    END
  END cfg_data[196]
  PIN cfg_data[197]
    DIRECTION INPUT ;
    USE SIGNAL ;
    PORT
      LAYER M5 ;
        RECT  9.216 51.756 9.24 51.84 ;
    END
  END cfg_data[197]
  PIN cfg_data[198]
    DIRECTION INPUT ;
    USE SIGNAL ;
    PORT
      LAYER M5 ;
        RECT  9.36 51.756 9.384 51.84 ;
    END
  END cfg_data[198]
  PIN cfg_data[199]
    DIRECTION INPUT ;
    USE SIGNAL ;
    PORT
      LAYER M5 ;
        RECT  9.504 51.756 9.528 51.84 ;
    END
  END cfg_data[199]
  PIN cfg_data[19]
    DIRECTION INPUT ;
    USE SIGNAL ;
    PORT
      LAYER M5 ;
        RECT  26.208 51.756 26.232 51.84 ;
    END
  END cfg_data[19]
  PIN cfg_data[1]
    DIRECTION INPUT ;
    USE SIGNAL ;
    PORT
      LAYER M5 ;
        RECT  23.616 51.756 23.64 51.84 ;
    END
  END cfg_data[1]
  PIN cfg_data[200]
    DIRECTION INPUT ;
    USE SIGNAL ;
    PORT
      LAYER M5 ;
        RECT  9.648 51.756 9.672 51.84 ;
    END
  END cfg_data[200]
  PIN cfg_data[201]
    DIRECTION INPUT ;
    USE SIGNAL ;
    PORT
      LAYER M5 ;
        RECT  9.792 51.756 9.816 51.84 ;
    END
  END cfg_data[201]
  PIN cfg_data[202]
    DIRECTION INPUT ;
    USE SIGNAL ;
    PORT
      LAYER M5 ;
        RECT  9.936 51.756 9.96 51.84 ;
    END
  END cfg_data[202]
  PIN cfg_data[203]
    DIRECTION INPUT ;
    USE SIGNAL ;
    PORT
      LAYER M5 ;
        RECT  10.08 51.756 10.104 51.84 ;
    END
  END cfg_data[203]
  PIN cfg_data[204]
    DIRECTION INPUT ;
    USE SIGNAL ;
    PORT
      LAYER M5 ;
        RECT  10.224 51.756 10.248 51.84 ;
    END
  END cfg_data[204]
  PIN cfg_data[205]
    DIRECTION INPUT ;
    USE SIGNAL ;
    PORT
      LAYER M5 ;
        RECT  10.368 51.756 10.392 51.84 ;
    END
  END cfg_data[205]
  PIN cfg_data[206]
    DIRECTION INPUT ;
    USE SIGNAL ;
    PORT
      LAYER M5 ;
        RECT  10.512 51.756 10.536 51.84 ;
    END
  END cfg_data[206]
  PIN cfg_data[207]
    DIRECTION INPUT ;
    USE SIGNAL ;
    PORT
      LAYER M5 ;
        RECT  10.656 51.756 10.68 51.84 ;
    END
  END cfg_data[207]
  PIN cfg_data[208]
    DIRECTION INPUT ;
    USE SIGNAL ;
    PORT
      LAYER M5 ;
        RECT  10.8 51.756 10.824 51.84 ;
    END
  END cfg_data[208]
  PIN cfg_data[209]
    DIRECTION INPUT ;
    USE SIGNAL ;
    PORT
      LAYER M5 ;
        RECT  10.944 51.756 10.968 51.84 ;
    END
  END cfg_data[209]
  PIN cfg_data[20]
    DIRECTION INPUT ;
    USE SIGNAL ;
    PORT
      LAYER M5 ;
        RECT  26.352 51.756 26.376 51.84 ;
    END
  END cfg_data[20]
  PIN cfg_data[210]
    DIRECTION INPUT ;
    USE SIGNAL ;
    PORT
      LAYER M5 ;
        RECT  11.088 51.756 11.112 51.84 ;
    END
  END cfg_data[210]
  PIN cfg_data[211]
    DIRECTION INPUT ;
    USE SIGNAL ;
    PORT
      LAYER M5 ;
        RECT  11.232 51.756 11.256 51.84 ;
    END
  END cfg_data[211]
  PIN cfg_data[212]
    DIRECTION INPUT ;
    USE SIGNAL ;
    PORT
      LAYER M5 ;
        RECT  11.376 51.756 11.4 51.84 ;
    END
  END cfg_data[212]
  PIN cfg_data[213]
    DIRECTION INPUT ;
    USE SIGNAL ;
    PORT
      LAYER M5 ;
        RECT  11.52 51.756 11.544 51.84 ;
    END
  END cfg_data[213]
  PIN cfg_data[214]
    DIRECTION INPUT ;
    USE SIGNAL ;
    PORT
      LAYER M5 ;
        RECT  11.664 51.756 11.688 51.84 ;
    END
  END cfg_data[214]
  PIN cfg_data[215]
    DIRECTION INPUT ;
    USE SIGNAL ;
    PORT
      LAYER M5 ;
        RECT  11.808 51.756 11.832 51.84 ;
    END
  END cfg_data[215]
  PIN cfg_data[216]
    DIRECTION INPUT ;
    USE SIGNAL ;
    PORT
      LAYER M5 ;
        RECT  11.952 51.756 11.976 51.84 ;
    END
  END cfg_data[216]
  PIN cfg_data[217]
    DIRECTION INPUT ;
    USE SIGNAL ;
    PORT
      LAYER M5 ;
        RECT  12.096 51.756 12.12 51.84 ;
    END
  END cfg_data[217]
  PIN cfg_data[218]
    DIRECTION INPUT ;
    USE SIGNAL ;
    PORT
      LAYER M5 ;
        RECT  12.24 51.756 12.264 51.84 ;
    END
  END cfg_data[218]
  PIN cfg_data[219]
    DIRECTION INPUT ;
    USE SIGNAL ;
    PORT
      LAYER M5 ;
        RECT  12.384 51.756 12.408 51.84 ;
    END
  END cfg_data[219]
  PIN cfg_data[21]
    DIRECTION INPUT ;
    USE SIGNAL ;
    PORT
      LAYER M5 ;
        RECT  26.496 51.756 26.52 51.84 ;
    END
  END cfg_data[21]
  PIN cfg_data[220]
    DIRECTION INPUT ;
    USE SIGNAL ;
    PORT
      LAYER M5 ;
        RECT  12.528 51.756 12.552 51.84 ;
    END
  END cfg_data[220]
  PIN cfg_data[221]
    DIRECTION INPUT ;
    USE SIGNAL ;
    PORT
      LAYER M5 ;
        RECT  12.672 51.756 12.696 51.84 ;
    END
  END cfg_data[221]
  PIN cfg_data[222]
    DIRECTION INPUT ;
    USE SIGNAL ;
    PORT
      LAYER M5 ;
        RECT  12.816 51.756 12.84 51.84 ;
    END
  END cfg_data[222]
  PIN cfg_data[223]
    DIRECTION INPUT ;
    USE SIGNAL ;
    PORT
      LAYER M5 ;
        RECT  12.96 51.756 12.984 51.84 ;
    END
  END cfg_data[223]
  PIN cfg_data[224]
    DIRECTION INPUT ;
    USE SIGNAL ;
    PORT
      LAYER M5 ;
        RECT  13.104 51.756 13.128 51.84 ;
    END
  END cfg_data[224]
  PIN cfg_data[225]
    DIRECTION INPUT ;
    USE SIGNAL ;
    PORT
      LAYER M5 ;
        RECT  13.248 51.756 13.272 51.84 ;
    END
  END cfg_data[225]
  PIN cfg_data[226]
    DIRECTION INPUT ;
    USE SIGNAL ;
    PORT
      LAYER M5 ;
        RECT  13.392 51.756 13.416 51.84 ;
    END
  END cfg_data[226]
  PIN cfg_data[227]
    DIRECTION INPUT ;
    USE SIGNAL ;
    PORT
      LAYER M5 ;
        RECT  13.536 51.756 13.56 51.84 ;
    END
  END cfg_data[227]
  PIN cfg_data[228]
    DIRECTION INPUT ;
    USE SIGNAL ;
    PORT
      LAYER M5 ;
        RECT  13.68 51.756 13.704 51.84 ;
    END
  END cfg_data[228]
  PIN cfg_data[229]
    DIRECTION INPUT ;
    USE SIGNAL ;
    PORT
      LAYER M5 ;
        RECT  13.824 51.756 13.848 51.84 ;
    END
  END cfg_data[229]
  PIN cfg_data[22]
    DIRECTION INPUT ;
    USE SIGNAL ;
    PORT
      LAYER M5 ;
        RECT  26.64 51.756 26.664 51.84 ;
    END
  END cfg_data[22]
  PIN cfg_data[230]
    DIRECTION INPUT ;
    USE SIGNAL ;
    PORT
      LAYER M5 ;
        RECT  13.968 51.756 13.992 51.84 ;
    END
  END cfg_data[230]
  PIN cfg_data[231]
    DIRECTION INPUT ;
    USE SIGNAL ;
    PORT
      LAYER M5 ;
        RECT  14.112 51.756 14.136 51.84 ;
    END
  END cfg_data[231]
  PIN cfg_data[232]
    DIRECTION INPUT ;
    USE SIGNAL ;
    PORT
      LAYER M5 ;
        RECT  14.256 51.756 14.28 51.84 ;
    END
  END cfg_data[232]
  PIN cfg_data[233]
    DIRECTION INPUT ;
    USE SIGNAL ;
    PORT
      LAYER M5 ;
        RECT  14.4 51.756 14.424 51.84 ;
    END
  END cfg_data[233]
  PIN cfg_data[234]
    DIRECTION INPUT ;
    USE SIGNAL ;
    PORT
      LAYER M5 ;
        RECT  14.544 51.756 14.568 51.84 ;
    END
  END cfg_data[234]
  PIN cfg_data[235]
    DIRECTION INPUT ;
    USE SIGNAL ;
    PORT
      LAYER M5 ;
        RECT  14.688 51.756 14.712 51.84 ;
    END
  END cfg_data[235]
  PIN cfg_data[236]
    DIRECTION INPUT ;
    USE SIGNAL ;
    PORT
      LAYER M5 ;
        RECT  14.832 51.756 14.856 51.84 ;
    END
  END cfg_data[236]
  PIN cfg_data[237]
    DIRECTION INPUT ;
    USE SIGNAL ;
    PORT
      LAYER M5 ;
        RECT  14.976 51.756 15 51.84 ;
    END
  END cfg_data[237]
  PIN cfg_data[238]
    DIRECTION INPUT ;
    USE SIGNAL ;
    PORT
      LAYER M5 ;
        RECT  15.12 51.756 15.144 51.84 ;
    END
  END cfg_data[238]
  PIN cfg_data[239]
    DIRECTION INPUT ;
    USE SIGNAL ;
    PORT
      LAYER M5 ;
        RECT  15.264 51.756 15.288 51.84 ;
    END
  END cfg_data[239]
  PIN cfg_data[23]
    DIRECTION INPUT ;
    USE SIGNAL ;
    PORT
      LAYER M5 ;
        RECT  26.784 51.756 26.808 51.84 ;
    END
  END cfg_data[23]
  PIN cfg_data[240]
    DIRECTION INPUT ;
    USE SIGNAL ;
    PORT
      LAYER M5 ;
        RECT  15.408 51.756 15.432 51.84 ;
    END
  END cfg_data[240]
  PIN cfg_data[241]
    DIRECTION INPUT ;
    USE SIGNAL ;
    PORT
      LAYER M5 ;
        RECT  15.552 51.756 15.576 51.84 ;
    END
  END cfg_data[241]
  PIN cfg_data[242]
    DIRECTION INPUT ;
    USE SIGNAL ;
    PORT
      LAYER M5 ;
        RECT  15.696 51.756 15.72 51.84 ;
    END
  END cfg_data[242]
  PIN cfg_data[243]
    DIRECTION INPUT ;
    USE SIGNAL ;
    PORT
      LAYER M5 ;
        RECT  15.84 51.756 15.864 51.84 ;
    END
  END cfg_data[243]
  PIN cfg_data[244]
    DIRECTION INPUT ;
    USE SIGNAL ;
    PORT
      LAYER M5 ;
        RECT  15.984 51.756 16.008 51.84 ;
    END
  END cfg_data[244]
  PIN cfg_data[245]
    DIRECTION INPUT ;
    USE SIGNAL ;
    PORT
      LAYER M5 ;
        RECT  16.128 51.756 16.152 51.84 ;
    END
  END cfg_data[245]
  PIN cfg_data[246]
    DIRECTION INPUT ;
    USE SIGNAL ;
    PORT
      LAYER M5 ;
        RECT  16.272 51.756 16.296 51.84 ;
    END
  END cfg_data[246]
  PIN cfg_data[247]
    DIRECTION INPUT ;
    USE SIGNAL ;
    PORT
      LAYER M5 ;
        RECT  16.416 51.756 16.44 51.84 ;
    END
  END cfg_data[247]
  PIN cfg_data[248]
    DIRECTION INPUT ;
    USE SIGNAL ;
    PORT
      LAYER M5 ;
        RECT  16.56 51.756 16.584 51.84 ;
    END
  END cfg_data[248]
  PIN cfg_data[249]
    DIRECTION INPUT ;
    USE SIGNAL ;
    PORT
      LAYER M5 ;
        RECT  16.704 51.756 16.728 51.84 ;
    END
  END cfg_data[249]
  PIN cfg_data[24]
    DIRECTION INPUT ;
    USE SIGNAL ;
    PORT
      LAYER M5 ;
        RECT  26.928 51.756 26.952 51.84 ;
    END
  END cfg_data[24]
  PIN cfg_data[250]
    DIRECTION INPUT ;
    USE SIGNAL ;
    PORT
      LAYER M5 ;
        RECT  16.848 51.756 16.872 51.84 ;
    END
  END cfg_data[250]
  PIN cfg_data[251]
    DIRECTION INPUT ;
    USE SIGNAL ;
    PORT
      LAYER M5 ;
        RECT  16.992 51.756 17.016 51.84 ;
    END
  END cfg_data[251]
  PIN cfg_data[252]
    DIRECTION INPUT ;
    USE SIGNAL ;
    PORT
      LAYER M5 ;
        RECT  17.136 51.756 17.16 51.84 ;
    END
  END cfg_data[252]
  PIN cfg_data[253]
    DIRECTION INPUT ;
    USE SIGNAL ;
    PORT
      LAYER M5 ;
        RECT  17.28 51.756 17.304 51.84 ;
    END
  END cfg_data[253]
  PIN cfg_data[254]
    DIRECTION INPUT ;
    USE SIGNAL ;
    PORT
      LAYER M5 ;
        RECT  17.424 51.756 17.448 51.84 ;
    END
  END cfg_data[254]
  PIN cfg_data[255]
    DIRECTION INPUT ;
    USE SIGNAL ;
    PORT
      LAYER M5 ;
        RECT  17.568 51.756 17.592 51.84 ;
    END
  END cfg_data[255]
  PIN cfg_data[25]
    DIRECTION INPUT ;
    USE SIGNAL ;
    PORT
      LAYER M5 ;
        RECT  27.072 51.756 27.096 51.84 ;
    END
  END cfg_data[25]
  PIN cfg_data[26]
    DIRECTION INPUT ;
    USE SIGNAL ;
    PORT
      LAYER M5 ;
        RECT  27.216 51.756 27.24 51.84 ;
    END
  END cfg_data[26]
  PIN cfg_data[27]
    DIRECTION INPUT ;
    USE SIGNAL ;
    PORT
      LAYER M5 ;
        RECT  27.36 51.756 27.384 51.84 ;
    END
  END cfg_data[27]
  PIN cfg_data[28]
    DIRECTION INPUT ;
    USE SIGNAL ;
    PORT
      LAYER M5 ;
        RECT  27.504 51.756 27.528 51.84 ;
    END
  END cfg_data[28]
  PIN cfg_data[29]
    DIRECTION INPUT ;
    USE SIGNAL ;
    PORT
      LAYER M5 ;
        RECT  27.648 51.756 27.672 51.84 ;
    END
  END cfg_data[29]
  PIN cfg_data[2]
    DIRECTION INPUT ;
    USE SIGNAL ;
    PORT
      LAYER M5 ;
        RECT  23.76 51.756 23.784 51.84 ;
    END
  END cfg_data[2]
  PIN cfg_data[30]
    DIRECTION INPUT ;
    USE SIGNAL ;
    PORT
      LAYER M5 ;
        RECT  27.792 51.756 27.816 51.84 ;
    END
  END cfg_data[30]
  PIN cfg_data[31]
    DIRECTION INPUT ;
    USE SIGNAL ;
    PORT
      LAYER M5 ;
        RECT  27.936 51.756 27.96 51.84 ;
    END
  END cfg_data[31]
  PIN cfg_data[32]
    DIRECTION INPUT ;
    USE SIGNAL ;
    PORT
      LAYER M5 ;
        RECT  41.904 51.756 41.928 51.84 ;
    END
  END cfg_data[32]
  PIN cfg_data[33]
    DIRECTION INPUT ;
    USE SIGNAL ;
    PORT
      LAYER M5 ;
        RECT  42.048 51.756 42.072 51.84 ;
    END
  END cfg_data[33]
  PIN cfg_data[34]
    DIRECTION INPUT ;
    USE SIGNAL ;
    PORT
      LAYER M5 ;
        RECT  42.192 51.756 42.216 51.84 ;
    END
  END cfg_data[34]
  PIN cfg_data[35]
    DIRECTION INPUT ;
    USE SIGNAL ;
    PORT
      LAYER M5 ;
        RECT  42.336 51.756 42.36 51.84 ;
    END
  END cfg_data[35]
  PIN cfg_data[36]
    DIRECTION INPUT ;
    USE SIGNAL ;
    PORT
      LAYER M5 ;
        RECT  42.48 51.756 42.504 51.84 ;
    END
  END cfg_data[36]
  PIN cfg_data[37]
    DIRECTION INPUT ;
    USE SIGNAL ;
    PORT
      LAYER M5 ;
        RECT  42.624 51.756 42.648 51.84 ;
    END
  END cfg_data[37]
  PIN cfg_data[38]
    DIRECTION INPUT ;
    USE SIGNAL ;
    PORT
      LAYER M5 ;
        RECT  42.768 51.756 42.792 51.84 ;
    END
  END cfg_data[38]
  PIN cfg_data[39]
    DIRECTION INPUT ;
    USE SIGNAL ;
    PORT
      LAYER M5 ;
        RECT  42.912 51.756 42.936 51.84 ;
    END
  END cfg_data[39]
  PIN cfg_data[3]
    DIRECTION INPUT ;
    USE SIGNAL ;
    PORT
      LAYER M5 ;
        RECT  23.904 51.756 23.928 51.84 ;
    END
  END cfg_data[3]
  PIN cfg_data[40]
    DIRECTION INPUT ;
    USE SIGNAL ;
    PORT
      LAYER M5 ;
        RECT  43.056 51.756 43.08 51.84 ;
    END
  END cfg_data[40]
  PIN cfg_data[41]
    DIRECTION INPUT ;
    USE SIGNAL ;
    PORT
      LAYER M5 ;
        RECT  43.2 51.756 43.224 51.84 ;
    END
  END cfg_data[41]
  PIN cfg_data[42]
    DIRECTION INPUT ;
    USE SIGNAL ;
    PORT
      LAYER M5 ;
        RECT  43.344 51.756 43.368 51.84 ;
    END
  END cfg_data[42]
  PIN cfg_data[43]
    DIRECTION INPUT ;
    USE SIGNAL ;
    PORT
      LAYER M5 ;
        RECT  43.488 51.756 43.512 51.84 ;
    END
  END cfg_data[43]
  PIN cfg_data[44]
    DIRECTION INPUT ;
    USE SIGNAL ;
    PORT
      LAYER M5 ;
        RECT  43.632 51.756 43.656 51.84 ;
    END
  END cfg_data[44]
  PIN cfg_data[45]
    DIRECTION INPUT ;
    USE SIGNAL ;
    PORT
      LAYER M5 ;
        RECT  43.776 51.756 43.8 51.84 ;
    END
  END cfg_data[45]
  PIN cfg_data[46]
    DIRECTION INPUT ;
    USE SIGNAL ;
    PORT
      LAYER M5 ;
        RECT  43.92 51.756 43.944 51.84 ;
    END
  END cfg_data[46]
  PIN cfg_data[47]
    DIRECTION INPUT ;
    USE SIGNAL ;
    PORT
      LAYER M5 ;
        RECT  44.064 51.756 44.088 51.84 ;
    END
  END cfg_data[47]
  PIN cfg_data[48]
    DIRECTION INPUT ;
    USE SIGNAL ;
    PORT
      LAYER M5 ;
        RECT  44.208 51.756 44.232 51.84 ;
    END
  END cfg_data[48]
  PIN cfg_data[49]
    DIRECTION INPUT ;
    USE SIGNAL ;
    PORT
      LAYER M5 ;
        RECT  44.352 51.756 44.376 51.84 ;
    END
  END cfg_data[49]
  PIN cfg_data[4]
    DIRECTION INPUT ;
    USE SIGNAL ;
    PORT
      LAYER M5 ;
        RECT  24.048 51.756 24.072 51.84 ;
    END
  END cfg_data[4]
  PIN cfg_data[50]
    DIRECTION INPUT ;
    USE SIGNAL ;
    PORT
      LAYER M5 ;
        RECT  44.496 51.756 44.52 51.84 ;
    END
  END cfg_data[50]
  PIN cfg_data[51]
    DIRECTION INPUT ;
    USE SIGNAL ;
    PORT
      LAYER M5 ;
        RECT  44.64 51.756 44.664 51.84 ;
    END
  END cfg_data[51]
  PIN cfg_data[52]
    DIRECTION INPUT ;
    USE SIGNAL ;
    PORT
      LAYER M5 ;
        RECT  44.784 51.756 44.808 51.84 ;
    END
  END cfg_data[52]
  PIN cfg_data[53]
    DIRECTION INPUT ;
    USE SIGNAL ;
    PORT
      LAYER M5 ;
        RECT  44.928 51.756 44.952 51.84 ;
    END
  END cfg_data[53]
  PIN cfg_data[54]
    DIRECTION INPUT ;
    USE SIGNAL ;
    PORT
      LAYER M5 ;
        RECT  45.072 51.756 45.096 51.84 ;
    END
  END cfg_data[54]
  PIN cfg_data[55]
    DIRECTION INPUT ;
    USE SIGNAL ;
    PORT
      LAYER M5 ;
        RECT  45.216 51.756 45.24 51.84 ;
    END
  END cfg_data[55]
  PIN cfg_data[56]
    DIRECTION INPUT ;
    USE SIGNAL ;
    PORT
      LAYER M5 ;
        RECT  45.36 51.756 45.384 51.84 ;
    END
  END cfg_data[56]
  PIN cfg_data[57]
    DIRECTION INPUT ;
    USE SIGNAL ;
    PORT
      LAYER M5 ;
        RECT  45.504 51.756 45.528 51.84 ;
    END
  END cfg_data[57]
  PIN cfg_data[58]
    DIRECTION INPUT ;
    USE SIGNAL ;
    PORT
      LAYER M5 ;
        RECT  45.648 51.756 45.672 51.84 ;
    END
  END cfg_data[58]
  PIN cfg_data[59]
    DIRECTION INPUT ;
    USE SIGNAL ;
    PORT
      LAYER M5 ;
        RECT  45.792 51.756 45.816 51.84 ;
    END
  END cfg_data[59]
  PIN cfg_data[5]
    DIRECTION INPUT ;
    USE SIGNAL ;
    PORT
      LAYER M5 ;
        RECT  24.192 51.756 24.216 51.84 ;
    END
  END cfg_data[5]
  PIN cfg_data[60]
    DIRECTION INPUT ;
    USE SIGNAL ;
    PORT
      LAYER M5 ;
        RECT  45.936 51.756 45.96 51.84 ;
    END
  END cfg_data[60]
  PIN cfg_data[61]
    DIRECTION INPUT ;
    USE SIGNAL ;
    PORT
      LAYER M5 ;
        RECT  46.08 51.756 46.104 51.84 ;
    END
  END cfg_data[61]
  PIN cfg_data[62]
    DIRECTION INPUT ;
    USE SIGNAL ;
    PORT
      LAYER M5 ;
        RECT  46.224 51.756 46.248 51.84 ;
    END
  END cfg_data[62]
  PIN cfg_data[63]
    DIRECTION INPUT ;
    USE SIGNAL ;
    PORT
      LAYER M5 ;
        RECT  46.368 51.756 46.392 51.84 ;
    END
  END cfg_data[63]
  PIN cfg_data[64]
    DIRECTION INPUT ;
    USE SIGNAL ;
    PORT
      LAYER M5 ;
        RECT  28.08 51.756 28.104 51.84 ;
    END
  END cfg_data[64]
  PIN cfg_data[65]
    DIRECTION INPUT ;
    USE SIGNAL ;
    PORT
      LAYER M5 ;
        RECT  28.224 51.756 28.248 51.84 ;
    END
  END cfg_data[65]
  PIN cfg_data[66]
    DIRECTION INPUT ;
    USE SIGNAL ;
    PORT
      LAYER M5 ;
        RECT  28.368 51.756 28.392 51.84 ;
    END
  END cfg_data[66]
  PIN cfg_data[67]
    DIRECTION INPUT ;
    USE SIGNAL ;
    PORT
      LAYER M5 ;
        RECT  28.512 51.756 28.536 51.84 ;
    END
  END cfg_data[67]
  PIN cfg_data[68]
    DIRECTION INPUT ;
    USE SIGNAL ;
    PORT
      LAYER M5 ;
        RECT  28.656 51.756 28.68 51.84 ;
    END
  END cfg_data[68]
  PIN cfg_data[69]
    DIRECTION INPUT ;
    USE SIGNAL ;
    PORT
      LAYER M5 ;
        RECT  28.8 51.756 28.824 51.84 ;
    END
  END cfg_data[69]
  PIN cfg_data[6]
    DIRECTION INPUT ;
    USE SIGNAL ;
    PORT
      LAYER M5 ;
        RECT  24.336 51.756 24.36 51.84 ;
    END
  END cfg_data[6]
  PIN cfg_data[70]
    DIRECTION INPUT ;
    USE SIGNAL ;
    PORT
      LAYER M5 ;
        RECT  28.944 51.756 28.968 51.84 ;
    END
  END cfg_data[70]
  PIN cfg_data[71]
    DIRECTION INPUT ;
    USE SIGNAL ;
    PORT
      LAYER M5 ;
        RECT  29.088 51.756 29.112 51.84 ;
    END
  END cfg_data[71]
  PIN cfg_data[72]
    DIRECTION INPUT ;
    USE SIGNAL ;
    PORT
      LAYER M5 ;
        RECT  29.232 51.756 29.256 51.84 ;
    END
  END cfg_data[72]
  PIN cfg_data[73]
    DIRECTION INPUT ;
    USE SIGNAL ;
    PORT
      LAYER M5 ;
        RECT  29.376 51.756 29.4 51.84 ;
    END
  END cfg_data[73]
  PIN cfg_data[74]
    DIRECTION INPUT ;
    USE SIGNAL ;
    PORT
      LAYER M5 ;
        RECT  29.52 51.756 29.544 51.84 ;
    END
  END cfg_data[74]
  PIN cfg_data[75]
    DIRECTION INPUT ;
    USE SIGNAL ;
    PORT
      LAYER M5 ;
        RECT  29.664 51.756 29.688 51.84 ;
    END
  END cfg_data[75]
  PIN cfg_data[76]
    DIRECTION INPUT ;
    USE SIGNAL ;
    PORT
      LAYER M5 ;
        RECT  29.808 51.756 29.832 51.84 ;
    END
  END cfg_data[76]
  PIN cfg_data[77]
    DIRECTION INPUT ;
    USE SIGNAL ;
    PORT
      LAYER M5 ;
        RECT  29.952 51.756 29.976 51.84 ;
    END
  END cfg_data[77]
  PIN cfg_data[78]
    DIRECTION INPUT ;
    USE SIGNAL ;
    PORT
      LAYER M5 ;
        RECT  30.096 51.756 30.12 51.84 ;
    END
  END cfg_data[78]
  PIN cfg_data[79]
    DIRECTION INPUT ;
    USE SIGNAL ;
    PORT
      LAYER M5 ;
        RECT  30.24 51.756 30.264 51.84 ;
    END
  END cfg_data[79]
  PIN cfg_data[7]
    DIRECTION INPUT ;
    USE SIGNAL ;
    PORT
      LAYER M5 ;
        RECT  24.48 51.756 24.504 51.84 ;
    END
  END cfg_data[7]
  PIN cfg_data[80]
    DIRECTION INPUT ;
    USE SIGNAL ;
    PORT
      LAYER M5 ;
        RECT  30.384 51.756 30.408 51.84 ;
    END
  END cfg_data[80]
  PIN cfg_data[81]
    DIRECTION INPUT ;
    USE SIGNAL ;
    PORT
      LAYER M5 ;
        RECT  30.528 51.756 30.552 51.84 ;
    END
  END cfg_data[81]
  PIN cfg_data[82]
    DIRECTION INPUT ;
    USE SIGNAL ;
    PORT
      LAYER M5 ;
        RECT  30.672 51.756 30.696 51.84 ;
    END
  END cfg_data[82]
  PIN cfg_data[83]
    DIRECTION INPUT ;
    USE SIGNAL ;
    PORT
      LAYER M5 ;
        RECT  30.816 51.756 30.84 51.84 ;
    END
  END cfg_data[83]
  PIN cfg_data[84]
    DIRECTION INPUT ;
    USE SIGNAL ;
    PORT
      LAYER M5 ;
        RECT  30.96 51.756 30.984 51.84 ;
    END
  END cfg_data[84]
  PIN cfg_data[85]
    DIRECTION INPUT ;
    USE SIGNAL ;
    PORT
      LAYER M5 ;
        RECT  31.104 51.756 31.128 51.84 ;
    END
  END cfg_data[85]
  PIN cfg_data[86]
    DIRECTION INPUT ;
    USE SIGNAL ;
    PORT
      LAYER M5 ;
        RECT  31.248 51.756 31.272 51.84 ;
    END
  END cfg_data[86]
  PIN cfg_data[87]
    DIRECTION INPUT ;
    USE SIGNAL ;
    PORT
      LAYER M5 ;
        RECT  31.392 51.756 31.416 51.84 ;
    END
  END cfg_data[87]
  PIN cfg_data[88]
    DIRECTION INPUT ;
    USE SIGNAL ;
    PORT
      LAYER M5 ;
        RECT  31.536 51.756 31.56 51.84 ;
    END
  END cfg_data[88]
  PIN cfg_data[89]
    DIRECTION INPUT ;
    USE SIGNAL ;
    PORT
      LAYER M5 ;
        RECT  31.68 51.756 31.704 51.84 ;
    END
  END cfg_data[89]
  PIN cfg_data[8]
    DIRECTION INPUT ;
    USE SIGNAL ;
    PORT
      LAYER M5 ;
        RECT  24.624 51.756 24.648 51.84 ;
    END
  END cfg_data[8]
  PIN cfg_data[90]
    DIRECTION INPUT ;
    USE SIGNAL ;
    PORT
      LAYER M5 ;
        RECT  31.824 51.756 31.848 51.84 ;
    END
  END cfg_data[90]
  PIN cfg_data[91]
    DIRECTION INPUT ;
    USE SIGNAL ;
    PORT
      LAYER M5 ;
        RECT  31.968 51.756 31.992 51.84 ;
    END
  END cfg_data[91]
  PIN cfg_data[92]
    DIRECTION INPUT ;
    USE SIGNAL ;
    PORT
      LAYER M5 ;
        RECT  32.112 51.756 32.136 51.84 ;
    END
  END cfg_data[92]
  PIN cfg_data[93]
    DIRECTION INPUT ;
    USE SIGNAL ;
    PORT
      LAYER M5 ;
        RECT  32.256 51.756 32.28 51.84 ;
    END
  END cfg_data[93]
  PIN cfg_data[94]
    DIRECTION INPUT ;
    USE SIGNAL ;
    PORT
      LAYER M5 ;
        RECT  32.4 51.756 32.424 51.84 ;
    END
  END cfg_data[94]
  PIN cfg_data[95]
    DIRECTION INPUT ;
    USE SIGNAL ;
    PORT
      LAYER M5 ;
        RECT  32.544 51.756 32.568 51.84 ;
    END
  END cfg_data[95]
  PIN cfg_data[96]
    DIRECTION INPUT ;
    USE SIGNAL ;
    PORT
      LAYER M5 ;
        RECT  37.296 51.756 37.32 51.84 ;
    END
  END cfg_data[96]
  PIN cfg_data[97]
    DIRECTION INPUT ;
    USE SIGNAL ;
    PORT
      LAYER M5 ;
        RECT  37.44 51.756 37.464 51.84 ;
    END
  END cfg_data[97]
  PIN cfg_data[98]
    DIRECTION INPUT ;
    USE SIGNAL ;
    PORT
      LAYER M5 ;
        RECT  37.584 51.756 37.608 51.84 ;
    END
  END cfg_data[98]
  PIN cfg_data[99]
    DIRECTION INPUT ;
    USE SIGNAL ;
    PORT
      LAYER M5 ;
        RECT  37.728 51.756 37.752 51.84 ;
    END
  END cfg_data[99]
  PIN cfg_data[9]
    DIRECTION INPUT ;
    USE SIGNAL ;
    PORT
      LAYER M5 ;
        RECT  24.768 51.756 24.792 51.84 ;
    END
  END cfg_data[9]
  PIN cfg_target[0]
    DIRECTION INPUT ;
    USE SIGNAL ;
    PORT
      LAYER M4 ;
        RECT  0 8.784 0.084 8.808 ;
    END
  END cfg_target[0]
  PIN cfg_target[1]
    DIRECTION INPUT ;
    USE SIGNAL ;
    PORT
      LAYER M4 ;
        RECT  0 8.928 0.084 8.952 ;
    END
  END cfg_target[1]
  PIN cfg_target[2]
    DIRECTION INPUT ;
    USE SIGNAL ;
    PORT
      LAYER M4 ;
        RECT  0 9.072 0.084 9.096 ;
    END
  END cfg_target[2]
  PIN cfg_target[3]
    DIRECTION INPUT ;
    USE SIGNAL ;
    PORT
      LAYER M4 ;
        RECT  0 9.216 0.084 9.24 ;
    END
  END cfg_target[3]
  PIN cfg_target[4]
    DIRECTION INPUT ;
    USE SIGNAL ;
    PORT
      LAYER M4 ;
        RECT  0 9.36 0.084 9.384 ;
    END
  END cfg_target[4]
  PIN cfg_target[5]
    DIRECTION INPUT ;
    USE SIGNAL ;
    PORT
      LAYER M4 ;
        RECT  0 9.504 0.084 9.528 ;
    END
  END cfg_target[5]
  PIN cfg_target[6]
    DIRECTION INPUT ;
    USE SIGNAL ;
    PORT
      LAYER M4 ;
        RECT  0 9.648 0.084 9.672 ;
    END
  END cfg_target[6]
  PIN cfg_target[7]
    DIRECTION INPUT ;
    USE SIGNAL ;
    PORT
      LAYER M4 ;
        RECT  0 9.792 0.084 9.816 ;
    END
  END cfg_target[7]
  PIN cfg_v
    DIRECTION INPUT ;
    USE SIGNAL ;
    PORT
      LAYER M4 ;
        RECT  0 9.936 0.084 9.96 ;
    END
  END cfg_v
  PIN clk
    DIRECTION INPUT ;
    USE SIGNAL ;
    PORT
      LAYER M4 ;
        RECT  0 10.08 0.084 10.104 ;
    END
  END clk
  PIN configured
    DIRECTION OUTPUT ;
    USE SIGNAL ;
    PORT
      LAYER M4 ;
        RECT  0 10.224 0.084 10.248 ;
    END
  END configured
  PIN desc_base[0]
    DIRECTION INPUT ;
    USE SIGNAL ;
    PORT
      LAYER M4 ;
        RECT  0 10.368 0.084 10.392 ;
    END
  END desc_base[0]
  PIN desc_base[10]
    DIRECTION INPUT ;
    USE SIGNAL ;
    PORT
      LAYER M4 ;
        RECT  0 11.808 0.084 11.832 ;
    END
  END desc_base[10]
  PIN desc_base[11]
    DIRECTION INPUT ;
    USE SIGNAL ;
    PORT
      LAYER M4 ;
        RECT  0 11.952 0.084 11.976 ;
    END
  END desc_base[11]
  PIN desc_base[1]
    DIRECTION INPUT ;
    USE SIGNAL ;
    PORT
      LAYER M4 ;
        RECT  0 10.512 0.084 10.536 ;
    END
  END desc_base[1]
  PIN desc_base[2]
    DIRECTION INPUT ;
    USE SIGNAL ;
    PORT
      LAYER M4 ;
        RECT  0 10.656 0.084 10.68 ;
    END
  END desc_base[2]
  PIN desc_base[3]
    DIRECTION INPUT ;
    USE SIGNAL ;
    PORT
      LAYER M4 ;
        RECT  0 10.8 0.084 10.824 ;
    END
  END desc_base[3]
  PIN desc_base[4]
    DIRECTION INPUT ;
    USE SIGNAL ;
    PORT
      LAYER M4 ;
        RECT  0 10.944 0.084 10.968 ;
    END
  END desc_base[4]
  PIN desc_base[5]
    DIRECTION INPUT ;
    USE SIGNAL ;
    PORT
      LAYER M4 ;
        RECT  0 11.088 0.084 11.112 ;
    END
  END desc_base[5]
  PIN desc_base[6]
    DIRECTION INPUT ;
    USE SIGNAL ;
    PORT
      LAYER M4 ;
        RECT  0 11.232 0.084 11.256 ;
    END
  END desc_base[6]
  PIN desc_base[7]
    DIRECTION INPUT ;
    USE SIGNAL ;
    PORT
      LAYER M4 ;
        RECT  0 11.376 0.084 11.4 ;
    END
  END desc_base[7]
  PIN desc_base[8]
    DIRECTION INPUT ;
    USE SIGNAL ;
    PORT
      LAYER M4 ;
        RECT  0 11.52 0.084 11.544 ;
    END
  END desc_base[8]
  PIN desc_base[9]
    DIRECTION INPUT ;
    USE SIGNAL ;
    PORT
      LAYER M4 ;
        RECT  0 11.664 0.084 11.688 ;
    END
  END desc_base[9]
  PIN desc_limit[0]
    DIRECTION INPUT ;
    USE SIGNAL ;
    PORT
      LAYER M4 ;
        RECT  0 12.096 0.084 12.12 ;
    END
  END desc_limit[0]
  PIN desc_limit[10]
    DIRECTION INPUT ;
    USE SIGNAL ;
    PORT
      LAYER M4 ;
        RECT  0 13.536 0.084 13.56 ;
    END
  END desc_limit[10]
  PIN desc_limit[11]
    DIRECTION INPUT ;
    USE SIGNAL ;
    PORT
      LAYER M4 ;
        RECT  0 13.68 0.084 13.704 ;
    END
  END desc_limit[11]
  PIN desc_limit[12]
    DIRECTION INPUT ;
    USE SIGNAL ;
    PORT
      LAYER M4 ;
        RECT  0 13.824 0.084 13.848 ;
    END
  END desc_limit[12]
  PIN desc_limit[1]
    DIRECTION INPUT ;
    USE SIGNAL ;
    PORT
      LAYER M4 ;
        RECT  0 12.24 0.084 12.264 ;
    END
  END desc_limit[1]
  PIN desc_limit[2]
    DIRECTION INPUT ;
    USE SIGNAL ;
    PORT
      LAYER M4 ;
        RECT  0 12.384 0.084 12.408 ;
    END
  END desc_limit[2]
  PIN desc_limit[3]
    DIRECTION INPUT ;
    USE SIGNAL ;
    PORT
      LAYER M4 ;
        RECT  0 12.528 0.084 12.552 ;
    END
  END desc_limit[3]
  PIN desc_limit[4]
    DIRECTION INPUT ;
    USE SIGNAL ;
    PORT
      LAYER M4 ;
        RECT  0 12.672 0.084 12.696 ;
    END
  END desc_limit[4]
  PIN desc_limit[5]
    DIRECTION INPUT ;
    USE SIGNAL ;
    PORT
      LAYER M4 ;
        RECT  0 12.816 0.084 12.84 ;
    END
  END desc_limit[5]
  PIN desc_limit[6]
    DIRECTION INPUT ;
    USE SIGNAL ;
    PORT
      LAYER M4 ;
        RECT  0 12.96 0.084 12.984 ;
    END
  END desc_limit[6]
  PIN desc_limit[7]
    DIRECTION INPUT ;
    USE SIGNAL ;
    PORT
      LAYER M4 ;
        RECT  0 13.104 0.084 13.128 ;
    END
  END desc_limit[7]
  PIN desc_limit[8]
    DIRECTION INPUT ;
    USE SIGNAL ;
    PORT
      LAYER M4 ;
        RECT  0 13.248 0.084 13.272 ;
    END
  END desc_limit[8]
  PIN desc_limit[9]
    DIRECTION INPUT ;
    USE SIGNAL ;
    PORT
      LAYER M4 ;
        RECT  0 13.392 0.084 13.416 ;
    END
  END desc_limit[9]
  PIN desc_loops[0]
    DIRECTION INPUT ;
    USE SIGNAL ;
    PORT
      LAYER M4 ;
        RECT  0 13.968 0.084 13.992 ;
    END
  END desc_loops[0]
  PIN desc_loops[10]
    DIRECTION INPUT ;
    USE SIGNAL ;
    PORT
      LAYER M4 ;
        RECT  0 15.408 0.084 15.432 ;
    END
  END desc_loops[10]
  PIN desc_loops[11]
    DIRECTION INPUT ;
    USE SIGNAL ;
    PORT
      LAYER M4 ;
        RECT  0 15.552 0.084 15.576 ;
    END
  END desc_loops[11]
  PIN desc_loops[12]
    DIRECTION INPUT ;
    USE SIGNAL ;
    PORT
      LAYER M4 ;
        RECT  0 15.696 0.084 15.72 ;
    END
  END desc_loops[12]
  PIN desc_loops[13]
    DIRECTION INPUT ;
    USE SIGNAL ;
    PORT
      LAYER M4 ;
        RECT  0 15.84 0.084 15.864 ;
    END
  END desc_loops[13]
  PIN desc_loops[14]
    DIRECTION INPUT ;
    USE SIGNAL ;
    PORT
      LAYER M4 ;
        RECT  0 15.984 0.084 16.008 ;
    END
  END desc_loops[14]
  PIN desc_loops[15]
    DIRECTION INPUT ;
    USE SIGNAL ;
    PORT
      LAYER M4 ;
        RECT  0 16.128 0.084 16.152 ;
    END
  END desc_loops[15]
  PIN desc_loops[1]
    DIRECTION INPUT ;
    USE SIGNAL ;
    PORT
      LAYER M4 ;
        RECT  0 14.112 0.084 14.136 ;
    END
  END desc_loops[1]
  PIN desc_loops[2]
    DIRECTION INPUT ;
    USE SIGNAL ;
    PORT
      LAYER M4 ;
        RECT  0 14.256 0.084 14.28 ;
    END
  END desc_loops[2]
  PIN desc_loops[3]
    DIRECTION INPUT ;
    USE SIGNAL ;
    PORT
      LAYER M4 ;
        RECT  0 14.4 0.084 14.424 ;
    END
  END desc_loops[3]
  PIN desc_loops[4]
    DIRECTION INPUT ;
    USE SIGNAL ;
    PORT
      LAYER M4 ;
        RECT  0 14.544 0.084 14.568 ;
    END
  END desc_loops[4]
  PIN desc_loops[5]
    DIRECTION INPUT ;
    USE SIGNAL ;
    PORT
      LAYER M4 ;
        RECT  0 14.688 0.084 14.712 ;
    END
  END desc_loops[5]
  PIN desc_loops[6]
    DIRECTION INPUT ;
    USE SIGNAL ;
    PORT
      LAYER M4 ;
        RECT  0 14.832 0.084 14.856 ;
    END
  END desc_loops[6]
  PIN desc_loops[7]
    DIRECTION INPUT ;
    USE SIGNAL ;
    PORT
      LAYER M4 ;
        RECT  0 14.976 0.084 15 ;
    END
  END desc_loops[7]
  PIN desc_loops[8]
    DIRECTION INPUT ;
    USE SIGNAL ;
    PORT
      LAYER M4 ;
        RECT  0 15.12 0.084 15.144 ;
    END
  END desc_loops[8]
  PIN desc_loops[9]
    DIRECTION INPUT ;
    USE SIGNAL ;
    PORT
      LAYER M4 ;
        RECT  0 15.264 0.084 15.288 ;
    END
  END desc_loops[9]
  PIN desc_v
    DIRECTION INPUT ;
    USE SIGNAL ;
    PORT
      LAYER M4 ;
        RECT  0 16.272 0.084 16.296 ;
    END
  END desc_v
  PIN fault
    DIRECTION OUTPUT ;
    USE SIGNAL ;
    PORT
      LAYER M4 ;
        RECT  0 16.416 0.084 16.44 ;
    END
  END fault
  PIN launch_v
    DIRECTION INPUT ;
    USE SIGNAL ;
    PORT
      LAYER M4 ;
        RECT  0 16.56 0.084 16.584 ;
    END
  END launch_v
  PIN rst_n
    DIRECTION INPUT ;
    USE SIGNAL ;
    PORT
      LAYER M4 ;
        RECT  0 16.704 0.084 16.728 ;
    END
  END rst_n
  PIN run_arg[0]
    DIRECTION OUTPUT ;
    USE SIGNAL ;
    PORT
      LAYER M4 ;
        RECT  0 16.848 0.084 16.872 ;
    END
  END run_arg[0]
  PIN run_arg[1]
    DIRECTION OUTPUT ;
    USE SIGNAL ;
    PORT
      LAYER M4 ;
        RECT  0 16.992 0.084 17.016 ;
    END
  END run_arg[1]
  PIN run_arg[2]
    DIRECTION OUTPUT ;
    USE SIGNAL ;
    PORT
      LAYER M4 ;
        RECT  0 17.136 0.084 17.16 ;
    END
  END run_arg[2]
  PIN run_arg[3]
    DIRECTION OUTPUT ;
    USE SIGNAL ;
    PORT
      LAYER M4 ;
        RECT  0 17.28 0.084 17.304 ;
    END
  END run_arg[3]
  PIN run_arg[4]
    DIRECTION OUTPUT ;
    USE SIGNAL ;
    PORT
      LAYER M4 ;
        RECT  0 17.424 0.084 17.448 ;
    END
  END run_arg[4]
  PIN run_arg[5]
    DIRECTION OUTPUT ;
    USE SIGNAL ;
    PORT
      LAYER M4 ;
        RECT  0 17.568 0.084 17.592 ;
    END
  END run_arg[5]
  PIN run_arg[6]
    DIRECTION OUTPUT ;
    USE SIGNAL ;
    PORT
      LAYER M4 ;
        RECT  0 4.032 0.084 4.056 ;
    END
  END run_arg[6]
  PIN run_arg[7]
    DIRECTION OUTPUT ;
    USE SIGNAL ;
    PORT
      LAYER M4 ;
        RECT  0 4.176 0.084 4.2 ;
    END
  END run_arg[7]
  PIN run_base[0]
    DIRECTION OUTPUT ;
    USE SIGNAL ;
    PORT
      LAYER M4 ;
        RECT  0 4.32 0.084 4.344 ;
    END
  END run_base[0]
  PIN run_base[1]
    DIRECTION OUTPUT ;
    USE SIGNAL ;
    PORT
      LAYER M4 ;
        RECT  0 4.464 0.084 4.488 ;
    END
  END run_base[1]
  PIN run_base[2]
    DIRECTION OUTPUT ;
    USE SIGNAL ;
    PORT
      LAYER M4 ;
        RECT  0 4.608 0.084 4.632 ;
    END
  END run_base[2]
  PIN run_base[3]
    DIRECTION OUTPUT ;
    USE SIGNAL ;
    PORT
      LAYER M4 ;
        RECT  0 4.752 0.084 4.776 ;
    END
  END run_base[3]
  PIN run_base[4]
    DIRECTION OUTPUT ;
    USE SIGNAL ;
    PORT
      LAYER M4 ;
        RECT  0 4.896 0.084 4.92 ;
    END
  END run_base[4]
  PIN run_base[5]
    DIRECTION OUTPUT ;
    USE SIGNAL ;
    PORT
      LAYER M4 ;
        RECT  0 5.04 0.084 5.064 ;
    END
  END run_base[5]
  PIN run_base[6]
    DIRECTION OUTPUT ;
    USE SIGNAL ;
    PORT
      LAYER M4 ;
        RECT  0 5.184 0.084 5.208 ;
    END
  END run_base[6]
  PIN run_base[7]
    DIRECTION OUTPUT ;
    USE SIGNAL ;
    PORT
      LAYER M4 ;
        RECT  0 5.328 0.084 5.352 ;
    END
  END run_base[7]
  PIN run_count[0]
    DIRECTION OUTPUT ;
    USE SIGNAL ;
    PORT
      LAYER M4 ;
        RECT  0 5.472 0.084 5.496 ;
    END
  END run_count[0]
  PIN run_count[1]
    DIRECTION OUTPUT ;
    USE SIGNAL ;
    PORT
      LAYER M4 ;
        RECT  0 5.616 0.084 5.64 ;
    END
  END run_count[1]
  PIN run_count[2]
    DIRECTION OUTPUT ;
    USE SIGNAL ;
    PORT
      LAYER M4 ;
        RECT  0 5.76 0.084 5.784 ;
    END
  END run_count[2]
  PIN run_count[3]
    DIRECTION OUTPUT ;
    USE SIGNAL ;
    PORT
      LAYER M4 ;
        RECT  0 5.904 0.084 5.928 ;
    END
  END run_count[3]
  PIN run_count[4]
    DIRECTION OUTPUT ;
    USE SIGNAL ;
    PORT
      LAYER M4 ;
        RECT  0 6.048 0.084 6.072 ;
    END
  END run_count[4]
  PIN run_count[5]
    DIRECTION OUTPUT ;
    USE SIGNAL ;
    PORT
      LAYER M4 ;
        RECT  0 6.192 0.084 6.216 ;
    END
  END run_count[5]
  PIN run_count[6]
    DIRECTION OUTPUT ;
    USE SIGNAL ;
    PORT
      LAYER M4 ;
        RECT  0 6.336 0.084 6.36 ;
    END
  END run_count[6]
  PIN run_count[7]
    DIRECTION OUTPUT ;
    USE SIGNAL ;
    PORT
      LAYER M4 ;
        RECT  0 6.48 0.084 6.504 ;
    END
  END run_count[7]
  PIN run_count[8]
    DIRECTION OUTPUT ;
    USE SIGNAL ;
    PORT
      LAYER M4 ;
        RECT  0 6.624 0.084 6.648 ;
    END
  END run_count[8]
  PIN run_v
    DIRECTION OUTPUT ;
    USE SIGNAL ;
    PORT
      LAYER M4 ;
        RECT  0 6.768 0.084 6.792 ;
    END
  END run_v
  PIN tgt[0]
    DIRECTION INPUT ;
    USE SIGNAL ;
    PORT
      LAYER M4 ;
        RECT  0 6.912 0.084 6.936 ;
    END
  END tgt[0]
  PIN tgt[1]
    DIRECTION INPUT ;
    USE SIGNAL ;
    PORT
      LAYER M4 ;
        RECT  0 7.056 0.084 7.08 ;
    END
  END tgt[1]
  PIN tgt[2]
    DIRECTION INPUT ;
    USE SIGNAL ;
    PORT
      LAYER M4 ;
        RECT  0 7.2 0.084 7.224 ;
    END
  END tgt[2]
  PIN tgt[3]
    DIRECTION INPUT ;
    USE SIGNAL ;
    PORT
      LAYER M4 ;
        RECT  0 7.344 0.084 7.368 ;
    END
  END tgt[3]
  PIN tgt[4]
    DIRECTION INPUT ;
    USE SIGNAL ;
    PORT
      LAYER M4 ;
        RECT  0 7.488 0.084 7.512 ;
    END
  END tgt[4]
  PIN tgt[5]
    DIRECTION INPUT ;
    USE SIGNAL ;
    PORT
      LAYER M4 ;
        RECT  0 7.632 0.084 7.656 ;
    END
  END tgt[5]
  PIN tgt[6]
    DIRECTION INPUT ;
    USE SIGNAL ;
    PORT
      LAYER M4 ;
        RECT  0 7.776 0.084 7.8 ;
    END
  END tgt[6]
  PIN tgt[7]
    DIRECTION INPUT ;
    USE SIGNAL ;
    PORT
      LAYER M4 ;
        RECT  0 7.92 0.084 7.944 ;
    END
  END tgt[7]
  PIN tgt_active[0]
    DIRECTION INPUT ;
    USE SIGNAL ;
    PORT
      LAYER M4 ;
        RECT  0 8.064 0.084 8.088 ;
    END
  END tgt_active[0]
  PIN tgt_active[1]
    DIRECTION INPUT ;
    USE SIGNAL ;
    PORT
      LAYER M4 ;
        RECT  0 8.208 0.084 8.232 ;
    END
  END tgt_active[1]
  PIN tgt_fault[0]
    DIRECTION INPUT ;
    USE SIGNAL ;
    PORT
      LAYER M4 ;
        RECT  0 8.352 0.084 8.376 ;
    END
  END tgt_fault[0]
  PIN VDD
    DIRECTION INOUT ;
    USE POWER ;
    PORT
      LAYER M5 ;
        RECT  45.792 2.151 45.912 49.689 ;
        RECT  40.392 2.151 40.512 49.689 ;
        RECT  34.992 2.151 35.112 49.689 ;
        RECT  29.592 2.151 29.712 49.689 ;
        RECT  24.192 2.151 24.312 49.689 ;
        RECT  18.792 2.151 18.912 49.689 ;
        RECT  13.392 2.151 13.512 49.689 ;
        RECT  7.992 2.151 8.112 49.689 ;
        RECT  2.592 2.151 2.712 49.689 ;
    END
  END VDD
  PIN VSS
    DIRECTION INOUT ;
    USE GROUND ;
    PORT
      LAYER M5 ;
        RECT  45.6 2.137 45.72 49.703 ;
        RECT  40.2 2.137 40.32 49.703 ;
        RECT  34.8 2.137 34.92 49.703 ;
        RECT  29.4 2.137 29.52 49.703 ;
        RECT  24 2.137 24.12 49.703 ;
        RECT  18.6 2.137 18.72 49.703 ;
        RECT  13.2 2.137 13.32 49.703 ;
        RECT  7.8 2.137 7.92 49.703 ;
        RECT  2.4 2.137 2.52 49.703 ;
    END
  END VSS
  # OT_OBS_CLOSED layer=M5 d_um=1.536 added=60
  OBS
    LAYER RVTN ;
     RECT  2.16 2.16 49.68 2.295 ;
     RECT  2.16 2.565 49.68 2.835 ;
     RECT  2.16 3.105 49.68 3.375 ;
     RECT  2.16 3.645 49.68 3.915 ;
     RECT  2.16 4.185 49.68 4.455 ;
     RECT  2.16 4.725 49.68 4.995 ;
     RECT  2.16 5.265 49.68 5.535 ;
     RECT  2.16 5.805 49.68 6.075 ;
     RECT  2.16 6.345 49.68 6.615 ;
     RECT  2.16 6.885 49.68 7.155 ;
     RECT  2.16 7.425 49.68 7.695 ;
     RECT  2.16 7.965 49.68 8.235 ;
     RECT  2.16 8.505 49.68 8.775 ;
     RECT  2.16 9.045 49.68 9.315 ;
     RECT  2.16 9.585 49.68 9.855 ;
     RECT  2.16 10.125 49.68 10.395 ;
     RECT  2.16 10.665 49.68 10.935 ;
     RECT  2.16 11.205 49.68 11.475 ;
     RECT  2.16 11.745 49.68 12.015 ;
     RECT  2.16 12.285 49.68 12.555 ;
     RECT  2.16 12.825 49.68 13.095 ;
     RECT  2.16 13.365 49.68 13.635 ;
     RECT  2.16 13.905 49.68 14.175 ;
     RECT  2.16 14.445 49.68 14.715 ;
     RECT  2.16 14.985 49.68 15.255 ;
     RECT  2.16 15.525 49.68 15.795 ;
     RECT  2.16 16.065 49.68 16.335 ;
     RECT  2.16 16.605 49.68 16.875 ;
     RECT  2.16 17.145 49.68 17.415 ;
     RECT  2.16 17.685 49.68 17.955 ;
     RECT  2.16 18.225 49.68 18.495 ;
     RECT  2.16 18.765 49.68 19.035 ;
     RECT  2.16 19.305 49.68 19.575 ;
     RECT  2.16 19.845 49.68 20.115 ;
     RECT  2.16 20.385 49.68 20.655 ;
     RECT  2.16 20.925 49.68 21.195 ;
     RECT  2.16 21.465 49.68 21.735 ;
     RECT  2.16 22.005 49.68 22.275 ;
     RECT  2.16 22.545 49.68 22.815 ;
     RECT  2.16 23.085 49.68 23.355 ;
     RECT  2.16 23.625 49.68 23.895 ;
     RECT  2.16 24.165 49.68 24.435 ;
     RECT  2.16 24.705 49.68 24.975 ;
     RECT  2.16 25.245 49.68 25.515 ;
     RECT  2.16 25.785 49.68 26.055 ;
     RECT  2.16 26.325 49.68 26.595 ;
     RECT  2.16 26.865 49.68 27.135 ;
     RECT  2.16 27.405 49.68 27.675 ;
     RECT  2.16 27.945 49.68 28.215 ;
     RECT  2.16 28.485 49.68 28.755 ;
     RECT  2.16 29.025 49.68 29.295 ;
     RECT  2.16 29.565 49.68 29.835 ;
     RECT  2.16 30.105 49.68 30.375 ;
     RECT  2.16 30.645 49.68 30.915 ;
     RECT  2.16 31.185 49.68 31.455 ;
     RECT  2.16 31.725 49.68 31.995 ;
     RECT  2.16 32.265 49.68 32.535 ;
     RECT  2.16 32.805 49.68 33.075 ;
     RECT  2.16 33.345 49.68 33.615 ;
     RECT  2.16 33.885 49.68 34.155 ;
     RECT  2.16 34.425 49.68 34.695 ;
     RECT  2.16 34.965 49.68 35.235 ;
     RECT  2.16 35.505 49.68 35.775 ;
     RECT  2.16 36.045 49.68 36.315 ;
     RECT  2.16 36.585 49.68 36.855 ;
     RECT  2.16 37.125 49.68 37.395 ;
     RECT  2.16 37.665 49.68 37.935 ;
     RECT  2.16 38.205 49.68 38.475 ;
     RECT  2.16 38.745 49.68 39.015 ;
     RECT  2.16 39.285 49.68 39.555 ;
     RECT  2.16 39.825 49.68 40.095 ;
     RECT  2.16 40.365 49.68 40.635 ;
     RECT  2.16 40.905 49.68 41.175 ;
     RECT  2.16 41.445 49.68 41.715 ;
     RECT  2.16 41.985 49.68 42.255 ;
     RECT  2.16 42.525 49.68 42.795 ;
     RECT  2.16 43.065 49.68 43.335 ;
     RECT  2.16 43.605 49.68 43.875 ;
     RECT  2.16 44.145 49.68 44.415 ;
     RECT  2.16 44.685 49.68 44.955 ;
     RECT  2.16 45.225 49.68 45.495 ;
     RECT  2.16 45.765 49.68 46.035 ;
     RECT  2.16 46.305 49.68 46.575 ;
     RECT  2.16 46.845 49.68 47.115 ;
     RECT  2.16 47.385 49.68 47.655 ;
     RECT  2.16 47.925 49.68 48.195 ;
     RECT  2.16 48.465 49.68 48.735 ;
     RECT  2.16 49.005 49.68 49.275 ;
     RECT  2.16 49.545 49.68 49.68 ;
    LAYER RVTP ;
     RECT  2.16 2.295 49.68 2.565 ;
     RECT  2.16 2.835 49.68 3.105 ;
     RECT  2.16 3.375 49.68 3.645 ;
     RECT  2.16 3.915 49.68 4.185 ;
     RECT  2.16 4.455 49.68 4.725 ;
     RECT  2.16 4.995 49.68 5.265 ;
     RECT  2.16 5.535 49.68 5.805 ;
     RECT  2.16 6.075 49.68 6.345 ;
     RECT  2.16 6.615 49.68 6.885 ;
     RECT  2.16 7.155 49.68 7.425 ;
     RECT  2.16 7.695 49.68 7.965 ;
     RECT  2.16 8.235 49.68 8.505 ;
     RECT  2.16 8.775 49.68 9.045 ;
     RECT  2.16 9.315 49.68 9.585 ;
     RECT  2.16 9.855 49.68 10.125 ;
     RECT  2.16 10.395 49.68 10.665 ;
     RECT  2.16 10.935 49.68 11.205 ;
     RECT  2.16 11.475 49.68 11.745 ;
     RECT  2.16 12.015 49.68 12.285 ;
     RECT  2.16 12.555 49.68 12.825 ;
     RECT  2.16 13.095 49.68 13.365 ;
     RECT  2.16 13.635 49.68 13.905 ;
     RECT  2.16 14.175 49.68 14.445 ;
     RECT  2.16 14.715 49.68 14.985 ;
     RECT  2.16 15.255 49.68 15.525 ;
     RECT  2.16 15.795 49.68 16.065 ;
     RECT  2.16 16.335 49.68 16.605 ;
     RECT  2.16 16.875 49.68 17.145 ;
     RECT  2.16 17.415 49.68 17.685 ;
     RECT  2.16 17.955 49.68 18.225 ;
     RECT  2.16 18.495 49.68 18.765 ;
     RECT  2.16 19.035 49.68 19.305 ;
     RECT  2.16 19.575 49.68 19.845 ;
     RECT  2.16 20.115 49.68 20.385 ;
     RECT  2.16 20.655 49.68 20.925 ;
     RECT  2.16 21.195 49.68 21.465 ;
     RECT  2.16 21.735 49.68 22.005 ;
     RECT  2.16 22.275 49.68 22.545 ;
     RECT  2.16 22.815 49.68 23.085 ;
     RECT  2.16 23.355 49.68 23.625 ;
     RECT  2.16 23.895 49.68 24.165 ;
     RECT  2.16 24.435 49.68 24.705 ;
     RECT  2.16 24.975 49.68 25.245 ;
     RECT  2.16 25.515 49.68 25.785 ;
     RECT  2.16 26.055 49.68 26.325 ;
     RECT  2.16 26.595 49.68 26.865 ;
     RECT  2.16 27.135 49.68 27.405 ;
     RECT  2.16 27.675 49.68 27.945 ;
     RECT  2.16 28.215 49.68 28.485 ;
     RECT  2.16 28.755 49.68 29.025 ;
     RECT  2.16 29.295 49.68 29.565 ;
     RECT  2.16 29.835 49.68 30.105 ;
     RECT  2.16 30.375 49.68 30.645 ;
     RECT  2.16 30.915 49.68 31.185 ;
     RECT  2.16 31.455 49.68 31.725 ;
     RECT  2.16 31.995 49.68 32.265 ;
     RECT  2.16 32.535 49.68 32.805 ;
     RECT  2.16 33.075 49.68 33.345 ;
     RECT  2.16 33.615 49.68 33.885 ;
     RECT  2.16 34.155 49.68 34.425 ;
     RECT  2.16 34.695 49.68 34.965 ;
     RECT  2.16 35.235 49.68 35.505 ;
     RECT  2.16 35.775 49.68 36.045 ;
     RECT  2.16 36.315 49.68 36.585 ;
     RECT  2.16 36.855 49.68 37.125 ;
     RECT  2.16 37.395 49.68 37.665 ;
     RECT  2.16 37.935 49.68 38.205 ;
     RECT  2.16 38.475 49.68 38.745 ;
     RECT  2.16 39.015 49.68 39.285 ;
     RECT  2.16 39.555 49.68 39.825 ;
     RECT  2.16 40.095 49.68 40.365 ;
     RECT  2.16 40.635 49.68 40.905 ;
     RECT  2.16 41.175 49.68 41.445 ;
     RECT  2.16 41.715 49.68 41.985 ;
     RECT  2.16 42.255 49.68 42.525 ;
     RECT  2.16 42.795 49.68 43.065 ;
     RECT  2.16 43.335 49.68 43.605 ;
     RECT  2.16 43.875 49.68 44.145 ;
     RECT  2.16 44.415 49.68 44.685 ;
     RECT  2.16 44.955 49.68 45.225 ;
     RECT  2.16 45.495 49.68 45.765 ;
     RECT  2.16 46.035 49.68 46.305 ;
     RECT  2.16 46.575 49.68 46.845 ;
     RECT  2.16 47.115 49.68 47.385 ;
     RECT  2.16 47.655 49.68 47.925 ;
     RECT  2.16 48.195 49.68 48.465 ;
     RECT  2.16 48.735 49.68 49.005 ;
     RECT  2.16 49.275 49.68 49.545 ;
    LAYER M1 ;
     RECT  2.16 2.151 49.68 49.689 ;
    LAYER M2 ;
     RECT  0.175 4.896 0.535 4.914 ;
     RECT  0.103 6.246 0.535 6.264 ;
     RECT  0.103 13.032 0.535 13.05 ;
     RECT  0.535 6.246 1.175 6.606 ;
     RECT  0.103 3.816 2.16 3.834 ;
     RECT  0.535 4.896 2.16 5.454 ;
     RECT  1.175 6.246 2.16 6.336 ;
     RECT  0.535 7.362 2.16 7.38 ;
     RECT  0.103 9.018 2.16 9.036 ;
     RECT  0.103 10.206 2.16 10.224 ;
     RECT  0.535 12.492 2.16 13.05 ;
     RECT  0.535 14.22 2.16 14.238 ;
     RECT  0.535 18.666 2.16 18.684 ;
     RECT  0.103 21.006 2.16 21.024 ;
     RECT  2.16 2.151 14.827 49.689 ;
     RECT  14.827 2.106 15.251 49.689 ;
     RECT  15.251 2.151 24.511 49.689 ;
     RECT  24.511 2.106 25.187 49.689 ;
     RECT  25.187 2.151 27.247 49.689 ;
     RECT  27.247 2.106 27.923 49.689 ;
     RECT  31.135 1.152 31.235 1.17 ;
     RECT  27.923 2.151 39.307 49.689 ;
     RECT  39.307 2.106 39.695 49.689 ;
     RECT  39.695 2.151 42.187 49.689 ;
     RECT  42.187 2.106 42.575 49.689 ;
     RECT  42.575 2.151 46.831 49.689 ;
     RECT  46.831 2.034 47.759 49.689 ;
     RECT  47.759 2.106 48.083 49.689 ;
     RECT  48.083 2.151 49.68 49.689 ;
     RECT  49.68 9.936 50.171 34.614 ;
     RECT  49.68 35.442 50.171 47.844 ;
     RECT  50.171 10.098 50.207 27.936 ;
     RECT  50.171 29.106 50.207 34.614 ;
     RECT  50.207 10.098 50.711 27.702 ;
     RECT  50.207 29.61 50.711 34.614 ;
     RECT  50.171 35.442 50.711 44.064 ;
     RECT  50.171 45 50.711 47.844 ;
     RECT  50.711 10.476 50.747 11.772 ;
     RECT  50.711 12.528 50.747 14.004 ;
     RECT  50.711 14.796 50.747 15.552 ;
     RECT  50.711 16.344 50.747 17.244 ;
     RECT  50.711 18.306 50.747 19.404 ;
     RECT  50.711 20.196 50.747 20.754 ;
     RECT  50.711 21.51 50.747 21.834 ;
     RECT  50.711 22.716 50.747 23.454 ;
     RECT  50.711 24.246 50.747 26.352 ;
     RECT  50.711 29.916 50.747 34.254 ;
     RECT  50.711 35.784 50.747 37.728 ;
     RECT  50.711 38.952 50.747 41.508 ;
     RECT  50.711 42.336 50.747 43.434 ;
     RECT  50.711 46.656 50.747 47.304 ;
     RECT  50.747 30.654 50.783 32.328 ;
     RECT  50.747 33.426 50.783 34.254 ;
     RECT  50.747 47.286 50.783 47.304 ;
     RECT  50.747 10.476 51.755 10.494 ;
     RECT  50.747 12.87 51.755 12.888 ;
     RECT  50.747 13.644 51.755 14.004 ;
     RECT  50.747 14.796 51.755 14.814 ;
     RECT  50.747 16.344 51.755 16.362 ;
     RECT  50.747 19.044 51.755 19.062 ;
     RECT  50.747 20.196 51.755 20.214 ;
     RECT  50.747 21.51 51.755 21.528 ;
     RECT  50.747 24.246 51.755 24.534 ;
     RECT  50.747 25.794 51.755 25.812 ;
     RECT  50.711 27.144 51.755 27.702 ;
     RECT  50.783 30.654 51.755 31.212 ;
     RECT  50.783 32.31 51.755 32.328 ;
     RECT  50.783 33.426 51.755 34.182 ;
     RECT  50.747 35.784 51.755 36.342 ;
     RECT  50.747 37.476 51.755 37.494 ;
     RECT  50.747 39.87 51.755 41.508 ;
     RECT  50.747 42.696 51.755 42.714 ;
     RECT  50.711 45 51.755 45.594 ;
    LAYER M3 ;
     RECT  14.904 0.091 14.922 0.139 ;
     RECT  17.388 0.091 18.486 0.139 ;
     RECT  19.908 0.091 20.07 0.139 ;
     RECT  20.916 0.091 20.934 0.139 ;
     RECT  21.708 0.091 22.086 0.139 ;
     RECT  22.824 0.091 23.562 0.139 ;
     RECT  24.444 0.091 25.47 0.139 ;
     RECT  26.244 0.091 26.262 0.139 ;
     RECT  27.036 0.091 27.054 0.139 ;
     RECT  28.224 0.091 28.242 0.139 ;
     RECT  39.888 0.091 39.906 0.139 ;
     RECT  42.804 0.091 42.822 0.139 ;
     RECT  43.632 0.091 43.83 0.139 ;
     RECT  44.604 0.091 44.622 0.139 ;
     RECT  45.396 0.091 45.414 0.139 ;
     RECT  39.888 0.139 40.05 0.187 ;
     RECT  41.076 0.091 41.526 0.187 ;
     RECT  42.48 0.139 43.83 0.187 ;
     RECT  46.26 0.091 46.962 0.235 ;
     RECT  16.2 0.091 16.218 0.475 ;
     RECT  9.936 0.475 9.954 0.523 ;
     RECT  16.2 0.475 16.362 0.523 ;
     RECT  17.316 0.139 18.486 0.523 ;
     RECT  34.236 0.091 34.254 0.523 ;
     RECT  36.396 0.091 36.774 0.523 ;
     RECT  39.636 0.187 40.122 0.523 ;
     RECT  41.076 0.187 43.83 0.523 ;
     RECT  11.268 0.091 14.166 0.571 ;
     RECT  14.904 0.139 14.994 0.571 ;
     RECT  15.804 0.523 16.434 0.571 ;
     RECT  17.28 0.523 18.486 0.571 ;
     RECT  19.908 0.139 28.962 0.571 ;
     RECT  29.844 0.091 33.318 0.571 ;
     RECT  34.236 0.523 34.362 0.571 ;
     RECT  36.288 0.523 36.774 0.571 ;
     RECT  37.872 0.091 38.142 0.571 ;
     RECT  38.88 0.091 38.898 0.571 ;
     RECT  44.604 0.139 45.414 0.571 ;
     RECT  46.152 0.235 46.962 0.571 ;
     RECT  9.684 0.523 9.954 1.099 ;
     RECT  11.268 0.571 16.434 1.099 ;
     RECT  34.236 0.571 34.686 1.099 ;
     RECT  35.46 0.091 35.478 1.099 ;
     RECT  39.636 0.523 43.83 1.099 ;
     RECT  44.604 0.571 47.142 1.099 ;
     RECT  34.236 1.099 35.478 1.147 ;
     RECT  36.288 0.571 38.898 1.147 ;
     RECT  9.684 1.099 16.434 1.723 ;
     RECT  17.28 0.571 19.17 1.723 ;
     RECT  19.908 0.571 33.318 1.723 ;
     RECT  34.236 1.147 38.898 1.723 ;
     RECT  39.636 1.099 47.214 1.723 ;
     RECT  48.528 0.091 48.546 1.723 ;
     RECT  9.684 1.723 48.546 1.915 ;
     RECT  9.684 1.915 48.654 2.263 ;
     RECT  2.415 2.143 2.505 2.413 ;
     RECT  7.815 2.143 7.905 2.413 ;
     RECT  9.684 2.263 48.798 2.569 ;
     RECT  9.684 2.569 48.942 2.605 ;
     RECT  9.468 2.605 48.942 2.767 ;
     RECT  4.644 3.001 4.662 3.073 ;
     RECT  4.32 3.073 4.662 3.145 ;
     RECT  5.4 3.073 5.418 3.145 ;
     RECT  7.815 2.413 8.097 3.145 ;
     RECT  9.468 2.767 49.05 3.145 ;
     RECT  7.815 3.145 49.05 3.181 ;
     RECT  7.815 3.181 49.266 3.299 ;
     RECT  7.815 3.299 48.978 3.343 ;
     RECT  4.32 3.145 5.418 3.403 ;
     RECT  6.156 3.379 6.174 3.403 ;
     RECT  7.308 3.343 48.978 3.403 ;
     RECT  2.415 2.413 2.697 3.415 ;
     RECT  3.708 3.403 6.174 3.415 ;
     RECT  7.164 3.403 48.978 3.415 ;
     RECT  6.912 3.415 48.978 3.437 ;
     RECT  9.36 3.437 48.978 3.479 ;
     RECT  2.415 3.415 6.174 3.541 ;
     RECT  2.376 3.541 6.174 3.721 ;
     RECT  6.912 3.437 8.514 3.721 ;
     RECT  9.432 3.479 48.978 3.875 ;
     RECT  0.108 3.811 0.126 4.061 ;
     RECT  9.468 3.875 48.978 4.261 ;
     RECT  2.376 3.721 8.514 4.315 ;
     RECT  2.304 4.315 8.514 4.693 ;
     RECT  9.468 4.261 49.086 4.693 ;
     RECT  2.304 4.693 49.086 5.099 ;
     RECT  2.304 5.099 48.798 5.333 ;
     RECT  2.304 5.333 48.258 5.357 ;
     RECT  0.144 4.891 0.198 5.431 ;
     RECT  0.144 5.431 0.558 5.611 ;
     RECT  2.34 5.357 48.258 5.729 ;
     RECT  2.34 5.729 48.186 5.999 ;
     RECT  2.34 5.999 48.114 6.179 ;
     RECT  0.108 5.611 0.558 6.269 ;
     RECT  0.54 6.269 0.558 6.313 ;
     RECT  2.34 6.179 48.078 6.421 ;
     RECT  2.304 6.421 48.078 6.449 ;
     RECT  0.54 6.313 1.17 6.611 ;
     RECT  2.304 6.449 47.826 7.079 ;
     RECT  2.304 7.079 24.894 7.115 ;
     RECT  2.415 7.115 24.894 7.151 ;
     RECT  25.668 7.079 47.826 7.187 ;
     RECT  26.1 7.187 47.826 7.349 ;
     RECT  0.54 6.611 0.558 7.517 ;
     RECT  26.316 7.349 47.826 7.529 ;
     RECT  26.316 7.529 40.842 7.763 ;
     RECT  41.616 7.529 47.826 7.763 ;
     RECT  2.415 7.151 24.786 7.799 ;
     RECT  41.832 7.763 47.826 7.799 ;
     RECT  2.415 7.799 24.297 7.915 ;
     RECT  26.496 7.763 40.842 7.997 ;
     RECT  26.496 7.997 26.55 8.069 ;
     RECT  0.144 8.059 0.162 8.189 ;
     RECT  26.496 8.069 26.514 8.195 ;
     RECT  41.832 7.799 46.926 8.231 ;
     RECT  42.408 8.231 46.926 8.333 ;
     RECT  29.124 7.997 40.842 8.347 ;
     RECT  27.756 7.997 28.386 8.429 ;
     RECT  2.304 7.915 24.297 8.635 ;
     RECT  29.124 8.347 41.058 8.671 ;
     RECT  29.124 8.671 41.13 8.735 ;
     RECT  27.756 8.429 27.918 8.771 ;
     RECT  40.068 8.735 41.13 8.771 ;
     RECT  2.268 8.635 24.297 8.807 ;
     RECT  29.124 8.735 39.15 8.815 ;
     RECT  40.215 8.771 41.13 8.843 ;
     RECT  27.756 8.771 27.774 8.879 ;
     RECT  29.088 8.815 39.15 8.969 ;
     RECT  42.444 8.333 46.926 9.113 ;
     RECT  42.552 9.113 46.926 9.211 ;
     RECT  47.736 7.799 47.826 9.211 ;
     RECT  0.108 9.013 0.126 9.245 ;
     RECT  2.304 8.807 24.297 9.643 ;
     RECT  42.552 9.211 47.826 9.653 ;
     RECT  40.215 8.843 40.497 9.751 ;
     RECT  2.268 9.643 24.297 9.815 ;
     RECT  29.415 8.969 39.15 9.823 ;
     RECT  2.304 9.815 24.297 9.931 ;
     RECT  40.215 9.751 41.058 9.931 ;
     RECT  48.6 9.787 48.618 9.931 ;
     RECT  29.088 9.823 39.15 9.959 ;
     RECT  50.148 9.931 50.166 9.968 ;
     RECT  42.624 9.653 47.826 10.057 ;
     RECT  48.564 9.931 48.618 10.057 ;
     RECT  25.488 10.057 25.506 10.093 ;
     RECT  40.215 9.931 41.13 10.229 ;
     RECT  0.108 10.201 0.126 10.253 ;
     RECT  42.624 10.057 48.618 10.363 ;
     RECT  51.732 10.363 51.75 10.499 ;
     RECT  2.304 9.931 24.606 10.561 ;
     RECT  25.488 10.093 26.01 10.561 ;
     RECT  42.624 10.363 49.338 10.625 ;
     RECT  50.184 10.075 50.706 10.933 ;
     RECT  2.304 10.561 26.01 11.173 ;
     RECT  40.215 10.229 41.058 11.273 ;
     RECT  50.184 10.933 50.742 11.803 ;
     RECT  50.148 11.803 50.742 11.981 ;
     RECT  42.624 10.625 48.69 11.983 ;
     RECT  42.624 11.983 49.014 12.091 ;
     RECT  42.624 12.091 49.23 12.235 ;
     RECT  42.624 12.235 49.806 12.245 ;
     RECT  27.072 11.713 27.09 12.253 ;
     RECT  40.215 11.273 40.497 12.361 ;
     RECT  0.54 12.487 0.558 12.557 ;
     RECT  2.304 11.173 26.046 12.757 ;
     RECT  27.072 12.253 27.126 12.793 ;
     RECT  28.26 11.911 28.278 12.829 ;
     RECT  49.716 12.245 49.806 12.829 ;
     RECT  50.688 11.981 50.742 12.829 ;
     RECT  27.036 12.793 27.126 12.901 ;
     RECT  28.26 12.829 28.314 12.901 ;
     RECT  49.716 12.829 50.742 12.929 ;
     RECT  2.268 12.757 26.046 12.989 ;
     RECT  29.415 9.959 39.15 13.019 ;
     RECT  42.624 12.245 48.834 13.019 ;
     RECT  27.036 12.901 28.314 13.027 ;
     RECT  0.108 13.027 0.126 13.133 ;
     RECT  40.215 12.361 41.058 13.135 ;
     RECT  27.036 13.027 28.35 13.369 ;
     RECT  40.215 13.135 41.13 13.397 ;
     RECT  27.036 13.369 28.422 13.405 ;
     RECT  32.724 13.019 39.15 13.433 ;
     RECT  27.036 13.405 28.53 13.531 ;
     RECT  32.796 13.433 39.15 13.631 ;
     RECT  27.036 13.531 28.602 13.639 ;
     RECT  49.788 12.929 50.742 13.709 ;
     RECT  42.624 13.019 48.798 13.801 ;
     RECT  49.788 13.709 49.806 13.801 ;
     RECT  27 13.639 28.602 13.945 ;
     RECT  29.415 13.019 31.698 13.945 ;
     RECT  33.084 13.631 39.15 14.009 ;
     RECT  51.732 12.667 51.75 14.009 ;
     RECT  42.624 13.801 49.806 14.203 ;
     RECT  42.588 14.203 49.806 14.243 ;
     RECT  0.54 14.215 0.558 14.429 ;
     RECT  50.688 13.709 50.742 14.429 ;
     RECT  42.624 14.243 49.806 14.477 ;
     RECT  50.688 14.429 50.706 14.521 ;
     RECT  33.624 14.009 39.15 14.639 ;
     RECT  51.732 14.791 51.75 14.861 ;
     RECT  50.148 14.521 50.706 14.909 ;
     RECT  42.624 14.477 49.086 15.323 ;
     RECT  42.624 15.323 48.618 15.449 ;
     RECT  50.688 14.909 50.706 15.529 ;
     RECT  50.688 15.529 50.742 15.581 ;
     RECT  42.624 15.449 48.51 15.593 ;
     RECT  49.572 15.403 49.806 15.691 ;
     RECT  50.688 15.581 50.706 15.691 ;
     RECT  49.572 15.691 50.706 15.899 ;
     RECT  50.148 15.899 50.706 16.025 ;
     RECT  51.732 16.123 51.75 16.367 ;
     RECT  42.624 15.593 48.474 16.411 ;
     RECT  50.688 16.025 50.706 16.501 ;
     RECT  42.624 16.411 49.158 16.529 ;
     RECT  42.624 16.529 48.618 16.555 ;
     RECT  42.372 16.555 48.618 16.781 ;
     RECT  42.372 16.781 48.546 16.835 ;
     RECT  50.688 16.501 50.742 16.843 ;
     RECT  50.652 16.843 50.742 16.88 ;
     RECT  51.66 16.891 51.678 17.309 ;
     RECT  49.68 17.419 49.698 17.519 ;
     RECT  0.144 17.467 0.162 17.597 ;
     RECT  42.84 16.835 48.546 18.031 ;
     RECT  2.304 12.989 26.046 18.221 ;
     RECT  2.304 18.221 9.918 18.227 ;
     RECT  49.716 18.031 49.734 18.283 ;
     RECT  40.215 13.397 40.497 18.301 ;
     RECT  49.608 18.283 49.734 18.391 ;
     RECT  50.688 16.88 50.742 18.391 ;
     RECT  42.84 18.031 48.834 18.571 ;
     RECT  49.608 18.391 50.742 18.571 ;
     RECT  40.215 18.301 41.058 18.599 ;
     RECT  42.84 18.571 50.742 18.605 ;
     RECT  42.84 18.605 49.734 18.689 ;
     RECT  0.54 18.661 0.558 18.715 ;
     RECT  0.18 18.715 0.558 18.893 ;
     RECT  42.84 18.689 48.942 18.959 ;
     RECT  42.84 18.959 48.798 18.995 ;
     RECT  51.732 18.859 51.75 19.067 ;
     RECT  42.84 18.995 48.654 19.111 ;
     RECT  33.732 14.639 39.15 19.229 ;
     RECT  42.588 19.111 48.654 19.237 ;
     RECT  0.144 19.147 0.162 19.373 ;
     RECT  50.688 18.605 50.742 19.613 ;
     RECT  40.215 18.599 40.497 19.615 ;
     RECT  50.688 19.613 50.706 19.769 ;
     RECT  42.408 19.237 48.654 19.777 ;
     RECT  2.304 18.227 9.558 19.841 ;
     RECT  49.716 18.689 49.734 20.011 ;
     RECT  42.408 19.777 48.762 20.155 ;
     RECT  51.732 20.155 51.75 20.219 ;
     RECT  42.372 20.155 48.762 20.309 ;
     RECT  42.408 20.309 48.762 20.345 ;
     RECT  42.696 20.345 48.762 20.353 ;
     RECT  49.716 20.011 50.166 20.425 ;
     RECT  42.696 20.353 48.798 20.453 ;
     RECT  0.144 20.347 0.162 20.477 ;
     RECT  2.304 19.841 8.514 20.489 ;
     RECT  42.696 20.453 48.618 20.579 ;
     RECT  49.572 20.425 50.166 20.587 ;
     RECT  49.356 20.587 50.166 20.725 ;
     RECT  49.356 20.725 50.742 20.765 ;
     RECT  49.356 20.765 50.706 20.909 ;
     RECT  49.356 20.909 49.842 20.957 ;
     RECT  40.215 19.615 41.058 20.993 ;
     RECT  0.108 21.001 0.126 21.053 ;
     RECT  27 13.945 31.698 21.091 ;
     RECT  2.304 20.489 8.262 21.119 ;
     RECT  2.304 21.119 8.19 21.263 ;
     RECT  42.696 20.579 48.582 21.397 ;
     RECT  27 21.091 31.95 21.433 ;
     RECT  51.732 21.307 51.75 21.533 ;
     RECT  0.144 21.307 0.162 21.629 ;
     RECT  2.304 21.263 8.097 21.659 ;
     RECT  42.696 21.397 48.906 21.775 ;
     RECT  50.688 20.909 50.706 21.811 ;
     RECT  42.408 21.775 48.906 21.901 ;
     RECT  50.688 21.811 50.742 21.917 ;
     RECT  4.176 21.659 8.097 21.965 ;
     RECT  27 21.433 32.094 21.973 ;
     RECT  42.336 21.901 48.906 22.009 ;
     RECT  49.68 20.957 49.842 22.009 ;
     RECT  50.688 21.917 50.706 22.009 ;
     RECT  27 21.973 32.634 22.045 ;
     RECT  6.804 21.965 8.097 22.109 ;
     RECT  2.304 21.659 3.438 22.199 ;
     RECT  4.176 21.965 6.03 22.199 ;
     RECT  7.452 22.109 8.097 22.199 ;
     RECT  2.304 22.199 3.186 22.205 ;
     RECT  4.572 22.199 4.662 22.205 ;
     RECT  2.34 22.205 3.186 22.208 ;
     RECT  2.34 22.208 2.697 22.235 ;
     RECT  4.572 22.205 4.59 22.235 ;
     RECT  5.58 22.199 6.03 22.235 ;
     RECT  42.336 22.009 50.706 22.243 ;
     RECT  27 22.045 32.814 22.441 ;
     RECT  33.84 19.229 39.15 22.441 ;
     RECT  42.192 22.243 50.706 22.513 ;
     RECT  42.156 22.513 50.706 22.577 ;
     RECT  42.156 22.577 49.338 22.621 ;
     RECT  42.084 22.621 49.338 22.711 ;
     RECT  50.148 22.577 50.706 22.711 ;
     RECT  42.012 22.711 49.338 22.883 ;
     RECT  42.3 22.883 49.338 23.045 ;
     RECT  50.148 22.711 50.742 23.549 ;
     RECT  42.3 23.045 48.726 23.585 ;
     RECT  50.688 23.549 50.742 23.645 ;
     RECT  27 22.441 39.15 23.657 ;
     RECT  42.732 23.585 48.726 23.899 ;
     RECT  27 23.657 38.934 24.089 ;
     RECT  40.215 20.993 40.497 24.241 ;
     RECT  40.215 24.241 41.058 24.359 ;
     RECT  51.732 23.899 51.75 24.539 ;
     RECT  50.688 23.645 50.706 24.601 ;
     RECT  42.732 23.899 48.762 24.619 ;
     RECT  42.732 24.619 48.87 24.665 ;
     RECT  27 24.089 38.898 24.971 ;
     RECT  27 24.971 38.826 25.043 ;
     RECT  42.732 24.665 48.798 25.043 ;
     RECT  50.148 24.601 50.706 25.051 ;
     RECT  49.68 25.051 50.706 25.141 ;
     RECT  42.732 25.043 48.618 25.213 ;
     RECT  49.68 25.141 50.742 25.373 ;
     RECT  49.68 25.373 50.706 25.517 ;
     RECT  27 25.043 38.79 25.583 ;
     RECT  42.516 25.213 48.618 25.709 ;
     RECT  42.516 25.709 48.474 25.745 ;
     RECT  51.732 25.627 51.75 25.817 ;
     RECT  10.692 18.221 26.046 25.951 ;
     RECT  10.692 25.951 26.226 25.997 ;
     RECT  49.68 25.517 50.166 26.053 ;
     RECT  49.608 26.053 50.166 26.329 ;
     RECT  49.608 26.329 50.742 26.347 ;
     RECT  27 25.583 38.574 26.401 ;
     RECT  49.572 26.347 50.742 26.525 ;
     RECT  42.768 25.745 48.474 26.635 ;
     RECT  49.572 26.525 50.706 26.635 ;
     RECT  42.768 26.635 50.706 26.699 ;
     RECT  42.768 26.699 48.87 26.789 ;
     RECT  42.768 26.789 48.546 26.825 ;
     RECT  27 26.401 38.79 27.031 ;
     RECT  42.84 26.825 48.546 27.059 ;
     RECT  49.608 26.699 50.706 27.059 ;
     RECT  27 27.031 38.826 27.203 ;
     RECT  49.608 27.059 50.202 27.499 ;
     RECT  51.732 27.067 51.75 27.707 ;
     RECT  49.572 27.499 50.202 27.779 ;
     RECT  42.84 27.059 48.51 27.841 ;
     RECT  49.608 27.779 50.202 27.965 ;
     RECT  42.84 27.841 48.87 28.013 ;
     RECT  27 27.203 38.574 28.111 ;
     RECT  42.84 28.013 48.51 28.139 ;
     RECT  49.608 27.965 50.166 28.253 ;
     RECT  27 28.111 38.79 28.319 ;
     RECT  42.84 28.139 48.474 28.409 ;
     RECT  50.148 28.253 50.166 28.409 ;
     RECT  42.84 28.409 48.294 29.101 ;
     RECT  42.768 29.101 48.294 29.227 ;
     RECT  27 28.319 38.574 29.335 ;
     RECT  42.768 29.227 48.51 29.371 ;
     RECT  50.184 29.101 50.202 29.461 ;
     RECT  27 29.335 38.646 29.605 ;
     RECT  50.148 29.461 50.202 29.605 ;
     RECT  42.768 29.371 48.87 29.839 ;
     RECT  40.215 24.359 40.497 29.911 ;
     RECT  50.148 29.605 50.706 29.911 ;
     RECT  40.032 29.911 40.497 30.001 ;
     RECT  50.148 29.911 50.742 30.091 ;
     RECT  49.788 30.091 50.742 30.209 ;
     RECT  27 29.605 38.97 30.271 ;
     RECT  39.708 30.001 40.497 30.271 ;
     RECT  50.148 30.209 50.742 30.299 ;
     RECT  50.184 30.299 50.742 30.413 ;
     RECT  42.768 29.839 49.014 30.541 ;
     RECT  42.768 30.541 49.194 30.713 ;
     RECT  50.184 30.413 50.706 30.749 ;
     RECT  42.768 30.713 48.87 30.839 ;
     RECT  42.84 30.839 48.762 30.875 ;
     RECT  27 30.271 40.497 31.081 ;
     RECT  51.732 30.523 51.75 31.217 ;
     RECT  49.608 31.525 49.626 31.565 ;
     RECT  42.84 30.875 48.726 31.621 ;
     RECT  50.688 30.749 50.706 31.621 ;
     RECT  50.688 31.621 50.742 31.729 ;
     RECT  42.84 31.621 48.87 31.801 ;
     RECT  50.688 31.729 50.778 31.801 ;
     RECT  50.148 31.801 50.778 32.141 ;
     RECT  27 31.081 41.13 32.161 ;
     RECT  27 32.161 41.274 32.269 ;
     RECT  51.732 32.251 51.75 32.333 ;
     RECT  27 32.269 41.49 32.341 ;
     RECT  42.84 31.801 48.906 32.611 ;
     RECT  42.84 32.611 49.05 32.701 ;
     RECT  42.804 32.701 49.05 32.717 ;
     RECT  27 32.341 41.598 32.845 ;
     RECT  50.148 32.141 50.742 32.861 ;
     RECT  27 32.845 41.778 33.151 ;
     RECT  42.804 32.717 48.618 33.151 ;
     RECT  50.148 32.861 50.706 33.269 ;
     RECT  27 33.151 48.618 33.619 ;
     RECT  27 33.619 49.338 33.845 ;
     RECT  50.184 33.269 50.706 34.051 ;
     RECT  50.184 34.051 50.742 34.123 ;
     RECT  50.148 34.123 50.742 34.16 ;
     RECT  51.732 33.403 51.75 34.187 ;
     RECT  9.54 19.841 9.558 34.219 ;
     RECT  10.692 25.997 26.046 34.219 ;
     RECT  50.688 34.16 50.742 34.231 ;
     RECT  50.688 34.231 50.778 34.589 ;
     RECT  50.688 34.589 50.706 34.619 ;
     RECT  27 33.845 49.122 34.693 ;
     RECT  9.54 34.219 26.046 34.799 ;
     RECT  27 34.693 49.626 35.275 ;
     RECT  27 35.275 50.202 35.303 ;
     RECT  50.148 35.303 50.202 35.419 ;
     RECT  50.148 35.419 50.706 35.465 ;
     RECT  50.148 35.465 50.202 35.609 ;
     RECT  27 35.303 49.158 36.139 ;
     RECT  50.148 35.609 50.166 36.239 ;
     RECT  51.732 35.707 51.75 36.347 ;
     RECT  27 36.139 49.374 36.571 ;
     RECT  50.688 36.427 50.706 36.589 ;
     RECT  50.688 36.589 50.742 36.779 ;
     RECT  27 36.571 49.806 37.037 ;
     RECT  51.732 37.435 51.75 37.499 ;
     RECT  50.724 36.779 50.742 37.561 ;
     RECT  27 37.037 49.626 37.661 ;
     RECT  50.688 37.561 50.742 38.045 ;
     RECT  49.608 37.661 49.626 38.281 ;
     RECT  49.608 38.281 49.662 38.713 ;
     RECT  50.688 38.045 50.706 38.713 ;
     RECT  49.608 38.713 50.706 38.875 ;
     RECT  27 37.661 48.618 38.947 ;
     RECT  49.356 38.875 50.706 38.947 ;
     RECT  27 38.947 50.742 39.119 ;
     RECT  27 39.119 48.582 39.479 ;
     RECT  49.572 39.119 50.742 39.485 ;
     RECT  49.572 39.485 50.706 39.659 ;
     RECT  9.576 34.799 26.046 39.883 ;
     RECT  27 39.479 48.438 39.883 ;
     RECT  51.732 39.739 51.75 39.883 ;
     RECT  51.66 39.883 51.75 40.013 ;
     RECT  49.608 39.659 50.706 40.199 ;
     RECT  9.576 39.883 48.438 40.261 ;
     RECT  9.576 40.261 48.654 40.711 ;
     RECT  9.576 40.711 48.69 40.747 ;
     RECT  9.576 40.747 49.41 41.009 ;
     RECT  9.576 41.009 49.086 41.021 ;
     RECT  50.184 40.199 50.706 41.035 ;
     RECT  51.732 40.013 51.75 41.513 ;
     RECT  27 41.021 49.086 41.549 ;
     RECT  50.148 41.035 50.706 42.089 ;
     RECT  50.184 42.089 50.706 42.221 ;
     RECT  50.22 42.221 50.706 42.331 ;
     RECT  9.576 41.021 26.046 42.457 ;
     RECT  27 41.549 49.014 42.457 ;
     RECT  50.22 42.331 50.742 42.653 ;
     RECT  9.576 42.457 49.014 42.719 ;
     RECT  27 42.719 49.014 42.755 ;
     RECT  51.732 42.691 51.75 42.797 ;
     RECT  50.22 42.653 50.706 43.051 ;
     RECT  50.148 43.051 50.706 43.069 ;
     RECT  50.112 43.069 50.706 43.277 ;
     RECT  50.184 43.277 50.706 43.411 ;
     RECT  50.184 43.411 50.742 43.517 ;
     RECT  49.284 43.681 49.302 43.835 ;
     RECT  27 42.755 48.546 43.951 ;
     RECT  50.184 43.517 50.706 44.093 ;
     RECT  27 43.951 48.978 44.635 ;
     RECT  50.148 44.203 50.166 44.635 ;
     RECT  27 44.635 50.166 44.789 ;
     RECT  27 44.789 49.05 44.813 ;
     RECT  49.788 44.789 50.166 45.229 ;
     RECT  49.788 45.229 50.706 45.499 ;
     RECT  51.732 44.923 51.75 45.599 ;
     RECT  49.788 45.499 50.742 45.833 ;
     RECT  27 44.813 48.87 45.869 ;
     RECT  49.788 45.833 49.878 45.931 ;
     RECT  9.576 42.719 26.046 46.345 ;
     RECT  27 45.869 48.834 46.345 ;
     RECT  49.572 45.931 49.878 46.409 ;
     RECT  9.576 46.345 48.834 46.499 ;
     RECT  9.576 46.499 48.69 46.741 ;
     RECT  50.688 45.833 50.742 46.921 ;
     RECT  50.652 46.921 50.742 47.011 ;
     RECT  9.54 46.741 48.69 47.281 ;
     RECT  50.148 47.011 50.742 47.281 ;
     RECT  50.148 47.281 50.778 47.405 ;
     RECT  9.54 47.281 49.302 47.425 ;
     RECT  9.252 47.425 49.302 47.659 ;
     RECT  50.148 47.405 50.706 47.659 ;
     RECT  7.815 22.199 8.097 47.695 ;
     RECT  9.252 47.659 50.706 47.695 ;
     RECT  7.815 47.695 50.706 47.696 ;
     RECT  50.148 47.696 50.706 47.759 ;
     RECT  51.66 47.707 51.678 47.837 ;
     RECT  50.688 47.759 50.706 47.849 ;
     RECT  7.815 47.696 48.906 48.155 ;
     RECT  7.815 48.155 48.438 48.659 ;
     RECT  7.815 48.659 48.294 48.929 ;
     RECT  7.815 48.929 22.734 49.199 ;
     RECT  23.508 48.929 48.294 49.199 ;
     RECT  7.815 49.199 22.662 49.373 ;
     RECT  23.508 49.199 47.646 49.373 ;
     RECT  18.504 49.373 22.662 49.421 ;
     RECT  2.415 22.235 2.697 49.427 ;
     RECT  7.815 49.373 17.73 49.427 ;
     RECT  8.676 49.427 17.73 49.469 ;
     RECT  18.504 49.421 19.386 49.469 ;
     RECT  20.124 49.421 22.662 49.469 ;
     RECT  23.688 49.373 47.646 49.469 ;
     RECT  8.676 49.469 17.658 49.517 ;
     RECT  18.615 49.469 19.278 49.517 ;
     RECT  20.124 49.469 22.23 49.517 ;
     RECT  23.688 49.469 42.102 49.517 ;
     RECT  32.688 49.517 42.102 49.541 ;
     RECT  32.688 49.541 37.998 49.565 ;
     RECT  42.84 49.469 44.622 49.565 ;
     RECT  45.36 49.469 46.746 49.565 ;
     RECT  9.36 49.517 10.818 49.577 ;
     RECT  11.952 49.517 14.346 49.577 ;
     RECT  15.192 49.517 16.398 49.577 ;
     RECT  17.352 49.517 17.658 49.577 ;
     RECT  20.592 49.517 22.23 49.577 ;
     RECT  24.015 49.517 31.914 49.577 ;
     RECT  32.688 49.565 33.066 49.577 ;
     RECT  34.524 49.565 35.622 49.577 ;
     RECT  37.98 49.565 37.998 49.577 ;
     RECT  38.736 49.541 42.102 49.577 ;
     RECT  42.84 49.565 43.686 49.577 ;
     RECT  44.46 49.565 44.622 49.577 ;
     RECT  45.468 49.565 46.746 49.577 ;
     RECT  2.415 49.427 2.505 49.697 ;
     RECT  7.815 49.427 7.905 49.697 ;
     RECT  12.492 49.577 13.626 49.697 ;
     RECT  18.615 49.517 18.954 49.697 ;
     RECT  24.015 49.577 24.354 49.697 ;
     RECT  18.756 49.697 18.954 49.805 ;
     RECT  24.156 49.697 24.354 49.805 ;
     RECT  29.376 49.577 29.754 49.805 ;
     RECT  34.776 49.577 35.154 49.805 ;
     RECT  40.176 49.577 40.482 49.805 ;
     RECT  45.468 49.577 45.954 49.805 ;
     RECT  13.356 49.697 13.626 49.853 ;
     RECT  18.756 49.805 18.774 49.853 ;
     RECT  24.156 49.805 24.174 49.853 ;
     RECT  29.376 49.805 29.574 49.853 ;
     RECT  34.776 49.805 34.794 49.853 ;
     RECT  40.176 49.805 40.374 49.853 ;
     RECT  26.208 49.577 26.73 50.189 ;
     RECT  41.94 49.577 42.102 50.189 ;
     RECT  32.868 49.577 32.886 50.717 ;
     RECT  41.94 50.189 41.958 50.717 ;
     RECT  12.492 49.697 12.51 50.765 ;
     RECT  17.64 49.577 17.658 50.765 ;
     RECT  26.712 50.189 26.73 50.765 ;
     RECT  38.736 49.577 38.754 50.765 ;
     RECT  43.272 49.577 43.686 50.765 ;
    LAYER M4 ;
     RECT  0.084 4.032 0.137 4.056 ;
     RECT  0.06 4.056 0.137 4.176 ;
     RECT  0.084 4.176 0.137 4.2 ;
     RECT  0.06 4.2 0.137 4.32 ;
     RECT  0.084 4.32 0.137 4.344 ;
     RECT  0.06 4.344 0.137 4.464 ;
     RECT  0.084 4.464 0.137 4.488 ;
     RECT  0.06 4.488 0.137 4.608 ;
     RECT  0.084 4.608 0.137 4.632 ;
     RECT  0.06 4.632 0.137 4.752 ;
     RECT  0.084 4.752 0.137 4.776 ;
     RECT  0.06 4.776 0.137 4.896 ;
     RECT  0.084 4.896 0.137 4.92 ;
     RECT  0.06 4.92 0.137 5.04 ;
     RECT  0.084 5.04 0.137 5.064 ;
     RECT  0.06 5.064 0.137 5.184 ;
     RECT  0.084 5.184 0.137 5.208 ;
     RECT  0.06 5.208 0.137 5.328 ;
     RECT  0.084 5.328 0.137 5.352 ;
     RECT  0.06 5.352 0.137 5.472 ;
     RECT  0.084 5.472 0.137 5.496 ;
     RECT  0.06 5.496 0.137 5.616 ;
     RECT  0.084 5.616 0.137 5.64 ;
     RECT  0.06 5.64 0.137 5.76 ;
     RECT  0.084 5.76 0.137 5.784 ;
     RECT  0.06 5.784 0.137 5.904 ;
     RECT  0.084 5.904 0.137 5.928 ;
     RECT  0.06 5.928 0.137 6.048 ;
     RECT  0.084 6.048 0.137 6.072 ;
     RECT  0.06 6.072 0.137 6.192 ;
     RECT  0.084 6.192 0.137 6.216 ;
     RECT  0.06 6.216 0.137 6.336 ;
     RECT  0.084 6.336 0.137 6.36 ;
     RECT  0.06 6.36 0.137 6.48 ;
     RECT  0.084 6.48 0.137 6.504 ;
     RECT  0.06 6.504 0.137 6.624 ;
     RECT  0.084 6.624 0.137 6.648 ;
     RECT  0.06 6.648 0.137 6.768 ;
     RECT  0.084 6.768 0.137 6.792 ;
     RECT  0.06 6.792 0.137 6.912 ;
     RECT  0.084 6.912 0.137 6.936 ;
     RECT  0.06 6.936 0.137 7.056 ;
     RECT  0.084 7.056 0.137 7.08 ;
     RECT  0.06 7.08 0.137 7.2 ;
     RECT  0.084 7.2 0.137 7.224 ;
     RECT  0.06 7.224 0.137 7.344 ;
     RECT  0.084 7.344 0.137 7.368 ;
     RECT  0.06 7.368 0.137 7.488 ;
     RECT  0.084 7.488 0.137 7.512 ;
     RECT  0.06 7.512 0.137 7.632 ;
     RECT  0.084 7.632 0.137 7.656 ;
     RECT  0.06 7.656 0.137 7.776 ;
     RECT  0.084 7.776 0.137 7.8 ;
     RECT  0.06 7.8 0.137 7.92 ;
     RECT  0.084 7.92 0.137 7.944 ;
     RECT  0.06 7.944 0.137 8.064 ;
     RECT  0.084 8.064 0.137 8.088 ;
     RECT  0.06 8.088 0.137 8.208 ;
     RECT  0.084 8.208 0.137 8.232 ;
     RECT  0.06 8.232 0.137 8.352 ;
     RECT  0.084 8.352 0.137 8.376 ;
     RECT  0.06 8.376 0.137 8.496 ;
     RECT  0.084 8.496 0.137 8.52 ;
     RECT  0.06 8.52 0.137 8.64 ;
     RECT  0.084 8.64 0.137 8.664 ;
     RECT  0.06 8.664 0.137 8.784 ;
     RECT  0.084 8.784 0.137 8.808 ;
     RECT  0.06 8.808 0.137 8.928 ;
     RECT  0.084 8.928 0.137 8.952 ;
     RECT  0.06 8.952 0.137 9.072 ;
     RECT  0.084 9.072 0.137 9.096 ;
     RECT  0.06 9.096 0.137 9.216 ;
     RECT  0.084 9.216 0.137 9.24 ;
     RECT  0.06 9.24 0.137 9.36 ;
     RECT  0.084 9.36 0.137 9.384 ;
     RECT  0.06 9.384 0.137 9.504 ;
     RECT  0.084 9.504 0.137 9.528 ;
     RECT  0.06 9.528 0.137 9.648 ;
     RECT  0.084 9.648 0.137 9.672 ;
     RECT  0.06 9.672 0.137 9.792 ;
     RECT  0.084 9.792 0.137 9.816 ;
     RECT  0.06 9.816 0.137 9.936 ;
     RECT  0.084 9.936 0.137 9.96 ;
     RECT  0.06 9.96 0.137 10.08 ;
     RECT  0.084 10.08 0.137 10.104 ;
     RECT  0.06 10.104 0.137 10.224 ;
     RECT  0.084 10.224 0.137 10.248 ;
     RECT  0.06 10.248 0.137 10.368 ;
     RECT  0.084 10.368 0.137 10.392 ;
     RECT  0.06 10.392 0.137 10.512 ;
     RECT  0.084 10.512 0.137 10.536 ;
     RECT  0.06 10.536 0.137 10.656 ;
     RECT  0.084 10.656 0.137 10.68 ;
     RECT  0.06 10.68 0.137 10.8 ;
     RECT  0.084 10.8 0.137 10.824 ;
     RECT  0.06 10.824 0.137 10.944 ;
     RECT  0.084 10.944 0.137 10.968 ;
     RECT  0.06 10.968 0.137 11.088 ;
     RECT  0.084 11.088 0.137 11.112 ;
     RECT  0.06 11.112 0.137 11.232 ;
     RECT  0.084 11.232 0.137 11.256 ;
     RECT  0.06 11.256 0.137 11.376 ;
     RECT  0.084 11.376 0.137 11.4 ;
     RECT  0.06 11.4 0.137 11.52 ;
     RECT  0.084 11.52 0.137 11.544 ;
     RECT  0.06 11.544 0.137 11.664 ;
     RECT  0.084 11.664 0.137 11.688 ;
     RECT  0.06 11.688 0.137 11.808 ;
     RECT  0.084 11.808 0.137 11.832 ;
     RECT  0.06 11.832 0.137 11.952 ;
     RECT  0.084 11.952 0.137 11.976 ;
     RECT  0.06 11.976 0.137 12.096 ;
     RECT  0.084 12.096 0.137 12.12 ;
     RECT  0.06 12.12 0.137 12.24 ;
     RECT  0.084 12.24 0.137 12.264 ;
     RECT  0.06 12.264 0.137 12.384 ;
     RECT  0.084 12.384 0.137 12.408 ;
     RECT  0.06 12.408 0.137 12.528 ;
     RECT  0.084 12.528 0.137 12.552 ;
     RECT  0.06 12.552 0.137 12.672 ;
     RECT  0.084 12.672 0.137 12.696 ;
     RECT  0.06 12.696 0.137 12.816 ;
     RECT  0.084 12.816 0.137 12.84 ;
     RECT  0.06 12.84 0.137 12.96 ;
     RECT  0.084 12.96 0.137 12.984 ;
     RECT  0.06 12.984 0.137 13.104 ;
     RECT  0.084 13.104 0.137 13.128 ;
     RECT  0.06 13.128 0.137 13.248 ;
     RECT  0.084 13.248 0.137 13.272 ;
     RECT  0.06 13.272 0.137 13.392 ;
     RECT  0.084 13.392 0.137 13.416 ;
     RECT  0.06 13.416 0.137 13.536 ;
     RECT  0.084 13.536 0.137 13.56 ;
     RECT  0.06 13.56 0.137 13.68 ;
     RECT  0.084 13.68 0.137 13.704 ;
     RECT  0.06 13.704 0.137 13.824 ;
     RECT  0.084 13.824 0.137 13.848 ;
     RECT  0.06 13.848 0.137 13.968 ;
     RECT  0.084 13.968 0.137 13.992 ;
     RECT  0.06 13.992 0.137 14.112 ;
     RECT  0.084 14.112 0.137 14.136 ;
     RECT  0.06 14.136 0.137 14.256 ;
     RECT  0.084 14.256 0.137 14.28 ;
     RECT  0.06 14.28 0.137 14.4 ;
     RECT  0.084 14.4 0.137 14.424 ;
     RECT  0.06 14.424 0.137 14.544 ;
     RECT  0.084 14.544 0.137 14.568 ;
     RECT  0.06 14.568 0.137 14.688 ;
     RECT  0.084 14.688 0.137 14.712 ;
     RECT  0.06 14.712 0.137 14.832 ;
     RECT  0.084 14.832 0.137 14.856 ;
     RECT  0.06 14.856 0.137 14.976 ;
     RECT  0.084 14.976 0.137 15 ;
     RECT  0.06 15 0.137 15.12 ;
     RECT  0.084 15.12 0.137 15.144 ;
     RECT  0.06 15.144 0.137 15.264 ;
     RECT  0.084 15.264 0.137 15.288 ;
     RECT  0.06 15.288 0.137 15.408 ;
     RECT  0.084 15.408 0.137 15.432 ;
     RECT  0.06 15.432 0.137 15.552 ;
     RECT  0.084 15.552 0.137 15.576 ;
     RECT  0.06 15.576 0.137 15.696 ;
     RECT  0.084 15.696 0.137 15.72 ;
     RECT  0.06 15.72 0.137 15.84 ;
     RECT  0.084 15.84 0.137 15.864 ;
     RECT  0.06 15.864 0.137 15.984 ;
     RECT  0.084 15.984 0.137 16.008 ;
     RECT  0.06 16.008 0.137 16.128 ;
     RECT  0.084 16.128 0.137 16.152 ;
     RECT  0.06 16.152 0.137 16.272 ;
     RECT  0.084 16.272 0.137 16.296 ;
     RECT  0.06 16.296 0.137 16.416 ;
     RECT  0.084 16.416 0.137 16.44 ;
     RECT  0.06 16.44 0.137 16.56 ;
     RECT  0.084 16.56 0.137 16.584 ;
     RECT  0.06 16.584 0.137 16.704 ;
     RECT  0.084 16.704 0.137 16.728 ;
     RECT  0.06 16.728 0.137 16.848 ;
     RECT  0.084 16.848 0.137 16.872 ;
     RECT  0.06 16.872 0.137 16.992 ;
     RECT  0.084 16.992 0.137 17.016 ;
     RECT  0.06 17.016 0.137 17.136 ;
     RECT  0.084 17.136 0.137 17.16 ;
     RECT  0.06 17.16 0.137 17.28 ;
     RECT  0.084 17.28 0.137 17.304 ;
     RECT  0.06 17.304 0.137 17.424 ;
     RECT  0.084 17.424 0.137 17.448 ;
     RECT  0.06 17.448 0.137 17.568 ;
     RECT  0.084 17.568 0.137 17.592 ;
     RECT  0.06 17.592 0.137 17.712 ;
     RECT  0.084 17.712 0.137 17.736 ;
     RECT  0.06 17.736 0.137 17.856 ;
     RECT  0.084 17.856 0.137 17.88 ;
     RECT  0.06 17.88 0.137 18 ;
     RECT  0.084 18 0.137 18.024 ;
     RECT  0.06 18.024 0.137 18.144 ;
     RECT  0.084 18.144 0.137 18.168 ;
     RECT  0.06 18.168 0.137 18.288 ;
     RECT  0.084 18.288 0.137 18.312 ;
     RECT  0.06 18.312 0.137 18.432 ;
     RECT  0.084 18.432 0.137 18.456 ;
     RECT  0.06 18.456 0.137 18.576 ;
     RECT  0.084 18.576 0.137 18.6 ;
     RECT  0.06 18.6 0.137 18.72 ;
     RECT  0.084 18.72 0.137 18.744 ;
     RECT  0.06 18.744 0.137 18.864 ;
     RECT  0.084 18.864 0.137 18.888 ;
     RECT  0.06 18.888 0.137 19.008 ;
     RECT  0.084 19.008 0.137 19.032 ;
     RECT  0.06 19.032 0.137 19.152 ;
     RECT  0.084 19.152 0.137 19.176 ;
     RECT  0.06 19.176 0.137 19.296 ;
     RECT  0.084 19.296 0.137 19.32 ;
     RECT  0.06 19.32 0.137 19.44 ;
     RECT  0.084 19.44 0.137 19.464 ;
     RECT  0.06 19.464 0.137 19.584 ;
     RECT  0.084 19.584 0.137 19.608 ;
     RECT  0.06 19.608 0.137 19.728 ;
     RECT  0.084 19.728 0.137 19.752 ;
     RECT  0.06 19.752 0.137 19.872 ;
     RECT  0.084 19.872 0.137 19.896 ;
     RECT  0.06 19.896 0.137 20.016 ;
     RECT  0.084 20.016 0.137 20.04 ;
     RECT  0.06 20.04 0.137 20.16 ;
     RECT  0.084 20.16 0.137 20.184 ;
     RECT  0.06 20.184 0.137 20.304 ;
     RECT  0.084 20.304 0.137 20.328 ;
     RECT  0.06 20.328 0.137 20.448 ;
     RECT  0.084 20.448 0.137 20.472 ;
     RECT  0.06 20.472 0.137 20.592 ;
     RECT  0.084 20.592 0.137 20.616 ;
     RECT  0.06 20.616 0.137 20.736 ;
     RECT  0.084 20.736 0.137 20.76 ;
     RECT  0.06 20.76 0.137 20.88 ;
     RECT  0.084 20.88 0.137 20.904 ;
     RECT  0.06 20.904 0.137 21.024 ;
     RECT  0.084 21.024 0.137 21.048 ;
     RECT  0.06 21.048 0.137 21.168 ;
     RECT  0.084 21.168 0.137 21.192 ;
     RECT  0.06 21.192 0.137 21.312 ;
     RECT  0.084 21.312 0.137 21.336 ;
     RECT  0.06 21.336 0.137 21.456 ;
     RECT  0.084 21.456 0.137 21.48 ;
     RECT  0.06 21.48 0.137 21.6 ;
     RECT  0.084 21.6 0.137 21.624 ;
     RECT  0.06 21.624 0.137 21.744 ;
     RECT  0.084 21.744 0.137 21.768 ;
     RECT  0.06 21.768 0.137 21.888 ;
     RECT  0.084 21.888 0.137 21.912 ;
     RECT  0.06 21.912 0.137 22.032 ;
     RECT  0.084 22.032 0.137 22.056 ;
     RECT  0.06 22.056 0.137 22.176 ;
     RECT  0.084 22.176 0.137 22.2 ;
     RECT  0.137 4.176 2.365 22.2 ;
     RECT  2.365 3.6 2.408 22.2 ;
     RECT  0.181 25.776 2.408 25.8 ;
     RECT  2.408 2.148 2.512 49.692 ;
     RECT  2.512 2.418 2.704 49.422 ;
     RECT  2.704 6.768 2.765 14.712 ;
     RECT  2.765 13.008 3.449 14.712 ;
     RECT  2.704 3.6 3.697 5.496 ;
     RECT  3.449 13.632 3.769 14.712 ;
     RECT  2.704 15.744 3.769 22.2 ;
     RECT  2.765 6.768 3.913 11.4 ;
     RECT  3.913 6.528 3.949 11.4 ;
     RECT  3.949 6.528 3.985 11.928 ;
     RECT  3.985 6.528 4.061 12.216 ;
     RECT  3.697 3.408 4.309 5.496 ;
     RECT  4.061 6.528 4.309 8.76 ;
     RECT  4.309 3.408 4.493 8.76 ;
     RECT  3.769 13.632 4.525 22.2 ;
     RECT  4.525 13.392 4.529 22.2 ;
     RECT  4.529 14.736 4.673 22.2 ;
     RECT  4.529 13.392 4.889 13.656 ;
     RECT  4.673 14.736 5.429 22.104 ;
     RECT  5.429 15.12 5.501 22.104 ;
     RECT  5.501 15.168 5.609 22.104 ;
     RECT  4.061 9.792 5.641 12.216 ;
     RECT  4.493 3.408 5.785 3.432 ;
     RECT  4.493 4.464 5.785 8.76 ;
     RECT  5.641 9.792 5.785 12.792 ;
     RECT  5.785 3.408 5.789 12.792 ;
     RECT  5.609 15.168 5.789 21.768 ;
     RECT  5.789 3.408 5.825 8.856 ;
     RECT  5.825 3.6 5.933 8.856 ;
     RECT  5.789 15.168 6.077 21.672 ;
     RECT  5.933 7.248 6.113 8.856 ;
     RECT  6.077 15.408 6.221 21.672 ;
     RECT  6.221 21.264 6.293 21.672 ;
     RECT  6.293 21.264 6.329 21.384 ;
     RECT  6.221 15.408 6.365 20.04 ;
     RECT  5.789 9.936 6.397 12.792 ;
     RECT  5.533 14.112 6.397 14.136 ;
     RECT  6.397 9.936 6.793 14.136 ;
     RECT  6.793 9.936 6.865 14.232 ;
     RECT  5.933 3.6 7.153 6.168 ;
     RECT  6.365 15.408 7.297 19.896 ;
     RECT  7.297 15.36 7.585 19.896 ;
     RECT  6.865 9.888 7.765 14.232 ;
     RECT  7.585 15.264 7.765 19.896 ;
     RECT  7.153 3.408 7.808 6.168 ;
     RECT  6.113 8.16 7.808 8.856 ;
     RECT  7.765 9.888 7.808 19.896 ;
     RECT  6.329 21.36 7.808 21.384 ;
     RECT  2.704 25.776 7.808 25.8 ;
     RECT  7.808 2.148 7.912 49.692 ;
     RECT  7.912 2.418 8.104 49.512 ;
     RECT  8.104 4.992 8.273 6.84 ;
     RECT  8.104 19.296 8.281 19.416 ;
     RECT  8.273 6.144 8.417 6.84 ;
     RECT  8.281 19.296 8.417 19.32 ;
     RECT  8.104 9.6 8.668 16.392 ;
     RECT  8.273 4.992 8.705 5.016 ;
     RECT  8.668 9.888 8.813 16.392 ;
     RECT  8.813 9.888 9.065 14.52 ;
     RECT  9.065 14.112 9.137 14.52 ;
     RECT  8.104 17.616 9.137 18.216 ;
     RECT  8.104 49.008 9.205 49.512 ;
     RECT  9.137 14.112 9.209 14.376 ;
     RECT  9.205 49.008 9.349 49.56 ;
     RECT  8.813 15.888 9.385 16.392 ;
     RECT  9.209 14.112 9.461 14.136 ;
     RECT  8.104 3.408 9.493 3.432 ;
     RECT  9.065 9.888 9.533 12.6 ;
     RECT  9.493 3.312 9.565 3.432 ;
     RECT  9.644 34.752 9.685 34.776 ;
     RECT  9.533 10.128 9.713 12.6 ;
     RECT  9.565 3.312 9.74 4.296 ;
     RECT  9.685 34.416 9.781 34.776 ;
     RECT  9.74 3.312 9.785 4.536 ;
     RECT  9.781 34.224 9.817 34.776 ;
     RECT  9.785 3.984 9.827 4.536 ;
     RECT  8.417 6.144 9.884 6.168 ;
     RECT  9.673 0.528 9.925 0.552 ;
     RECT  9.137 18.192 9.929 18.216 ;
     RECT  8.104 47.904 10.001 47.928 ;
     RECT  9.385 15.888 10.109 16.488 ;
     RECT  9.817 34.224 10.109 35.352 ;
     RECT  9.884 5.328 10.253 6.168 ;
     RECT  10.109 34.416 10.253 35.352 ;
     RECT  9.713 10.416 10.259 12.6 ;
     RECT  9.889 1.728 10.285 1.752 ;
     RECT  10.259 12.528 10.325 12.6 ;
     RECT  10.109 16.368 10.325 16.488 ;
     RECT  9.827 3.984 10.433 4.008 ;
     RECT  10.259 10.416 10.541 11.4 ;
     RECT  10.325 16.368 10.541 16.392 ;
     RECT  9.925 0.48 10.547 0.552 ;
     RECT  10.213 8.064 10.573 8.088 ;
     RECT  10.285 1.68 10.604 1.752 ;
     RECT  10.604 1.104 10.691 1.752 ;
     RECT  10.253 6.144 10.748 6.168 ;
     RECT  9.349 48.912 10.825 49.56 ;
     RECT  10.748 6.144 10.835 6.744 ;
     RECT  10.253 35.328 10.835 35.352 ;
     RECT  10.573 8.064 10.865 8.568 ;
     RECT  10.541 10.416 10.865 11.304 ;
     RECT  10.691 1.728 10.872 1.752 ;
     RECT  10.872 1.728 10.873 1.8 ;
     RECT  10.873 1.776 10.933 1.8 ;
     RECT  10.865 10.416 10.969 10.968 ;
     RECT  10.969 9.792 11.009 10.968 ;
     RECT  10.865 8.448 11.075 8.568 ;
     RECT  11.009 9.792 11.075 10.44 ;
     RECT  10.325 12.576 11.189 12.6 ;
     RECT  11.365 4.56 11.555 5.16 ;
     RECT  11.213 0.096 11.612 0.12 ;
     RECT  10.933 1.776 11.653 2.328 ;
     RECT  11.612 0.096 11.699 0.552 ;
     RECT  11.075 8.448 11.699 8.472 ;
     RECT  11.581 13.488 11.729 13.512 ;
     RECT  11.555 5.136 11.893 5.16 ;
     RECT  10.835 6.144 11.893 6.264 ;
     RECT  11.653 1.776 11.941 3.144 ;
     RECT  10.825 48.768 11.981 49.56 ;
     RECT  11.981 48.768 12.121 49.512 ;
     RECT  11.941 1.728 12.332 3.144 ;
     RECT  12.332 1.104 12.481 3.144 ;
     RECT  12.476 50.736 12.563 50.76 ;
     RECT  11.893 5.136 13.045 6.264 ;
     RECT  11.699 0.096 13.093 0.12 ;
     RECT  12.481 1.104 13.093 3.432 ;
     RECT  13.093 0.096 13.097 3.432 ;
     RECT  13.097 2.148 13.208 3.432 ;
     RECT  13.045 4.464 13.208 6.264 ;
     RECT  12.589 7.968 13.208 7.992 ;
     RECT  8.104 25.776 13.208 25.8 ;
     RECT  12.121 48.72 13.208 49.512 ;
     RECT  13.208 2.148 13.237 49.692 ;
     RECT  13.237 2.148 13.504 49.848 ;
     RECT  13.504 5.184 13.565 6.36 ;
     RECT  13.504 48.768 13.637 49.848 ;
     RECT  13.565 5.808 13.667 6.36 ;
     RECT  13.097 0.096 13.925 1.176 ;
     RECT  13.637 48.768 13.955 49.56 ;
     RECT  13.504 2.148 14.101 2.904 ;
     RECT  14.101 1.728 14.213 2.904 ;
     RECT  13.504 46.656 14.213 46.776 ;
     RECT  14.213 46.752 14.677 46.776 ;
     RECT  14.213 2.16 14.915 2.808 ;
     RECT  13.925 0.096 14.933 0.6 ;
     RECT  13.667 5.856 14.965 6.36 ;
     RECT  14.915 2.16 14.969 2.76 ;
     RECT  14.933 0.144 15.005 0.6 ;
     RECT  14.965 5.088 15.109 6.36 ;
     RECT  14.969 2.736 15.221 2.76 ;
     RECT  14.677 46.752 15.325 47.304 ;
     RECT  15.005 0.528 15.397 0.6 ;
     RECT  15.253 1.728 15.397 1.752 ;
     RECT  15.397 0.528 15.581 1.752 ;
     RECT  15.581 0.528 15.653 0.6 ;
     RECT  15.109 5.088 15.725 6.84 ;
     RECT  13.955 49.008 15.761 49.56 ;
     RECT  15.581 1.728 15.869 1.752 ;
     RECT  15.577 3.936 15.973 3.96 ;
     RECT  15.725 5.568 15.977 6.84 ;
     RECT  15.973 2.88 16.049 3.96 ;
     RECT  15.325 46.752 16.049 47.88 ;
     RECT  15.653 0.528 16.117 0.552 ;
     RECT  16.049 2.88 16.22 3.72 ;
     RECT  16.22 2.256 16.307 3.72 ;
     RECT  15.977 5.568 16.409 6.744 ;
     RECT  16.409 5.568 16.481 6.072 ;
     RECT  16.049 47.856 16.625 47.88 ;
     RECT  16.481 5.568 16.729 5.88 ;
     RECT  17.017 7.968 17.101 7.992 ;
     RECT  15.761 49.008 17.125 49.512 ;
     RECT  16.909 12.816 17.269 12.84 ;
     RECT  17.269 12.528 17.353 12.84 ;
     RECT  16.837 1.728 17.497 1.752 ;
     RECT  16.117 0.096 17.549 0.552 ;
     RECT  16.049 46.752 17.557 46.776 ;
     RECT  16.307 2.784 17.561 3.72 ;
     RECT  16.729 5.04 17.605 5.88 ;
     RECT  17.605 4.848 17.693 5.88 ;
     RECT  17.561 2.88 17.737 3.72 ;
     RECT  17.693 4.848 17.737 6.312 ;
     RECT  17.737 2.88 17.773 6.312 ;
     RECT  17.629 50.736 17.891 50.76 ;
     RECT  17.557 46.752 18.169 46.872 ;
     RECT  17.125 49.008 18.385 49.56 ;
     RECT  17.549 0.096 18.497 0.6 ;
     RECT  18.385 48.672 18.565 49.56 ;
     RECT  17.773 2.88 18.608 6.888 ;
     RECT  17.653 8.544 18.608 8.568 ;
     RECT  17.353 12.816 18.608 12.84 ;
     RECT  13.504 25.776 18.608 25.8 ;
     RECT  18.169 46.176 18.608 46.872 ;
     RECT  18.565 48.672 18.608 49.848 ;
     RECT  18.608 2.148 18.701 49.848 ;
     RECT  18.469 51.648 18.755 51.672 ;
     RECT  18.701 1.728 18.785 49.848 ;
     RECT  18.785 1.728 18.904 49.8 ;
     RECT  18.904 49.008 18.965 49.8 ;
     RECT  18.904 5.712 19.117 6.792 ;
     RECT  18.497 0.144 19.181 0.6 ;
     RECT  18.904 1.728 19.217 4.68 ;
     RECT  19.117 6.288 19.225 6.792 ;
     RECT  19.217 3.984 19.397 4.68 ;
     RECT  19.225 6.768 19.469 6.792 ;
     RECT  19.217 1.728 19.907 2.328 ;
     RECT  19.717 0.096 20.149 0.12 ;
     RECT  20.149 0.096 20.261 0.6 ;
     RECT  18.965 49.008 20.54 49.512 ;
     RECT  19.907 1.728 21.005 1.752 ;
     RECT  21.005 1.728 21.089 1.8 ;
     RECT  18.904 46.848 21.109 46.872 ;
     RECT  21.109 46.848 21.155 47.064 ;
     RECT  20.54 49.008 21.193 49.56 ;
     RECT  20.261 0.096 21.203 0.552 ;
     RECT  20.437 2.784 21.269 2.808 ;
     RECT  19.397 4.656 21.845 4.68 ;
     RECT  21.733 6.816 21.845 6.84 ;
     RECT  21.877 2.88 21.989 2.904 ;
     RECT  21.661 42.72 22.093 42.744 ;
     RECT  22.093 42.432 22.133 42.744 ;
     RECT  21.193 48.48 22.241 49.56 ;
     RECT  22.241 48.48 22.252 49.032 ;
     RECT  21.089 1.728 22.381 1.752 ;
     RECT  21.203 0.096 22.564 0.168 ;
     RECT  22.564 0.096 22.673 0.216 ;
     RECT  22.133 42.432 22.777 42.456 ;
     RECT  22.381 1.728 23.029 2.328 ;
     RECT  22.669 3.408 23.029 3.432 ;
     RECT  22.252 48.48 23.461 48.504 ;
     RECT  23.461 48.48 23.605 49.368 ;
     RECT  22.673 0.096 23.708 0.168 ;
     RECT  23.708 0.096 23.795 0.552 ;
     RECT  23.209 6 23.929 6.024 ;
     RECT  23.029 1.728 24.008 3.432 ;
     RECT  23.929 5.856 24.008 6.024 ;
     RECT  23.929 7.968 24.008 7.992 ;
     RECT  18.904 12.816 24.008 12.84 ;
     RECT  18.904 25.776 24.008 25.8 ;
     RECT  22.777 42.192 24.008 42.456 ;
     RECT  21.155 47.04 24.008 47.064 ;
     RECT  23.605 48.48 24.008 49.512 ;
     RECT  24.008 1.728 24.037 49.692 ;
     RECT  24.037 1.728 24.185 49.848 ;
     RECT  24.185 1.728 24.304 49.8 ;
     RECT  24.304 49.008 24.409 49.8 ;
     RECT  24.304 1.728 24.419 2.616 ;
     RECT  24.304 7.968 24.419 7.992 ;
     RECT  23.795 0.096 24.437 0.216 ;
     RECT  24.419 1.728 24.905 2.376 ;
     RECT  24.905 2.064 25.049 2.376 ;
     RECT  24.304 25.776 25.265 25.8 ;
     RECT  25.049 2.304 25.337 2.376 ;
     RECT  25.337 2.352 25.445 2.376 ;
     RECT  25.477 2.736 25.513 2.76 ;
     RECT  24.304 46.944 25.513 47.064 ;
     RECT  25.513 2.736 25.571 2.856 ;
     RECT  25.571 2.832 25.621 2.856 ;
     RECT  25.621 2.832 25.625 2.904 ;
     RECT  24.409 49.008 25.667 49.56 ;
     RECT  25.513 46.752 25.981 47.064 ;
     RECT  24.437 0.096 26.053 0.168 ;
     RECT  24.304 5.424 26.093 5.736 ;
     RECT  25.625 2.88 26.125 2.904 ;
     RECT  25.525 4.368 26.125 4.392 ;
     RECT  25.667 49.344 26.156 49.56 ;
     RECT  26.125 2.88 26.197 4.392 ;
     RECT  26.156 49.344 26.243 50.184 ;
     RECT  26.053 0.096 26.341 0.216 ;
     RECT  26.341 0.096 26.413 1.08 ;
     RECT  26.156 25.968 26.483 25.992 ;
     RECT  26.197 2.88 26.597 4.584 ;
     RECT  25.981 46.752 26.629 47.448 ;
     RECT  26.243 49.344 26.629 49.56 ;
     RECT  26.413 0.096 26.675 1.128 ;
     RECT  26.684 40.992 26.771 41.016 ;
     RECT  26.597 2.88 26.773 4.392 ;
     RECT  26.701 39.888 26.785 39.912 ;
     RECT  26.773 2.16 26.813 4.392 ;
     RECT  26.629 46.752 26.813 49.56 ;
     RECT  26.701 50.736 26.819 50.76 ;
     RECT  26.813 2.16 26.917 2.904 ;
     RECT  26.125 6.24 26.993 6.264 ;
     RECT  26.917 7.92 27.133 7.944 ;
     RECT  26.813 46.848 27.209 49.56 ;
     RECT  26.917 1.728 27.461 2.904 ;
     RECT  26.675 0.096 27.637 0.168 ;
     RECT  27.133 6.624 27.709 6.648 ;
     RECT  27.461 2.88 27.749 2.904 ;
     RECT  27.637 0.096 27.857 0.6 ;
     RECT  27.209 46.848 27.893 47.352 ;
     RECT  27.857 0.096 28.253 0.168 ;
     RECT  27.709 6.624 28.321 6.84 ;
     RECT  26.813 3.888 28.429 4.392 ;
     RECT  27.461 1.728 28.433 1.848 ;
     RECT  28.433 1.776 28.685 1.848 ;
     RECT  28.321 6.624 29.077 6.888 ;
     RECT  27.133 7.92 29.077 7.992 ;
     RECT  28.429 3.408 29.269 4.392 ;
     RECT  27.209 49.008 29.324 49.56 ;
     RECT  29.269 3.408 29.401 4.488 ;
     RECT  29.077 5.472 29.401 7.992 ;
     RECT  29.401 3.408 29.408 7.992 ;
     RECT  24.304 12.816 29.408 12.84 ;
     RECT  26.437 35.472 29.408 35.496 ;
     RECT  24.304 42.192 29.408 42.456 ;
     RECT  27.893 46.848 29.408 46.872 ;
     RECT  28.393 47.904 29.408 47.928 ;
     RECT  29.324 49.008 29.408 49.848 ;
     RECT  28.253 0.144 29.501 0.168 ;
     RECT  29.408 2.148 29.596 49.848 ;
     RECT  29.596 2.148 29.704 49.8 ;
     RECT  29.501 0.144 29.737 0.6 ;
     RECT  29.704 49.008 29.765 49.8 ;
     RECT  29.737 0.144 29.789 0.264 ;
     RECT  29.704 3.216 29.801 3.432 ;
     RECT  30.085 1.728 30.169 1.752 ;
     RECT  29.704 46.416 30.371 47.496 ;
     RECT  29.789 0.096 30.593 0.264 ;
     RECT  30.371 47.472 30.665 47.496 ;
     RECT  29.801 3.216 30.805 3.336 ;
     RECT  29.704 4.464 30.917 7.8 ;
     RECT  30.805 2.736 30.953 3.336 ;
     RECT  29.765 49.008 31.093 49.56 ;
     RECT  31.237 1.728 31.348 1.752 ;
     RECT  30.953 2.736 31.348 2.76 ;
     RECT  30.593 0.096 31.669 0.12 ;
     RECT  30.371 46.416 31.813 46.44 ;
     RECT  29.704 12.816 31.861 12.84 ;
     RECT  30.917 4.464 31.907 5.16 ;
     RECT  31.861 12.432 31.925 12.84 ;
     RECT  31.925 12.432 31.948 12.552 ;
     RECT  31.907 4.512 32.101 5.16 ;
     RECT  30.917 6.576 32.101 7.8 ;
     RECT  32.101 4.512 32.105 7.8 ;
     RECT  32.105 4.656 32.177 7.8 ;
     RECT  31.093 48.912 32.249 49.56 ;
     RECT  32.249 49.008 32.501 49.56 ;
     RECT  31.348 1.728 32.537 2.76 ;
     RECT  31.948 12.528 32.537 12.552 ;
     RECT  31.813 46.416 32.753 47.352 ;
     RECT  32.501 49.056 33.077 49.56 ;
     RECT  32.857 50.688 33.155 50.712 ;
     RECT  32.537 2.736 33.185 2.76 ;
     RECT  32.177 4.656 33.505 7.752 ;
     RECT  32.537 1.728 33.685 1.752 ;
     RECT  33.077 49.488 34.109 49.56 ;
     RECT  32.753 46.416 34.261 46.68 ;
     RECT  33.685 1.728 34.297 2.52 ;
     RECT  31.669 0.096 34.333 0.168 ;
     RECT  34.261 46.416 34.357 47.352 ;
     RECT  34.333 0.096 34.549 0.552 ;
     RECT  34.109 49.392 34.585 49.56 ;
     RECT  34.585 49.056 34.765 49.56 ;
     RECT  34.765 49.056 34.801 49.848 ;
     RECT  34.297 1.728 34.808 2.904 ;
     RECT  33.505 4.656 34.808 7.944 ;
     RECT  34.657 22.752 34.808 22.776 ;
     RECT  29.704 35.472 34.808 35.496 ;
     RECT  29.704 42.192 34.808 42.456 ;
     RECT  34.357 46.128 34.808 47.352 ;
     RECT  34.801 48.768 34.808 49.848 ;
     RECT  34.808 1.728 34.883 49.848 ;
     RECT  34.883 1.728 35.104 49.8 ;
     RECT  35.104 48.192 35.209 49.8 ;
     RECT  34.549 0.096 35.228 0.6 ;
     RECT  35.104 1.728 35.228 1.752 ;
     RECT  35.228 0.096 35.267 1.752 ;
     RECT  35.104 2.784 35.273 7.944 ;
     RECT  35.273 2.784 35.309 7.752 ;
     RECT  35.309 6.048 35.777 7.752 ;
     RECT  35.267 1.104 35.813 1.752 ;
     RECT  35.104 45.696 36.029 47.16 ;
     RECT  35.209 48.192 36.065 49.56 ;
     RECT  35.309 2.784 36.137 4.68 ;
     RECT  35.267 0.096 36.236 0.12 ;
     RECT  36.137 2.88 36.461 4.68 ;
     RECT  35.777 6.048 36.529 6.888 ;
     RECT  36.529 5.76 36.62 6.888 ;
     RECT  36.029 45.696 36.713 46.584 ;
     RECT  36.62 5.712 36.785 6.888 ;
     RECT  36.236 0.096 37.141 0.552 ;
     RECT  36.065 49.056 37.141 49.56 ;
     RECT  36.461 3.552 37.145 4.68 ;
     RECT  36.785 5.712 37.289 6.84 ;
     RECT  37.289 5.712 37.361 5.784 ;
     RECT  37.145 4.464 37.649 4.68 ;
     RECT  35.813 1.728 37.681 1.752 ;
     RECT  35.104 35.568 37.685 35.592 ;
     RECT  37.289 6.816 37.901 6.84 ;
     RECT  37.141 49.008 38.009 49.56 ;
     RECT  37.141 0.096 38.189 0.6 ;
     RECT  38.108 35.616 38.195 35.64 ;
     RECT  37.361 5.712 38.365 5.736 ;
     RECT  37.649 4.512 38.437 4.68 ;
     RECT  38.365 5.712 38.437 5.832 ;
     RECT  36.713 45.696 38.437 46.536 ;
     RECT  37.681 1.728 38.801 2.328 ;
     RECT  38.437 4.512 38.801 5.832 ;
     RECT  38.725 50.736 38.915 50.76 ;
     RECT  38.801 4.656 39.011 5.832 ;
     RECT  38.009 49.008 39.013 49.512 ;
     RECT  38.437 45.696 39.089 46.872 ;
     RECT  39.011 5.232 39.157 5.832 ;
     RECT  39.157 5.232 39.233 6.312 ;
     RECT  38.189 0.096 39.445 0.12 ;
     RECT  38.801 1.728 39.449 1.8 ;
     RECT  39.445 0.096 39.581 0.168 ;
     RECT  39.013 49.008 39.841 49.56 ;
     RECT  39.581 0.096 39.917 0.216 ;
     RECT  39.917 0.144 39.949 0.216 ;
     RECT  39.877 51.648 40.019 51.672 ;
     RECT  39.089 45.696 40.093 46.008 ;
     RECT  39.841 48.48 40.124 49.56 ;
     RECT  40.124 48.48 40.129 49.848 ;
     RECT  39.233 5.232 40.208 5.304 ;
     RECT  39.233 6.288 40.208 6.312 ;
     RECT  40.201 7.728 40.208 7.752 ;
     RECT  38.149 36.912 40.208 36.936 ;
     RECT  35.104 42.192 40.208 42.456 ;
     RECT  40.093 45.696 40.208 46.872 ;
     RECT  40.129 48.432 40.208 49.848 ;
     RECT  40.208 2.148 40.312 49.848 ;
     RECT  40.312 2.418 40.396 49.848 ;
     RECT  39.949 0.144 40.499 0.552 ;
     RECT  40.396 2.418 40.499 49.8 ;
     RECT  40.499 2.418 40.504 49.56 ;
     RECT  40.499 0.144 40.739 0.264 ;
     RECT  40.739 0.144 40.885 0.216 ;
     RECT  40.504 47.952 40.889 49.56 ;
     RECT  40.504 5.136 41.033 6.36 ;
     RECT  40.504 7.728 41.069 8.472 ;
     RECT  40.504 2.736 41.177 2.76 ;
     RECT  40.889 48.48 41.645 49.56 ;
     RECT  40.885 0.096 41.893 0.216 ;
     RECT  40.504 45.696 42.037 46.008 ;
     RECT  41.497 47.04 42.037 47.064 ;
     RECT  41.645 49.008 42.073 49.56 ;
     RECT  41.929 50.688 42.073 50.712 ;
     RECT  41.033 5.136 42.181 6.024 ;
     RECT  41.605 3.264 42.221 3.288 ;
     RECT  42.073 49.008 42.227 50.712 ;
     RECT  41.893 0.096 42.371 0.312 ;
     RECT  42.227 49.008 42.371 50.184 ;
     RECT  42.037 45.696 42.433 47.064 ;
     RECT  41.605 1.728 42.649 1.752 ;
     RECT  42.181 5.136 42.649 6.312 ;
     RECT  41.069 7.728 42.685 8.376 ;
     RECT  42.649 5.136 42.757 6.648 ;
     RECT  42.577 14.208 42.757 14.232 ;
     RECT  42.433 45.696 42.757 47.496 ;
     RECT  42.685 7.728 42.793 8.568 ;
     RECT  40.504 42.192 42.793 42.456 ;
     RECT  42.721 22.464 42.865 22.488 ;
     RECT  42.937 40.992 43.049 41.016 ;
     RECT  42.793 33.6 43.148 33.624 ;
     RECT  42.757 14.208 43.153 15.096 ;
     RECT  42.361 16.56 43.153 16.584 ;
     RECT  42.865 22.464 43.153 22.824 ;
     RECT  42.757 45.216 43.153 47.496 ;
     RECT  42.757 4.608 43.189 6.648 ;
     RECT  42.793 7.728 43.189 9.384 ;
     RECT  40.504 36.912 43.225 36.936 ;
     RECT  43.148 32.976 43.235 33.624 ;
     RECT  43.235 33.36 43.244 33.624 ;
     RECT  43.153 22.464 43.261 22.92 ;
     RECT  43.189 24.144 43.261 24.168 ;
     RECT  42.757 34.8 43.297 34.824 ;
     RECT  43.189 4.608 43.301 9.384 ;
     RECT  43.237 31.584 43.324 31.608 ;
     RECT  42.901 12.672 43.333 12.696 ;
     RECT  43.153 14.208 43.333 16.584 ;
     RECT  42.901 21.12 43.369 21.144 ;
     RECT  42.793 42.192 43.369 42.6 ;
     RECT  43.261 22.464 43.373 24.168 ;
     RECT  43.153 45.024 43.373 47.496 ;
     RECT  43.301 4.608 43.409 9.144 ;
     RECT  43.333 12.672 43.429 16.584 ;
     RECT  43.369 21.12 43.441 21.192 ;
     RECT  43.409 6.24 43.445 9.144 ;
     RECT  43.369 42.192 43.477 42.648 ;
     RECT  43.409 4.608 43.481 5.16 ;
     RECT  43.225 30.288 43.513 30.312 ;
     RECT  43.244 33.36 43.525 33.768 ;
     RECT  43.297 34.8 43.525 35.352 ;
     RECT  43.373 22.464 43.532 24.12 ;
     RECT  42.649 1.728 43.549 2.856 ;
     RECT  43.525 33.36 43.549 35.352 ;
     RECT  43.225 36.912 43.549 37.608 ;
     RECT  42.371 0.096 43.553 0.168 ;
     RECT  43.549 33.36 43.657 37.608 ;
     RECT  43.405 38.64 43.657 38.664 ;
     RECT  43.429 12.672 43.697 16.824 ;
     RECT  43.045 17.856 43.697 17.88 ;
     RECT  43.532 22.176 43.697 24.12 ;
     RECT  43.045 28.176 43.697 28.2 ;
     RECT  43.373 45.648 43.697 47.496 ;
     RECT  43.697 14.784 43.708 16.824 ;
     RECT  43.801 29.088 43.907 29.112 ;
     RECT  43.369 19.248 43.909 19.272 ;
     RECT  43.549 1.728 43.945 2.904 ;
     RECT  43.261 50.736 43.955 50.76 ;
     RECT  43.445 6.24 43.985 8.712 ;
     RECT  43.441 20.736 44.017 21.192 ;
     RECT  43.945 1.728 44.057 3 ;
     RECT  43.657 33.36 44.089 38.664 ;
     RECT  42.865 39.744 44.089 39.768 ;
     RECT  44.057 1.728 44.093 2.76 ;
     RECT  43.477 42.192 44.125 43.512 ;
     RECT  43.621 41.04 44.161 41.064 ;
     RECT  44.125 42.192 44.161 43.608 ;
     RECT  44.093 1.728 44.197 1.8 ;
     RECT  43.708 14.88 44.233 16.824 ;
     RECT  43.697 45.696 44.305 47.496 ;
     RECT  44.197 1.104 44.309 1.8 ;
     RECT  44.161 40.848 44.341 43.608 ;
     RECT  43.513 30.288 44.377 30.36 ;
     RECT  43.697 12.672 44.449 13.416 ;
     RECT  44.377 30.288 44.485 30.408 ;
     RECT  44.089 33.36 44.492 39.768 ;
     RECT  44.017 20.4 44.521 21.192 ;
     RECT  44.309 1.104 44.531 1.752 ;
     RECT  43.549 31.68 44.54 32.232 ;
     RECT  44.492 33.216 44.54 39.768 ;
     RECT  43.985 6.72 44.593 8.712 ;
     RECT  43.153 25.584 44.593 25.608 ;
     RECT  43.549 26.736 44.593 26.76 ;
     RECT  43.553 0.096 44.629 0.12 ;
     RECT  44.521 20.4 44.665 21.24 ;
     RECT  43.697 22.464 44.665 24.12 ;
     RECT  44.593 25.584 44.665 26.76 ;
     RECT  43.573 11.232 44.701 11.256 ;
     RECT  44.341 40.8 44.737 43.608 ;
     RECT  44.449 12.576 44.773 13.416 ;
     RECT  43.909 19.248 44.773 19.368 ;
     RECT  44.665 25.536 44.809 26.76 ;
     RECT  44.773 18.432 44.821 19.368 ;
     RECT  44.809 25.536 44.821 27.144 ;
     RECT  44.78 28.368 44.821 28.392 ;
     RECT  44.233 14.88 44.845 16.92 ;
     RECT  44.821 18.192 44.845 19.368 ;
     RECT  44.485 30.24 44.845 30.408 ;
     RECT  44.305 45.696 44.845 47.736 ;
     RECT  44.593 6.72 44.917 9.144 ;
     RECT  44.821 25.536 44.917 28.392 ;
     RECT  44.845 29.472 44.917 30.408 ;
     RECT  44.54 31.68 44.917 39.768 ;
     RECT  44.845 45.696 44.945 47.88 ;
     RECT  42.371 49.008 44.945 49.56 ;
     RECT  44.845 14.88 45.133 19.368 ;
     RECT  44.665 20.4 45.133 24.12 ;
     RECT  45.133 14.88 45.277 24.12 ;
     RECT  44.917 25.392 45.277 39.768 ;
     RECT  44.945 45.696 45.457 49.56 ;
     RECT  43.481 5.04 45.601 5.16 ;
     RECT  45.277 14.88 45.601 39.768 ;
     RECT  44.531 1.728 45.608 1.752 ;
     RECT  45.205 2.832 45.608 2.856 ;
     RECT  45.601 4.128 45.608 5.16 ;
     RECT  44.917 6.72 45.608 9.576 ;
     RECT  44.701 11.232 45.608 11.544 ;
     RECT  44.773 12.576 45.608 13.656 ;
     RECT  45.601 14.736 45.608 39.768 ;
     RECT  44.737 40.8 45.608 44.376 ;
     RECT  45.457 45.696 45.608 49.8 ;
     RECT  45.608 1.728 45.904 49.8 ;
     RECT  44.629 0.096 45.965 0.6 ;
     RECT  45.904 20.88 46.009 49.8 ;
     RECT  45.904 4.368 46.019 5.784 ;
     RECT  45.637 51.648 46.019 51.672 ;
     RECT  45.904 6.768 46.067 8.472 ;
     RECT  46.067 6.768 46.163 7.944 ;
     RECT  46.009 20.88 46.181 49.512 ;
     RECT  46.181 20.88 46.253 31.224 ;
     RECT  45.904 9.552 46.281 19.8 ;
     RECT  46.181 32.304 46.289 49.512 ;
     RECT  46.019 4.368 46.325 5.064 ;
     RECT  46.253 22.512 46.325 31.224 ;
     RECT  46.163 6.816 46.397 7.944 ;
     RECT  45.904 1.728 46.433 3.336 ;
     RECT  46.397 7.344 46.469 7.944 ;
     RECT  46.325 22.512 46.541 22.584 ;
     RECT  46.325 23.616 46.541 31.224 ;
     RECT  46.325 4.368 46.685 4.584 ;
     RECT  46.289 32.304 46.739 49.464 ;
     RECT  46.685 4.56 46.793 4.584 ;
     RECT  46.739 32.304 46.865 47.736 ;
     RECT  46.469 7.344 46.901 7.368 ;
     RECT  46.865 32.304 46.901 41.4 ;
     RECT  46.739 48.96 46.937 49.464 ;
     RECT  46.937 48.96 46.973 49.368 ;
     RECT  45.965 0.096 47.069 0.264 ;
     RECT  46.281 10.032 47.081 19.8 ;
     RECT  46.901 33.36 47.081 41.4 ;
     RECT  47.069 0.096 47.153 0.6 ;
     RECT  46.433 1.728 47.18 2.904 ;
     RECT  46.541 23.664 47.189 29.496 ;
     RECT  46.253 20.88 47.225 21.528 ;
     RECT  47.18 1.104 47.267 2.904 ;
     RECT  46.973 49.344 47.369 49.368 ;
     RECT  47.081 33.504 47.405 41.4 ;
     RECT  46.865 42.432 47.405 47.736 ;
     RECT  47.189 23.664 47.441 29.016 ;
     RECT  47.267 1.728 47.473 2.904 ;
     RECT  47.081 10.848 47.477 19.8 ;
     RECT  47.405 33.504 47.477 37.848 ;
     RECT  47.441 23.664 47.513 28.248 ;
     RECT  47.513 23.664 47.545 24.888 ;
     RECT  47.477 14.784 47.549 17.64 ;
     RECT  47.513 25.92 47.549 28.248 ;
     RECT  47.549 14.784 47.585 17.544 ;
     RECT  46.541 30.528 47.585 31.224 ;
     RECT  47.225 20.88 47.693 21.48 ;
     RECT  47.545 23.52 47.693 24.888 ;
     RECT  47.549 25.92 47.693 27.336 ;
     RECT  47.405 42.432 47.693 44.808 ;
     RECT  47.585 14.784 47.801 16.92 ;
     RECT  47.477 33.504 47.837 34.248 ;
     RECT  47.405 39.12 47.837 41.4 ;
     RECT  47.473 1.728 47.843 3.144 ;
     RECT  47.843 1.728 47.873 1.944 ;
     RECT  47.477 11.136 47.873 13.608 ;
     RECT  47.693 23.52 47.873 24.648 ;
     RECT  46.901 32.304 47.873 32.328 ;
     RECT  47.837 33.504 47.873 33.96 ;
     RECT  47.837 40.944 47.873 41.4 ;
     RECT  47.585 30.528 47.909 30.552 ;
     RECT  47.873 33.504 47.909 33.528 ;
     RECT  47.873 41.232 47.909 41.4 ;
     RECT  47.693 42.432 47.909 44.616 ;
     RECT  47.405 45.936 47.909 47.736 ;
     RECT  47.873 11.136 47.981 13.224 ;
     RECT  47.477 35.424 47.981 37.848 ;
     RECT  47.909 45.936 47.981 46.536 ;
     RECT  46.541 22.512 48.017 22.536 ;
     RECT  47.837 39.12 48.053 39.144 ;
     RECT  47.477 18.672 48.269 19.752 ;
     RECT  47.843 3.12 48.341 3.144 ;
     RECT  47.909 42.432 48.341 44.376 ;
     RECT  47.873 1.776 48.413 1.944 ;
     RECT  47.693 27.312 48.413 27.336 ;
     RECT  47.981 36.864 48.413 37.848 ;
     RECT  47.981 11.136 48.485 13.08 ;
     RECT  48.485 11.136 48.521 13.032 ;
     RECT  47.801 14.784 48.521 15.528 ;
     RECT  47.153 0.096 48.557 0.12 ;
     RECT  48.269 18.672 48.557 19.512 ;
     RECT  48.413 36.864 48.557 37.224 ;
     RECT  48.521 11.52 48.629 13.032 ;
     RECT  47.801 16.752 48.629 16.92 ;
     RECT  48.413 1.92 48.665 1.944 ;
     RECT  47.693 21.168 48.665 21.48 ;
     RECT  47.981 46.224 48.665 46.536 ;
     RECT  47.909 41.376 48.701 41.4 ;
     RECT  48.629 13.008 48.737 13.032 ;
     RECT  47.873 23.52 48.737 23.544 ;
     RECT  48.557 18.672 48.845 18.936 ;
     RECT  47.873 24.624 48.881 24.648 ;
     RECT  48.341 43.248 49.021 44.376 ;
     RECT  47.981 35.424 49.169 35.832 ;
     RECT  48.521 14.976 49.561 15 ;
     RECT  49.345 20.592 49.561 20.616 ;
     RECT  47.693 25.92 49.561 25.944 ;
     RECT  49.345 36.144 49.561 36.168 ;
     RECT  48.557 37.2 49.561 37.224 ;
     RECT  49.345 38.88 49.561 38.904 ;
     RECT  48.665 46.224 49.561 46.392 ;
     RECT  47.909 47.712 49.561 47.736 ;
     RECT  49.561 25.92 49.597 26.376 ;
     RECT  49.561 27.504 49.597 27.528 ;
     RECT  49.453 34.848 49.597 35.16 ;
     RECT  49.561 36.144 49.597 37.224 ;
     RECT  49.561 38.88 49.597 39.624 ;
     RECT  49.381 40.752 49.597 40.776 ;
     RECT  48.629 16.896 49.669 16.92 ;
     RECT  49.597 18.288 49.669 18.312 ;
     RECT  49.561 20.448 49.669 20.616 ;
     RECT  49.633 22.32 49.669 22.344 ;
     RECT  49.597 25.92 49.669 28.248 ;
     RECT  49.669 20.448 49.705 22.344 ;
     RECT  48.629 11.52 49.777 11.544 ;
     RECT  49.705 12.816 49.777 12.84 ;
     RECT  49.561 14.976 49.777 15.864 ;
     RECT  49.021 43.248 49.777 44.808 ;
     RECT  49.561 45.936 49.777 46.392 ;
     RECT  49.777 11.52 50.137 15.864 ;
     RECT  49.669 16.896 50.137 18.312 ;
     RECT  49.705 19.296 50.137 22.344 ;
     RECT  49.669 25.056 50.137 28.248 ;
     RECT  49.777 30.096 50.137 30.12 ;
     RECT  49.597 31.536 50.137 31.56 ;
     RECT  49.021 32.688 50.137 32.712 ;
     RECT  49.597 34.704 50.137 35.16 ;
     RECT  49.597 36.144 50.137 40.776 ;
     RECT  49.777 43.248 50.137 46.392 ;
     RECT  49.561 47.664 50.137 47.736 ;
     RECT  50.137 9.936 50.173 9.96 ;
     RECT  50.137 11.52 50.173 18.312 ;
     RECT  50.137 19.296 50.173 23.496 ;
     RECT  50.137 29.52 50.173 30.264 ;
     RECT  50.137 31.536 50.173 33.144 ;
     RECT  50.137 34.128 50.173 42.072 ;
     RECT  50.137 43.056 50.173 47.736 ;
     RECT  50.173 9.936 50.677 23.496 ;
     RECT  50.137 24.624 50.677 28.248 ;
     RECT  50.173 29.52 51.649 47.736 ;
     RECT  50.677 9.936 51.756 9.96 ;
     RECT  50.677 9.96 51.804 10.08 ;
     RECT  50.677 10.08 51.756 10.104 ;
     RECT  50.677 10.104 51.804 10.224 ;
     RECT  50.677 10.224 51.756 10.248 ;
     RECT  50.677 10.248 51.804 10.368 ;
     RECT  50.677 10.368 51.756 10.392 ;
     RECT  50.677 10.392 51.804 10.512 ;
     RECT  50.677 10.512 51.756 10.536 ;
     RECT  50.677 10.536 51.804 10.656 ;
     RECT  50.677 10.656 51.756 10.68 ;
     RECT  50.677 10.68 51.804 10.8 ;
     RECT  50.677 10.8 51.756 10.824 ;
     RECT  50.677 10.824 51.804 10.944 ;
     RECT  50.677 10.944 51.756 10.968 ;
     RECT  50.677 10.968 51.804 11.088 ;
     RECT  50.677 11.088 51.756 11.112 ;
     RECT  50.677 11.112 51.804 11.232 ;
     RECT  50.677 11.232 51.756 11.256 ;
     RECT  50.677 11.256 51.804 11.376 ;
     RECT  50.677 11.376 51.756 11.4 ;
     RECT  50.677 11.4 51.804 11.52 ;
     RECT  50.677 11.52 51.756 11.544 ;
     RECT  50.677 11.544 51.804 11.664 ;
     RECT  50.677 11.664 51.756 11.688 ;
     RECT  50.677 11.688 51.804 11.808 ;
     RECT  50.677 11.808 51.756 11.832 ;
     RECT  50.677 11.832 51.804 11.952 ;
     RECT  50.677 11.952 51.756 11.976 ;
     RECT  50.677 11.976 51.804 12.096 ;
     RECT  50.677 12.096 51.756 12.12 ;
     RECT  50.677 12.12 51.804 12.24 ;
     RECT  50.677 12.24 51.756 12.264 ;
     RECT  50.677 12.264 51.804 12.384 ;
     RECT  50.677 12.384 51.756 12.408 ;
     RECT  50.677 12.408 51.804 12.528 ;
     RECT  50.677 12.528 51.756 12.552 ;
     RECT  50.677 12.552 51.804 12.672 ;
     RECT  50.677 12.672 51.756 12.696 ;
     RECT  50.677 12.696 51.804 12.816 ;
     RECT  50.677 12.816 51.756 12.84 ;
     RECT  50.677 12.84 51.804 12.96 ;
     RECT  50.677 12.96 51.756 12.984 ;
     RECT  50.677 12.984 51.804 13.104 ;
     RECT  50.677 13.104 51.756 13.128 ;
     RECT  50.677 13.128 51.804 13.248 ;
     RECT  50.677 13.248 51.756 13.272 ;
     RECT  50.677 13.272 51.804 13.392 ;
     RECT  50.677 13.392 51.756 13.416 ;
     RECT  50.677 13.416 51.804 13.536 ;
     RECT  50.677 13.536 51.756 13.56 ;
     RECT  50.677 13.56 51.804 13.68 ;
     RECT  50.677 13.68 51.756 13.704 ;
     RECT  50.677 13.704 51.804 13.824 ;
     RECT  50.677 13.824 51.756 13.848 ;
     RECT  50.677 13.848 51.804 13.968 ;
     RECT  50.677 13.968 51.756 13.992 ;
     RECT  50.677 13.992 51.804 14.112 ;
     RECT  50.677 14.112 51.756 14.136 ;
     RECT  50.677 14.136 51.804 14.256 ;
     RECT  50.677 14.256 51.756 14.28 ;
     RECT  50.677 14.28 51.804 14.4 ;
     RECT  50.677 14.4 51.756 14.424 ;
     RECT  50.677 14.424 51.804 14.544 ;
     RECT  50.677 14.544 51.756 14.568 ;
     RECT  50.677 14.568 51.804 14.688 ;
     RECT  50.677 14.688 51.756 14.712 ;
     RECT  50.677 14.712 51.804 14.832 ;
     RECT  50.677 14.832 51.756 14.856 ;
     RECT  50.677 14.856 51.804 14.976 ;
     RECT  50.677 14.976 51.756 15 ;
     RECT  50.677 15 51.804 15.12 ;
     RECT  50.677 15.12 51.756 15.144 ;
     RECT  50.677 15.144 51.804 15.264 ;
     RECT  50.677 15.264 51.756 15.288 ;
     RECT  50.677 15.288 51.804 15.408 ;
     RECT  50.677 15.408 51.756 15.432 ;
     RECT  50.677 15.432 51.804 15.552 ;
     RECT  50.677 15.552 51.756 15.576 ;
     RECT  50.677 15.576 51.804 15.696 ;
     RECT  50.677 15.696 51.756 15.72 ;
     RECT  50.677 15.72 51.804 15.84 ;
     RECT  50.677 15.84 51.756 15.864 ;
     RECT  50.677 15.864 51.804 15.984 ;
     RECT  50.677 15.984 51.756 16.008 ;
     RECT  50.677 16.008 51.804 16.128 ;
     RECT  50.677 16.128 51.756 16.152 ;
     RECT  50.677 16.152 51.804 16.272 ;
     RECT  50.677 16.272 51.756 16.296 ;
     RECT  50.677 16.296 51.804 16.416 ;
     RECT  50.677 16.416 51.756 16.44 ;
     RECT  50.677 16.44 51.804 16.56 ;
     RECT  50.677 16.56 51.756 16.584 ;
     RECT  50.677 16.584 51.804 16.704 ;
     RECT  50.677 16.704 51.756 16.728 ;
     RECT  50.677 16.728 51.804 16.848 ;
     RECT  50.677 16.848 51.756 16.872 ;
     RECT  50.677 16.872 51.804 16.992 ;
     RECT  50.677 16.992 51.756 17.016 ;
     RECT  50.677 17.016 51.804 17.136 ;
     RECT  50.677 17.136 51.756 17.16 ;
     RECT  50.677 17.16 51.804 17.28 ;
     RECT  50.677 17.28 51.756 17.304 ;
     RECT  50.677 17.304 51.804 17.424 ;
     RECT  50.677 17.424 51.756 17.448 ;
     RECT  50.677 17.448 51.804 17.568 ;
     RECT  50.677 17.568 51.756 17.592 ;
     RECT  50.677 17.592 51.804 17.712 ;
     RECT  50.677 17.712 51.756 17.736 ;
     RECT  50.677 17.736 51.804 17.856 ;
     RECT  50.677 17.856 51.756 17.88 ;
     RECT  50.677 17.88 51.804 18 ;
     RECT  50.677 18 51.756 18.024 ;
     RECT  50.677 18.024 51.804 18.144 ;
     RECT  50.677 18.144 51.756 18.168 ;
     RECT  50.677 18.168 51.804 18.288 ;
     RECT  50.677 18.288 51.756 18.312 ;
     RECT  50.677 18.312 51.804 18.432 ;
     RECT  50.677 18.432 51.756 18.456 ;
     RECT  50.677 18.456 51.804 18.576 ;
     RECT  50.677 18.576 51.756 18.6 ;
     RECT  50.677 18.6 51.804 18.72 ;
     RECT  50.677 18.72 51.756 18.744 ;
     RECT  50.677 18.744 51.804 18.864 ;
     RECT  50.677 18.864 51.756 18.888 ;
     RECT  50.677 18.888 51.804 19.008 ;
     RECT  50.677 19.008 51.756 19.032 ;
     RECT  50.677 19.032 51.804 19.152 ;
     RECT  50.677 19.152 51.756 19.176 ;
     RECT  50.677 19.176 51.804 19.296 ;
     RECT  50.677 19.296 51.756 19.32 ;
     RECT  50.677 19.32 51.804 19.44 ;
     RECT  50.677 19.44 51.756 19.464 ;
     RECT  50.677 19.464 51.804 19.584 ;
     RECT  50.677 19.584 51.756 19.608 ;
     RECT  50.677 19.608 51.804 19.728 ;
     RECT  50.677 19.728 51.756 19.752 ;
     RECT  50.677 19.752 51.804 19.872 ;
     RECT  50.677 19.872 51.756 19.896 ;
     RECT  50.677 19.896 51.804 20.016 ;
     RECT  50.677 20.016 51.756 20.04 ;
     RECT  50.677 20.04 51.804 20.16 ;
     RECT  50.677 20.16 51.756 20.184 ;
     RECT  50.677 20.184 51.804 20.304 ;
     RECT  50.677 20.304 51.756 20.328 ;
     RECT  50.677 20.328 51.804 20.448 ;
     RECT  50.677 20.448 51.756 20.472 ;
     RECT  50.677 20.472 51.804 20.592 ;
     RECT  50.677 20.592 51.756 20.616 ;
     RECT  50.677 20.616 51.804 20.736 ;
     RECT  50.677 20.736 51.756 20.76 ;
     RECT  50.677 20.76 51.804 20.88 ;
     RECT  50.677 20.88 51.756 20.904 ;
     RECT  50.677 20.904 51.804 21.024 ;
     RECT  50.677 21.024 51.756 21.048 ;
     RECT  50.677 21.048 51.804 21.168 ;
     RECT  50.677 21.168 51.756 21.192 ;
     RECT  50.677 21.192 51.804 21.312 ;
     RECT  50.677 21.312 51.756 21.336 ;
     RECT  50.677 21.336 51.804 21.456 ;
     RECT  50.677 21.456 51.756 21.48 ;
     RECT  50.677 21.48 51.804 21.6 ;
     RECT  50.677 21.6 51.756 21.624 ;
     RECT  50.677 21.624 51.804 21.744 ;
     RECT  50.677 21.744 51.756 21.768 ;
     RECT  50.677 21.768 51.804 21.888 ;
     RECT  50.677 21.888 51.756 21.912 ;
     RECT  50.677 21.912 51.804 22.032 ;
     RECT  50.677 22.032 51.756 22.056 ;
     RECT  50.677 22.056 51.804 22.176 ;
     RECT  50.677 22.176 51.756 22.2 ;
     RECT  50.677 22.2 51.804 22.32 ;
     RECT  50.677 22.32 51.756 22.344 ;
     RECT  50.677 22.344 51.804 22.464 ;
     RECT  50.677 22.464 51.756 22.488 ;
     RECT  50.677 22.488 51.804 22.608 ;
     RECT  50.677 22.608 51.756 22.632 ;
     RECT  50.677 22.632 51.804 22.752 ;
     RECT  50.677 22.752 51.756 22.776 ;
     RECT  50.677 22.776 51.804 22.896 ;
     RECT  50.677 22.896 51.756 22.92 ;
     RECT  50.677 22.92 51.804 23.04 ;
     RECT  50.677 23.04 51.756 23.064 ;
     RECT  50.677 23.064 51.804 23.184 ;
     RECT  50.677 23.184 51.756 23.208 ;
     RECT  50.677 23.208 51.804 23.328 ;
     RECT  50.677 23.328 51.756 23.352 ;
     RECT  50.677 23.352 51.804 23.472 ;
     RECT  50.677 23.472 51.756 23.496 ;
     RECT  50.677 23.496 51.804 23.616 ;
     RECT  50.677 23.616 51.756 23.64 ;
     RECT  50.677 23.64 51.804 23.76 ;
     RECT  50.677 23.76 51.756 23.784 ;
     RECT  50.677 23.784 51.804 23.904 ;
     RECT  50.677 23.904 51.756 23.928 ;
     RECT  50.677 23.928 51.804 24.048 ;
     RECT  50.677 24.048 51.756 24.072 ;
     RECT  50.677 24.072 51.804 24.192 ;
     RECT  50.677 24.192 51.756 24.216 ;
     RECT  50.677 24.216 51.804 24.336 ;
     RECT  50.677 24.336 51.756 24.36 ;
     RECT  50.677 24.36 51.804 24.48 ;
     RECT  50.677 24.48 51.756 24.504 ;
     RECT  50.677 24.504 51.804 24.624 ;
     RECT  50.677 24.624 51.756 24.648 ;
     RECT  50.677 24.648 51.804 24.768 ;
     RECT  50.677 24.768 51.756 24.792 ;
     RECT  50.677 24.792 51.804 24.912 ;
     RECT  50.677 24.912 51.756 24.936 ;
     RECT  50.677 24.936 51.804 25.056 ;
     RECT  50.677 25.056 51.756 25.08 ;
     RECT  50.677 25.08 51.804 25.2 ;
     RECT  50.677 25.2 51.756 25.224 ;
     RECT  50.677 25.224 51.804 25.344 ;
     RECT  50.677 25.344 51.756 25.368 ;
     RECT  50.677 25.368 51.804 25.488 ;
     RECT  50.677 25.488 51.756 25.512 ;
     RECT  50.677 25.512 51.804 25.632 ;
     RECT  50.677 25.632 51.756 25.656 ;
     RECT  50.677 25.656 51.804 25.776 ;
     RECT  50.677 25.776 51.756 25.8 ;
     RECT  50.677 25.8 51.804 25.92 ;
     RECT  50.677 25.92 51.756 25.944 ;
     RECT  50.677 25.944 51.804 26.064 ;
     RECT  50.677 26.064 51.756 26.088 ;
     RECT  50.677 26.088 51.804 26.208 ;
     RECT  50.677 26.208 51.756 26.232 ;
     RECT  50.677 26.232 51.804 26.352 ;
     RECT  50.677 26.352 51.756 26.376 ;
     RECT  50.677 26.376 51.804 26.496 ;
     RECT  50.677 26.496 51.756 26.52 ;
     RECT  50.677 26.52 51.804 26.64 ;
     RECT  50.677 26.64 51.756 26.664 ;
     RECT  50.677 26.664 51.804 26.784 ;
     RECT  50.677 26.784 51.756 26.808 ;
     RECT  50.677 26.808 51.804 26.928 ;
     RECT  50.677 26.928 51.756 26.952 ;
     RECT  50.677 26.952 51.804 27.072 ;
     RECT  50.677 27.072 51.756 27.096 ;
     RECT  50.677 27.096 51.804 27.216 ;
     RECT  50.677 27.216 51.756 27.24 ;
     RECT  50.677 27.24 51.804 27.36 ;
     RECT  50.677 27.36 51.756 27.384 ;
     RECT  50.677 27.384 51.804 27.504 ;
     RECT  50.677 27.504 51.756 27.528 ;
     RECT  50.677 27.528 51.804 27.648 ;
     RECT  50.677 27.648 51.756 27.672 ;
     RECT  50.677 27.672 51.804 27.792 ;
     RECT  50.677 27.792 51.756 27.816 ;
     RECT  50.677 27.816 51.804 27.936 ;
     RECT  50.677 27.936 51.756 27.96 ;
     RECT  50.677 27.96 51.804 28.08 ;
     RECT  50.677 28.08 51.756 28.104 ;
     RECT  50.677 28.104 51.804 28.224 ;
     RECT  50.677 28.224 51.756 28.248 ;
     RECT  51.649 29.52 51.756 29.544 ;
     RECT  51.649 29.544 51.804 29.664 ;
     RECT  51.649 29.664 51.756 29.688 ;
     RECT  51.649 29.688 51.804 29.808 ;
     RECT  51.649 29.808 51.756 29.832 ;
     RECT  51.649 29.832 51.804 29.952 ;
     RECT  51.649 29.952 51.756 29.976 ;
     RECT  51.649 29.976 51.804 30.096 ;
     RECT  51.649 30.096 51.756 30.12 ;
     RECT  51.649 30.12 51.804 30.24 ;
     RECT  51.649 30.24 51.756 30.264 ;
     RECT  51.649 30.264 51.804 30.384 ;
     RECT  51.649 30.384 51.756 30.408 ;
     RECT  51.649 30.408 51.804 30.528 ;
     RECT  51.649 30.528 51.756 30.552 ;
     RECT  51.649 30.552 51.804 30.672 ;
     RECT  51.649 30.672 51.756 30.696 ;
     RECT  51.649 30.696 51.804 30.816 ;
     RECT  51.649 30.816 51.756 30.84 ;
     RECT  51.649 30.84 51.804 30.96 ;
     RECT  51.649 30.96 51.756 30.984 ;
     RECT  51.649 30.984 51.804 31.104 ;
     RECT  51.649 31.104 51.756 31.128 ;
     RECT  51.649 31.128 51.804 31.248 ;
     RECT  51.649 31.248 51.756 31.272 ;
     RECT  51.649 31.272 51.804 31.392 ;
     RECT  51.649 31.392 51.756 31.416 ;
     RECT  51.649 31.416 51.804 31.536 ;
     RECT  51.649 31.536 51.756 31.56 ;
     RECT  51.649 31.56 51.804 31.68 ;
     RECT  51.649 31.68 51.756 31.704 ;
     RECT  51.649 31.704 51.804 31.824 ;
     RECT  51.649 31.824 51.756 31.848 ;
     RECT  51.649 31.848 51.804 31.968 ;
     RECT  51.649 31.968 51.756 31.992 ;
     RECT  51.649 31.992 51.804 32.112 ;
     RECT  51.649 32.112 51.756 32.136 ;
     RECT  51.649 32.136 51.804 32.256 ;
     RECT  51.649 32.256 51.756 32.28 ;
     RECT  51.649 32.28 51.804 32.4 ;
     RECT  51.649 32.4 51.756 32.424 ;
     RECT  51.649 32.424 51.804 32.544 ;
     RECT  51.649 32.544 51.756 32.568 ;
     RECT  51.649 32.568 51.804 32.688 ;
     RECT  51.649 32.688 51.756 32.712 ;
     RECT  51.649 32.712 51.804 32.832 ;
     RECT  51.649 32.832 51.756 32.856 ;
     RECT  51.649 32.856 51.804 32.976 ;
     RECT  51.649 32.976 51.756 33 ;
     RECT  51.649 33 51.804 33.12 ;
     RECT  51.649 33.12 51.756 33.144 ;
     RECT  51.649 33.144 51.804 33.264 ;
     RECT  51.649 33.264 51.756 33.288 ;
     RECT  51.649 33.288 51.804 33.408 ;
     RECT  51.649 33.408 51.756 33.432 ;
     RECT  51.649 33.432 51.804 33.552 ;
     RECT  51.649 33.552 51.756 33.576 ;
     RECT  51.649 33.576 51.804 33.696 ;
     RECT  51.649 33.696 51.756 33.72 ;
     RECT  51.649 33.72 51.804 33.84 ;
     RECT  51.649 33.84 51.756 33.864 ;
     RECT  51.649 33.864 51.804 33.984 ;
     RECT  51.649 33.984 51.756 34.008 ;
     RECT  51.649 34.008 51.804 34.128 ;
     RECT  51.649 34.128 51.756 34.152 ;
     RECT  51.649 34.152 51.804 34.272 ;
     RECT  51.649 34.272 51.756 34.296 ;
     RECT  51.649 34.296 51.804 34.416 ;
     RECT  51.649 34.416 51.756 34.44 ;
     RECT  51.649 34.44 51.804 34.56 ;
     RECT  51.649 34.56 51.756 34.584 ;
     RECT  51.649 34.584 51.804 34.704 ;
     RECT  51.649 34.704 51.756 34.728 ;
     RECT  51.649 34.728 51.804 34.848 ;
     RECT  51.649 34.848 51.756 34.872 ;
     RECT  51.649 34.872 51.804 34.992 ;
     RECT  51.649 34.992 51.756 35.016 ;
     RECT  51.649 35.016 51.804 35.136 ;
     RECT  51.649 35.136 51.756 35.16 ;
     RECT  51.649 35.16 51.804 35.28 ;
     RECT  51.649 35.28 51.756 35.304 ;
     RECT  51.649 35.304 51.804 35.424 ;
     RECT  51.649 35.424 51.756 35.448 ;
     RECT  51.649 35.448 51.804 35.568 ;
     RECT  51.649 35.568 51.756 35.592 ;
     RECT  51.649 35.592 51.804 35.712 ;
     RECT  51.649 35.712 51.756 35.736 ;
     RECT  51.649 35.736 51.804 35.856 ;
     RECT  51.649 35.856 51.756 35.88 ;
     RECT  51.649 35.88 51.804 36 ;
     RECT  51.649 36 51.756 36.024 ;
     RECT  51.649 36.024 51.804 36.144 ;
     RECT  51.649 36.144 51.756 36.168 ;
     RECT  51.649 36.168 51.804 36.288 ;
     RECT  51.649 36.288 51.756 36.312 ;
     RECT  51.649 36.312 51.804 36.432 ;
     RECT  51.649 36.432 51.756 36.456 ;
     RECT  51.649 36.456 51.804 36.576 ;
     RECT  51.649 36.576 51.756 36.6 ;
     RECT  51.649 36.6 51.804 36.72 ;
     RECT  51.649 36.72 51.756 36.744 ;
     RECT  51.649 36.744 51.804 36.864 ;
     RECT  51.649 36.864 51.756 36.888 ;
     RECT  51.649 36.888 51.804 37.008 ;
     RECT  51.649 37.008 51.756 37.032 ;
     RECT  51.649 37.032 51.804 37.152 ;
     RECT  51.649 37.152 51.756 37.176 ;
     RECT  51.649 37.176 51.804 37.296 ;
     RECT  51.649 37.296 51.756 37.32 ;
     RECT  51.649 37.32 51.804 37.44 ;
     RECT  51.649 37.44 51.756 37.464 ;
     RECT  51.649 37.464 51.804 37.584 ;
     RECT  51.649 37.584 51.756 37.608 ;
     RECT  51.649 37.608 51.804 37.728 ;
     RECT  51.649 37.728 51.756 37.752 ;
     RECT  51.649 37.752 51.804 37.872 ;
     RECT  51.649 37.872 51.756 37.896 ;
     RECT  51.649 37.896 51.804 38.016 ;
     RECT  51.649 38.016 51.756 38.04 ;
     RECT  51.649 38.04 51.804 38.16 ;
     RECT  51.649 38.16 51.756 38.184 ;
     RECT  51.649 38.184 51.804 38.304 ;
     RECT  51.649 38.304 51.756 38.328 ;
     RECT  51.649 38.328 51.804 38.448 ;
     RECT  51.649 38.448 51.756 38.472 ;
     RECT  51.649 38.472 51.804 38.592 ;
     RECT  51.649 38.592 51.756 38.616 ;
     RECT  51.649 38.616 51.804 38.736 ;
     RECT  51.649 38.736 51.756 38.76 ;
     RECT  51.649 38.76 51.804 38.88 ;
     RECT  51.649 38.88 51.756 38.904 ;
     RECT  51.649 38.904 51.804 39.024 ;
     RECT  51.649 39.024 51.756 39.048 ;
     RECT  51.649 39.048 51.804 39.168 ;
     RECT  51.649 39.168 51.756 39.192 ;
     RECT  51.649 39.192 51.804 39.312 ;
     RECT  51.649 39.312 51.756 39.336 ;
     RECT  51.649 39.336 51.804 39.456 ;
     RECT  51.649 39.456 51.756 39.48 ;
     RECT  51.649 39.48 51.804 39.6 ;
     RECT  51.649 39.6 51.756 39.624 ;
     RECT  51.649 39.624 51.804 39.744 ;
     RECT  51.649 39.744 51.756 39.768 ;
     RECT  51.649 39.768 51.804 39.888 ;
     RECT  51.649 39.888 51.756 39.912 ;
     RECT  51.649 39.912 51.804 40.032 ;
     RECT  51.649 40.032 51.756 40.056 ;
     RECT  51.649 40.056 51.804 40.176 ;
     RECT  51.649 40.176 51.756 40.2 ;
     RECT  51.649 40.2 51.804 40.32 ;
     RECT  51.649 40.32 51.756 40.344 ;
     RECT  51.649 40.344 51.804 40.464 ;
     RECT  51.649 40.464 51.756 40.488 ;
     RECT  51.649 40.488 51.804 40.608 ;
     RECT  51.649 40.608 51.756 40.632 ;
     RECT  51.649 40.632 51.804 40.752 ;
     RECT  51.649 40.752 51.756 40.776 ;
     RECT  51.649 40.776 51.804 40.896 ;
     RECT  51.649 40.896 51.756 40.92 ;
     RECT  51.649 40.92 51.804 41.04 ;
     RECT  51.649 41.04 51.756 41.064 ;
     RECT  51.649 41.064 51.804 41.184 ;
     RECT  51.649 41.184 51.756 41.208 ;
     RECT  51.649 41.208 51.804 41.328 ;
     RECT  51.649 41.328 51.756 41.352 ;
     RECT  51.649 41.352 51.804 41.472 ;
     RECT  51.649 41.472 51.756 41.496 ;
     RECT  51.649 41.496 51.804 41.616 ;
     RECT  51.649 41.616 51.756 41.64 ;
     RECT  51.649 41.64 51.804 41.76 ;
     RECT  51.649 41.76 51.756 41.784 ;
     RECT  51.649 41.784 51.804 41.904 ;
     RECT  51.649 41.904 51.756 41.928 ;
     RECT  51.649 41.928 51.804 42.048 ;
     RECT  51.649 42.048 51.756 42.072 ;
     RECT  51.649 42.072 51.804 42.192 ;
     RECT  51.649 42.192 51.756 42.216 ;
     RECT  51.649 42.216 51.804 42.336 ;
     RECT  51.649 42.336 51.756 42.36 ;
     RECT  51.649 42.36 51.804 42.48 ;
     RECT  51.649 42.48 51.756 42.504 ;
     RECT  51.649 42.504 51.804 42.624 ;
     RECT  51.649 42.624 51.756 42.648 ;
     RECT  51.649 42.648 51.804 42.768 ;
     RECT  51.649 42.768 51.756 42.792 ;
     RECT  51.649 42.792 51.804 42.912 ;
     RECT  51.649 42.912 51.756 42.936 ;
     RECT  51.649 42.936 51.804 43.056 ;
     RECT  51.649 43.056 51.756 43.08 ;
     RECT  51.649 43.08 51.804 43.2 ;
     RECT  51.649 43.2 51.756 43.224 ;
     RECT  51.649 43.224 51.804 43.344 ;
     RECT  51.649 43.344 51.756 43.368 ;
     RECT  51.649 43.368 51.804 43.488 ;
     RECT  51.649 43.488 51.756 43.512 ;
     RECT  51.649 43.512 51.804 43.632 ;
     RECT  51.649 43.632 51.756 43.656 ;
     RECT  51.649 43.656 51.804 43.776 ;
     RECT  51.649 43.776 51.756 43.8 ;
     RECT  51.649 43.8 51.804 43.92 ;
     RECT  51.649 43.92 51.756 43.944 ;
     RECT  51.649 43.944 51.804 44.064 ;
     RECT  51.649 44.064 51.756 44.088 ;
     RECT  51.649 44.088 51.804 44.208 ;
     RECT  51.649 44.208 51.756 44.232 ;
     RECT  51.649 44.232 51.804 44.352 ;
     RECT  51.649 44.352 51.756 44.376 ;
     RECT  51.649 44.376 51.804 44.496 ;
     RECT  51.649 44.496 51.756 44.52 ;
     RECT  51.649 44.52 51.804 44.64 ;
     RECT  51.649 44.64 51.756 44.664 ;
     RECT  51.649 44.664 51.804 44.784 ;
     RECT  51.649 44.784 51.756 44.808 ;
     RECT  51.649 44.808 51.804 44.928 ;
     RECT  51.649 44.928 51.756 44.952 ;
     RECT  51.649 44.952 51.804 45.072 ;
     RECT  51.649 45.072 51.756 45.096 ;
     RECT  51.649 45.096 51.804 45.216 ;
     RECT  51.649 45.216 51.756 45.24 ;
     RECT  51.649 45.24 51.804 45.36 ;
     RECT  51.649 45.36 51.756 45.384 ;
     RECT  51.649 45.384 51.804 45.504 ;
     RECT  51.649 45.504 51.756 45.528 ;
     RECT  51.649 45.528 51.804 45.648 ;
     RECT  51.649 45.648 51.756 45.672 ;
     RECT  51.649 45.672 51.804 45.792 ;
     RECT  51.649 45.792 51.756 45.816 ;
     RECT  51.649 45.816 51.804 45.936 ;
     RECT  51.649 45.936 51.756 45.96 ;
     RECT  51.649 45.96 51.804 46.08 ;
     RECT  51.649 46.08 51.756 46.104 ;
     RECT  51.649 46.104 51.804 46.224 ;
     RECT  51.649 46.224 51.756 46.248 ;
     RECT  51.649 46.248 51.804 46.368 ;
     RECT  51.649 46.368 51.756 46.392 ;
     RECT  51.649 46.392 51.804 46.512 ;
     RECT  51.649 46.512 51.756 46.536 ;
     RECT  51.649 46.536 51.804 46.656 ;
     RECT  51.649 46.656 51.756 46.68 ;
     RECT  51.649 46.68 51.804 46.8 ;
     RECT  51.649 46.8 51.756 46.824 ;
     RECT  51.649 46.824 51.804 46.944 ;
     RECT  51.649 46.944 51.756 46.968 ;
     RECT  51.649 46.968 51.804 47.088 ;
     RECT  51.649 47.088 51.756 47.112 ;
     RECT  51.649 47.112 51.804 47.232 ;
     RECT  51.649 47.232 51.756 47.256 ;
     RECT  51.649 47.256 51.804 47.376 ;
     RECT  51.649 47.376 51.756 47.4 ;
     RECT  51.649 47.4 51.804 47.52 ;
     RECT  51.649 47.52 51.756 47.544 ;
     RECT  51.649 47.544 51.804 47.664 ;
     RECT  51.649 47.664 51.756 47.688 ;
     RECT  51.649 47.688 51.804 47.808 ;
     RECT  51.649 47.808 51.756 47.832 ;
    LAYER M5 ;
     RECT  29.544 0.016 29.664 0.084 ;
     RECT  29.688 0.016 29.808 0.084 ;
     RECT  29.832 0.016 29.952 0.084 ;
     RECT  29.976 0.016 30.096 0.084 ;
     RECT  30.12 0.016 30.24 0.084 ;
     RECT  30.264 0.016 30.384 0.084 ;
     RECT  30.408 0.016 30.528 0.084 ;
     RECT  30.552 0.016 30.672 0.084 ;
     RECT  30.696 0.016 30.816 0.084 ;
     RECT  30.84 0.016 30.96 0.084 ;
     RECT  30.984 0.016 31.104 0.084 ;
     RECT  31.128 0.016 31.248 0.084 ;
     RECT  31.272 0.016 31.392 0.084 ;
     RECT  31.416 0.016 31.536 0.084 ;
     RECT  31.56 0.016 31.68 0.084 ;
     RECT  31.704 0.016 31.824 0.084 ;
     RECT  31.848 0.016 31.968 0.084 ;
     RECT  31.992 0.016 32.112 0.084 ;
     RECT  32.136 0.016 32.256 0.084 ;
     RECT  32.28 0.016 32.4 0.084 ;
     RECT  32.424 0.016 32.544 0.084 ;
     RECT  32.568 0.016 32.688 0.084 ;
     RECT  32.712 0.016 32.832 0.084 ;
     RECT  32.856 0.016 32.976 0.084 ;
     RECT  33 0.016 33.12 0.084 ;
     RECT  33.144 0.016 33.264 0.084 ;
     RECT  33.288 0.016 33.408 0.084 ;
     RECT  33.432 0.016 33.552 0.084 ;
     RECT  33.576 0.016 33.696 0.084 ;
     RECT  33.72 0.016 33.84 0.084 ;
     RECT  33.864 0.016 33.984 0.084 ;
     RECT  34.008 0.016 34.128 0.084 ;
     RECT  34.152 0.016 34.272 0.084 ;
     RECT  34.296 0.016 34.416 0.084 ;
     RECT  34.44 0.016 34.56 0.084 ;
     RECT  34.584 0.016 34.704 0.084 ;
     RECT  34.728 0.016 34.848 0.084 ;
     RECT  34.872 0.016 34.992 0.084 ;
     RECT  35.016 0.016 35.136 0.084 ;
     RECT  35.16 0.016 35.28 0.084 ;
     RECT  35.304 0.016 35.424 0.084 ;
     RECT  35.448 0.016 35.568 0.084 ;
     RECT  35.592 0.016 35.712 0.084 ;
     RECT  35.736 0.016 35.856 0.084 ;
     RECT  35.88 0.016 36 0.084 ;
     RECT  36.024 0.016 36.144 0.084 ;
     RECT  36.168 0.016 36.288 0.084 ;
     RECT  36.312 0.016 36.432 0.084 ;
     RECT  36.456 0.016 36.576 0.084 ;
     RECT  36.6 0.016 36.72 0.084 ;
     RECT  36.744 0.016 36.864 0.084 ;
     RECT  36.888 0.016 37.008 0.084 ;
     RECT  37.032 0.016 37.152 0.084 ;
     RECT  37.176 0.016 37.296 0.084 ;
     RECT  37.32 0.016 37.44 0.084 ;
     RECT  37.464 0.016 37.584 0.084 ;
     RECT  37.608 0.016 37.728 0.084 ;
     RECT  37.752 0.016 37.872 0.084 ;
     RECT  37.896 0.016 38.016 0.084 ;
     RECT  38.04 0.016 38.16 0.084 ;
     RECT  38.184 0.016 38.304 0.084 ;
     RECT  38.328 0.016 38.448 0.084 ;
     RECT  38.472 0.016 38.592 0.084 ;
     RECT  38.616 0.016 38.736 0.084 ;
     RECT  38.76 0.016 38.88 0.084 ;
     RECT  38.904 0.016 39.024 0.084 ;
     RECT  39.048 0.016 39.168 0.084 ;
     RECT  39.192 0.016 39.312 0.084 ;
     RECT  39.336 0.016 39.456 0.084 ;
     RECT  39.48 0.016 39.6 0.084 ;
     RECT  39.624 0.016 39.744 0.084 ;
     RECT  39.768 0.016 39.888 0.084 ;
     RECT  39.912 0.016 40.032 0.084 ;
     RECT  40.056 0.016 40.176 0.084 ;
     RECT  40.2 0.016 40.32 0.084 ;
     RECT  40.344 0.016 40.464 0.084 ;
     RECT  40.488 0.016 40.608 0.084 ;
     RECT  40.632 0.016 40.752 0.084 ;
     RECT  40.776 0.016 40.896 0.084 ;
     RECT  40.92 0.016 41.04 0.084 ;
     RECT  41.064 0.016 41.184 0.084 ;
     RECT  41.208 0.016 41.328 0.084 ;
     RECT  41.352 0.016 41.472 0.084 ;
     RECT  41.496 0.016 41.616 0.084 ;
     RECT  41.64 0.016 41.76 0.084 ;
     RECT  41.784 0.016 41.904 0.084 ;
     RECT  41.928 0.016 42.048 0.084 ;
     RECT  42.072 0.016 42.192 0.084 ;
     RECT  42.216 0.016 42.336 0.084 ;
     RECT  42.36 0.016 42.48 0.084 ;
     RECT  42.504 0.016 42.624 0.084 ;
     RECT  42.648 0.016 42.768 0.084 ;
     RECT  42.792 0.016 42.912 0.084 ;
     RECT  42.936 0.016 43.056 0.084 ;
     RECT  43.08 0.016 43.2 0.084 ;
     RECT  43.224 0.016 43.344 0.084 ;
     RECT  43.368 0.016 43.488 0.084 ;
     RECT  43.512 0.016 43.632 0.084 ;
     RECT  43.656 0.016 43.776 0.084 ;
     RECT  43.8 0.016 43.92 0.084 ;
     RECT  43.944 0.016 44.064 0.084 ;
     RECT  44.088 0.016 44.208 0.084 ;
     RECT  44.232 0.016 44.352 0.084 ;
     RECT  44.376 0.016 44.496 0.084 ;
     RECT  44.52 0.016 44.64 0.084 ;
     RECT  44.664 0.016 44.784 0.084 ;
     RECT  44.808 0.016 44.928 0.084 ;
     RECT  44.952 0.016 45.072 0.084 ;
     RECT  45.096 0.016 45.216 0.084 ;
     RECT  45.24 0.016 45.36 0.084 ;
     RECT  45.384 0.016 45.504 0.084 ;
     RECT  45.528 0.016 45.648 0.084 ;
     RECT  45.672 0.016 45.792 0.084 ;
     RECT  45.816 0.016 45.936 0.084 ;
     RECT  45.96 0.016 46.08 0.084 ;
     RECT  46.104 0.016 46.224 0.084 ;
     RECT  46.248 0.016 46.368 0.084 ;
     RECT  46.392 0.016 46.512 0.084 ;
     RECT  46.536 0.016 46.656 0.084 ;
     RECT  46.68 0.016 46.8 0.084 ;
     RECT  46.824 0.016 46.944 0.084 ;
     RECT  46.968 0.016 47.088 0.084 ;
     RECT  47.112 0.016 47.232 0.084 ;
     RECT  47.256 0.016 47.376 0.084 ;
     RECT  47.4 0.016 47.52 0.084 ;
     RECT  47.544 0.016 47.664 0.084 ;
     RECT  47.688 0.016 47.808 0.084 ;
     RECT  29.52 0.084 47.832 0.275 ;
     RECT  9.96 0.016 10.08 0.084 ;
     RECT  10.104 0.016 10.224 0.084 ;
     RECT  10.248 0.016 10.368 0.084 ;
     RECT  10.392 0.016 10.512 0.084 ;
     RECT  10.536 0.016 10.656 0.084 ;
     RECT  10.68 0.016 10.8 0.084 ;
     RECT  10.824 0.016 10.944 0.084 ;
     RECT  10.968 0.016 11.088 0.084 ;
     RECT  11.112 0.016 11.232 0.084 ;
     RECT  11.256 0.016 11.376 0.084 ;
     RECT  11.4 0.016 11.52 0.084 ;
     RECT  11.544 0.016 11.664 0.084 ;
     RECT  11.688 0.016 11.808 0.084 ;
     RECT  11.832 0.016 11.952 0.084 ;
     RECT  11.976 0.016 12.096 0.084 ;
     RECT  12.12 0.016 12.24 0.084 ;
     RECT  12.264 0.016 12.384 0.084 ;
     RECT  12.408 0.016 12.528 0.084 ;
     RECT  12.552 0.016 12.672 0.084 ;
     RECT  12.696 0.016 12.816 0.084 ;
     RECT  12.84 0.016 12.96 0.084 ;
     RECT  12.984 0.016 13.104 0.084 ;
     RECT  13.128 0.016 13.248 0.084 ;
     RECT  13.272 0.016 13.392 0.084 ;
     RECT  13.416 0.016 13.536 0.084 ;
     RECT  13.56 0.016 13.68 0.084 ;
     RECT  13.704 0.016 13.824 0.084 ;
     RECT  13.848 0.016 13.968 0.084 ;
     RECT  13.992 0.016 14.112 0.084 ;
     RECT  14.136 0.016 14.256 0.084 ;
     RECT  14.28 0.016 14.4 0.084 ;
     RECT  14.424 0.016 14.544 0.084 ;
     RECT  14.568 0.016 14.688 0.084 ;
     RECT  14.712 0.016 14.832 0.084 ;
     RECT  14.856 0.016 14.976 0.084 ;
     RECT  15 0.016 15.12 0.084 ;
     RECT  15.144 0.016 15.264 0.084 ;
     RECT  15.288 0.016 15.408 0.084 ;
     RECT  15.432 0.016 15.552 0.084 ;
     RECT  15.576 0.016 15.696 0.084 ;
     RECT  15.72 0.016 15.84 0.084 ;
     RECT  15.864 0.016 15.984 0.084 ;
     RECT  16.008 0.016 16.128 0.084 ;
     RECT  16.152 0.016 16.272 0.084 ;
     RECT  16.296 0.016 16.416 0.084 ;
     RECT  16.44 0.016 16.56 0.084 ;
     RECT  16.584 0.016 16.704 0.084 ;
     RECT  16.728 0.016 16.848 0.084 ;
     RECT  16.872 0.016 16.992 0.084 ;
     RECT  17.016 0.016 17.136 0.084 ;
     RECT  17.16 0.016 17.28 0.084 ;
     RECT  17.304 0.016 17.424 0.084 ;
     RECT  17.448 0.016 17.568 0.084 ;
     RECT  17.592 0.016 17.712 0.084 ;
     RECT  17.736 0.016 17.856 0.084 ;
     RECT  17.88 0.016 18 0.084 ;
     RECT  18.024 0.016 18.144 0.084 ;
     RECT  18.168 0.016 18.288 0.084 ;
     RECT  18.312 0.016 18.432 0.084 ;
     RECT  18.456 0.016 18.576 0.084 ;
     RECT  18.6 0.016 18.72 0.084 ;
     RECT  18.744 0.016 18.864 0.084 ;
     RECT  18.888 0.016 19.008 0.084 ;
     RECT  19.032 0.016 19.152 0.084 ;
     RECT  19.176 0.016 19.296 0.084 ;
     RECT  19.32 0.016 19.44 0.084 ;
     RECT  19.464 0.016 19.584 0.084 ;
     RECT  19.608 0.016 19.728 0.084 ;
     RECT  19.752 0.016 19.872 0.084 ;
     RECT  19.896 0.016 20.016 0.084 ;
     RECT  20.04 0.016 20.16 0.084 ;
     RECT  20.184 0.016 20.304 0.084 ;
     RECT  20.328 0.016 20.448 0.084 ;
     RECT  20.472 0.016 20.592 0.084 ;
     RECT  20.616 0.016 20.736 0.084 ;
     RECT  20.76 0.016 20.88 0.084 ;
     RECT  20.904 0.016 21.024 0.084 ;
     RECT  21.048 0.016 21.168 0.084 ;
     RECT  21.192 0.016 21.312 0.084 ;
     RECT  21.336 0.016 21.456 0.084 ;
     RECT  21.48 0.016 21.6 0.084 ;
     RECT  21.624 0.016 21.744 0.084 ;
     RECT  21.768 0.016 21.888 0.084 ;
     RECT  21.912 0.016 22.032 0.084 ;
     RECT  22.056 0.016 22.176 0.084 ;
     RECT  22.2 0.016 22.32 0.084 ;
     RECT  22.344 0.016 22.464 0.084 ;
     RECT  22.488 0.016 22.608 0.084 ;
     RECT  22.632 0.016 22.752 0.084 ;
     RECT  22.776 0.016 22.896 0.084 ;
     RECT  22.92 0.016 23.04 0.084 ;
     RECT  23.064 0.016 23.184 0.084 ;
     RECT  23.208 0.016 23.328 0.084 ;
     RECT  23.352 0.016 23.472 0.084 ;
     RECT  23.496 0.016 23.616 0.084 ;
     RECT  23.64 0.016 23.76 0.084 ;
     RECT  23.784 0.016 23.904 0.084 ;
     RECT  23.928 0.016 24.048 0.084 ;
     RECT  24.072 0.016 24.192 0.084 ;
     RECT  24.216 0.016 24.336 0.084 ;
     RECT  24.36 0.016 24.48 0.084 ;
     RECT  24.504 0.016 24.624 0.084 ;
     RECT  24.648 0.016 24.768 0.084 ;
     RECT  24.792 0.016 24.912 0.084 ;
     RECT  24.936 0.016 25.056 0.084 ;
     RECT  25.08 0.016 25.2 0.084 ;
     RECT  25.224 0.016 25.344 0.084 ;
     RECT  25.368 0.016 25.488 0.084 ;
     RECT  25.512 0.016 25.632 0.084 ;
     RECT  25.656 0.016 25.776 0.084 ;
     RECT  25.8 0.016 25.92 0.084 ;
     RECT  25.944 0.016 26.064 0.084 ;
     RECT  26.088 0.016 26.208 0.084 ;
     RECT  26.232 0.016 26.352 0.084 ;
     RECT  26.376 0.016 26.496 0.084 ;
     RECT  26.52 0.016 26.64 0.084 ;
     RECT  26.664 0.016 26.784 0.084 ;
     RECT  26.808 0.016 26.928 0.084 ;
     RECT  26.952 0.016 27.072 0.084 ;
     RECT  27.096 0.016 27.216 0.084 ;
     RECT  27.24 0.016 27.36 0.084 ;
     RECT  27.384 0.016 27.504 0.084 ;
     RECT  27.528 0.016 27.648 0.084 ;
     RECT  27.672 0.016 27.792 0.084 ;
     RECT  27.816 0.016 27.936 0.084 ;
     RECT  27.96 0.016 28.08 0.084 ;
     RECT  28.104 0.016 28.224 0.084 ;
     RECT  9.936 0.084 28.248 0.611 ;
     RECT  29.52 0.275 30.12 0.611 ;
     RECT  31.248 0.275 47.832 1.139 ;
     RECT  9.936 0.611 17.736 1.763 ;
     RECT  18.72 0.611 28.248 1.763 ;
     RECT  30.096 0.611 30.12 1.763 ;
     RECT  31.248 1.139 44.088 1.763 ;
     RECT  45.216 1.139 47.832 1.763 ;
     RECT  21.024 1.763 21.912 1.811 ;
     RECT  23.04 1.763 27.96 1.811 ;
     RECT  31.392 1.763 36.024 1.811 ;
     RECT  38.304 1.763 40.728 1.811 ;
     RECT  44.064 1.763 44.088 1.811 ;
     RECT  23.184 1.811 27.96 1.859 ;
     RECT  23.184 1.859 26.808 1.907 ;
     RECT  45.6 1.763 47.832 1.907 ;
     RECT  47.52 1.907 47.832 1.955 ;
     RECT  17.712 1.763 17.736 2.137 ;
     RECT  18.72 1.763 19.896 2.137 ;
     RECT  2.4 2.137 2.52 2.151 ;
     RECT  7.8 2.137 7.92 2.151 ;
     RECT  23.328 1.907 26.808 2.195 ;
     RECT  17.712 2.137 19.896 2.291 ;
     RECT  47.808 1.955 47.832 2.291 ;
     RECT  10.944 1.763 15 2.339 ;
     RECT  17.712 2.291 19.464 2.339 ;
     RECT  23.328 2.195 26.232 2.339 ;
     RECT  32.112 1.811 36.024 2.339 ;
     RECT  42.24 1.763 43.08 2.773 ;
     RECT  15.984 1.763 16.728 2.821 ;
     RECT  17.712 2.339 19.32 2.821 ;
     RECT  42.24 2.773 43.368 2.821 ;
     RECT  45.6 1.907 46.056 2.867 ;
     RECT  21.888 1.811 21.912 2.915 ;
     RECT  34.8 2.339 36.024 2.915 ;
     RECT  11.376 2.339 13.656 3.155 ;
     RECT  15.984 2.821 19.32 3.443 ;
     RECT  7.8 2.151 8.112 3.589 ;
     RECT  6.96 3.589 8.112 3.733 ;
     RECT  34.8 2.915 35.88 3.875 ;
     RECT  16.704 3.443 19.32 4.019 ;
     RECT  29.4 2.137 29.712 4.357 ;
     RECT  24 2.339 26.232 4.403 ;
     RECT  32.112 2.339 33.768 4.453 ;
     RECT  29.28 4.357 29.712 4.499 ;
     RECT  9.696 4.261 9.72 4.501 ;
     RECT  26.208 4.403 26.232 4.595 ;
     RECT  4.752 3.397 4.776 4.643 ;
     RECT  29.4 4.499 29.712 5.077 ;
     RECT  11.376 3.155 11.544 5.171 ;
     RECT  14.88 2.339 15 5.171 ;
     RECT  31.872 4.453 33.768 5.171 ;
     RECT  38.448 1.811 40.728 5.171 ;
     RECT  9.696 4.501 9.816 5.317 ;
     RECT  12.528 3.155 13.656 5.365 ;
     RECT  16.704 4.019 19.176 5.603 ;
     RECT  37.104 1.763 37.32 5.701 ;
     RECT  24 4.403 24.648 5.747 ;
     RECT  29.4 5.077 30.408 5.747 ;
     RECT  31.872 5.171 32.472 5.747 ;
     RECT  36.672 5.701 37.32 5.747 ;
     RECT  38.976 5.171 40.728 5.747 ;
     RECT  34.8 3.875 35.256 5.795 ;
     RECT  45.6 2.867 46.008 5.795 ;
     RECT  11.904 5.365 13.656 5.843 ;
     RECT  36.672 5.747 37.128 5.843 ;
     RECT  14.88 5.171 14.904 5.891 ;
     RECT  6.864 3.733 8.112 6.179 ;
     RECT  5.088 6.133 5.112 6.229 ;
     RECT  11.904 5.843 13.512 6.229 ;
     RECT  17.04 5.603 19.176 6.323 ;
     RECT  37.104 5.843 37.128 6.323 ;
     RECT  39.168 5.747 40.512 6.323 ;
     RECT  42.24 2.821 43.944 6.323 ;
     RECT  9.696 5.317 10.2 6.709 ;
     RECT  11.664 6.229 13.512 6.709 ;
     RECT  45.6 5.795 45.912 6.757 ;
     RECT  2.4 2.151 2.712 6.949 ;
     RECT  5.088 6.229 5.256 7.283 ;
     RECT  43.008 6.323 43.944 7.285 ;
     RECT  45.6 6.757 46.152 7.285 ;
     RECT  43.008 7.285 46.152 7.381 ;
     RECT  43.008 7.381 46.248 7.717 ;
     RECT  2.4 6.949 3.48 7.859 ;
     RECT  9.696 6.709 13.512 8.003 ;
     RECT  17.04 6.323 18.912 8.003 ;
     RECT  24 5.747 24.408 8.003 ;
     RECT  9.696 8.003 11.688 8.483 ;
     RECT  17.28 8.003 18.912 8.579 ;
     RECT  7.8 6.179 8.112 9.589 ;
     RECT  7.8 9.589 8.616 9.923 ;
     RECT  5.088 7.283 5.112 10.069 ;
     RECT  7.8 9.923 8.112 10.165 ;
     RECT  5.088 10.069 5.16 10.259 ;
     RECT  9.696 8.483 11.064 10.451 ;
     RECT  6.864 10.165 8.112 10.883 ;
     RECT  9.696 10.451 10.968 10.979 ;
     RECT  5.088 10.259 5.112 11.267 ;
     RECT  7.296 10.883 8.112 11.941 ;
     RECT  42.768 7.717 46.248 12.179 ;
     RECT  31.872 5.747 31.896 12.467 ;
     RECT  6.864 11.941 8.112 12.517 ;
     RECT  17.28 8.579 17.304 12.563 ;
     RECT  6.864 12.517 8.232 12.611 ;
     RECT  7.296 12.611 8.232 13.091 ;
     RECT  42.768 12.179 46.152 15.107 ;
     RECT  7.296 13.091 8.112 16.499 ;
     RECT  7.344 16.499 8.112 17.701 ;
     RECT  43.2 15.107 46.152 18.133 ;
     RECT  7.344 17.701 8.232 18.467 ;
     RECT  43.2 18.133 46.248 19.283 ;
     RECT  7.8 18.467 8.232 19.427 ;
     RECT  5.04 18.421 5.064 21.155 ;
     RECT  0.192 10.069 0.216 25.811 ;
     RECT  26.208 12.805 26.232 25.957 ;
     RECT  26.208 25.957 26.472 26.003 ;
     RECT  43.2 19.283 46.152 29.123 ;
     RECT  44.496 29.123 46.152 30.275 ;
     RECT  43.2 29.123 43.32 33.011 ;
     RECT  44.544 30.275 46.152 33.251 ;
     RECT  43.296 33.011 43.32 33.589 ;
     RECT  43.296 33.589 43.56 33.779 ;
     RECT  43.536 33.779 43.56 34.355 ;
     RECT  9.696 10.979 10.824 34.787 ;
     RECT  44.976 33.251 46.152 35.123 ;
     RECT  9.936 34.787 10.824 35.363 ;
     RECT  26.448 26.003 26.472 35.461 ;
     RECT  26.448 35.461 26.76 35.507 ;
     RECT  38.16 35.605 38.184 36.947 ;
     RECT  26.736 35.507 26.76 39.923 ;
     RECT  43.632 36.949 43.656 41.075 ;
     RECT  50.16 43.669 50.184 43.859 ;
     RECT  34.8 5.795 35.112 46.117 ;
     RECT  43.152 45.541 43.176 46.259 ;
     RECT  29.4 5.747 29.712 46.405 ;
     RECT  34.368 46.117 35.112 46.451 ;
     RECT  34.704 46.451 35.112 46.547 ;
     RECT  13.2 8.003 13.512 46.645 ;
     RECT  26.736 40.981 26.76 46.787 ;
     RECT  21.12 46.837 21.144 47.029 ;
     RECT  44.976 35.123 46.056 47.029 ;
     RECT  21.12 47.029 21.432 47.075 ;
     RECT  34.8 46.547 35.112 48.181 ;
     RECT  44.256 47.029 46.056 48.469 ;
     RECT  7.8 19.427 8.112 48.997 ;
     RECT  13.2 46.645 13.944 48.997 ;
     RECT  18.6 8.579 18.912 48.997 ;
     RECT  21.408 47.075 21.432 48.997 ;
     RECT  24 8.003 24.312 48.997 ;
     RECT  29.4 46.405 30.36 48.997 ;
     RECT  40.2 6.323 40.512 48.997 ;
     RECT  44.256 48.469 46.728 48.997 ;
     RECT  26.64 48.997 27.384 49.045 ;
     RECT  28.512 48.997 30.84 49.045 ;
     RECT  31.968 48.997 32.424 49.045 ;
     RECT  34.8 48.181 36.024 49.045 ;
     RECT  37.152 48.997 46.728 49.045 ;
     RECT  23.904 48.997 25.656 49.333 ;
     RECT  26.64 49.045 32.568 49.333 ;
     RECT  34.704 49.045 46.728 49.379 ;
     RECT  33.696 46.645 33.72 49.381 ;
     RECT  34.704 49.379 46.392 49.381 ;
     RECT  23.472 49.333 32.568 49.477 ;
     RECT  33.696 49.381 46.392 49.477 ;
     RECT  2.4 7.859 2.712 49.689 ;
     RECT  2.4 49.689 2.52 49.703 ;
     RECT  7.8 48.997 22.2 49.703 ;
     RECT  8.496 49.703 22.2 51.756 ;
     RECT  8.52 51.756 8.64 51.792 ;
     RECT  8.664 51.756 8.784 51.792 ;
     RECT  8.808 51.756 8.928 51.792 ;
     RECT  8.952 51.756 9.072 51.792 ;
     RECT  9.096 51.756 9.216 51.792 ;
     RECT  9.24 51.756 9.36 51.792 ;
     RECT  9.384 51.756 9.504 51.792 ;
     RECT  9.528 51.756 9.648 51.792 ;
     RECT  9.672 51.756 9.792 51.792 ;
     RECT  9.816 51.756 9.936 51.792 ;
     RECT  9.96 51.756 10.08 51.792 ;
     RECT  10.104 51.756 10.224 51.792 ;
     RECT  10.248 51.756 10.368 51.792 ;
     RECT  10.392 51.756 10.512 51.792 ;
     RECT  10.536 51.756 10.656 51.792 ;
     RECT  10.68 51.756 10.8 51.792 ;
     RECT  10.824 51.756 10.944 51.792 ;
     RECT  10.968 51.756 11.088 51.792 ;
     RECT  11.112 51.756 11.232 51.792 ;
     RECT  11.256 51.756 11.376 51.792 ;
     RECT  11.4 51.756 11.52 51.792 ;
     RECT  11.544 51.756 11.664 51.792 ;
     RECT  11.688 51.756 11.808 51.792 ;
     RECT  11.832 51.756 11.952 51.792 ;
     RECT  11.976 51.756 12.096 51.792 ;
     RECT  12.12 51.756 12.24 51.792 ;
     RECT  12.264 51.756 12.384 51.792 ;
     RECT  12.408 51.756 12.528 51.792 ;
     RECT  12.552 51.756 12.672 51.792 ;
     RECT  12.696 51.756 12.816 51.792 ;
     RECT  12.84 51.756 12.96 51.792 ;
     RECT  12.984 51.756 13.104 51.792 ;
     RECT  13.128 51.756 13.248 51.792 ;
     RECT  13.272 51.756 13.392 51.792 ;
     RECT  13.416 51.756 13.536 51.792 ;
     RECT  13.56 51.756 13.68 51.792 ;
     RECT  13.704 51.756 13.824 51.792 ;
     RECT  13.848 51.756 13.968 51.792 ;
     RECT  13.992 51.756 14.112 51.792 ;
     RECT  14.136 51.756 14.256 51.792 ;
     RECT  14.28 51.756 14.4 51.792 ;
     RECT  14.424 51.756 14.544 51.792 ;
     RECT  14.568 51.756 14.688 51.792 ;
     RECT  14.712 51.756 14.832 51.792 ;
     RECT  14.856 51.756 14.976 51.792 ;
     RECT  15 51.756 15.12 51.792 ;
     RECT  15.144 51.756 15.264 51.792 ;
     RECT  15.288 51.756 15.408 51.792 ;
     RECT  15.432 51.756 15.552 51.792 ;
     RECT  15.576 51.756 15.696 51.792 ;
     RECT  15.72 51.756 15.84 51.792 ;
     RECT  15.864 51.756 15.984 51.792 ;
     RECT  16.008 51.756 16.128 51.792 ;
     RECT  16.152 51.756 16.272 51.792 ;
     RECT  16.296 51.756 16.416 51.792 ;
     RECT  16.44 51.756 16.56 51.792 ;
     RECT  16.584 51.756 16.704 51.792 ;
     RECT  16.728 51.756 16.848 51.792 ;
     RECT  16.872 51.756 16.992 51.792 ;
     RECT  17.016 51.756 17.136 51.792 ;
     RECT  17.16 51.756 17.28 51.792 ;
     RECT  17.304 51.756 17.424 51.792 ;
     RECT  17.448 51.756 17.568 51.792 ;
     RECT  17.592 51.756 17.712 51.792 ;
     RECT  17.736 51.756 17.856 51.792 ;
     RECT  17.88 51.756 18 51.792 ;
     RECT  18.024 51.756 18.144 51.792 ;
     RECT  18.168 51.756 18.288 51.792 ;
     RECT  18.312 51.756 18.432 51.792 ;
     RECT  18.456 51.756 18.576 51.792 ;
     RECT  18.6 51.756 18.72 51.792 ;
     RECT  18.744 51.756 18.864 51.792 ;
     RECT  18.888 51.756 19.008 51.792 ;
     RECT  19.032 51.756 19.152 51.792 ;
     RECT  19.176 51.756 19.296 51.792 ;
     RECT  19.32 51.756 19.44 51.792 ;
     RECT  19.464 51.756 19.584 51.792 ;
     RECT  19.608 51.756 19.728 51.792 ;
     RECT  19.752 51.756 19.872 51.792 ;
     RECT  19.896 51.756 20.016 51.792 ;
     RECT  20.04 51.756 20.16 51.792 ;
     RECT  20.184 51.756 20.304 51.792 ;
     RECT  20.328 51.756 20.448 51.792 ;
     RECT  20.472 51.756 20.592 51.792 ;
     RECT  20.616 51.756 20.736 51.792 ;
     RECT  20.76 51.756 20.88 51.792 ;
     RECT  20.904 51.756 21.024 51.792 ;
     RECT  21.048 51.756 21.168 51.792 ;
     RECT  21.192 51.756 21.312 51.792 ;
     RECT  21.336 51.756 21.456 51.792 ;
     RECT  21.48 51.756 21.6 51.792 ;
     RECT  21.624 51.756 21.744 51.792 ;
     RECT  21.768 51.756 21.888 51.792 ;
     RECT  21.912 51.756 22.032 51.792 ;
     RECT  22.056 51.756 22.176 51.792 ;
     RECT  23.472 49.477 46.392 51.756 ;
     RECT  23.496 51.756 23.616 51.792 ;
     RECT  23.64 51.756 23.76 51.792 ;
     RECT  23.784 51.756 23.904 51.792 ;
     RECT  23.928 51.756 24.048 51.792 ;
     RECT  24.072 51.756 24.192 51.792 ;
     RECT  24.216 51.756 24.336 51.792 ;
     RECT  24.36 51.756 24.48 51.792 ;
     RECT  24.504 51.756 24.624 51.792 ;
     RECT  24.648 51.756 24.768 51.792 ;
     RECT  24.792 51.756 24.912 51.792 ;
     RECT  24.936 51.756 25.056 51.792 ;
     RECT  25.08 51.756 25.2 51.792 ;
     RECT  25.224 51.756 25.344 51.792 ;
     RECT  25.368 51.756 25.488 51.792 ;
     RECT  25.512 51.756 25.632 51.792 ;
     RECT  25.656 51.756 25.776 51.792 ;
     RECT  25.8 51.756 25.92 51.792 ;
     RECT  25.944 51.756 26.064 51.792 ;
     RECT  26.088 51.756 26.208 51.792 ;
     RECT  26.232 51.756 26.352 51.792 ;
     RECT  26.376 51.756 26.496 51.792 ;
     RECT  26.52 51.756 26.64 51.792 ;
     RECT  26.664 51.756 26.784 51.792 ;
     RECT  26.808 51.756 26.928 51.792 ;
     RECT  26.952 51.756 27.072 51.792 ;
     RECT  27.096 51.756 27.216 51.792 ;
     RECT  27.24 51.756 27.36 51.792 ;
     RECT  27.384 51.756 27.504 51.792 ;
     RECT  27.528 51.756 27.648 51.792 ;
     RECT  27.672 51.756 27.792 51.792 ;
     RECT  27.816 51.756 27.936 51.792 ;
     RECT  27.96 51.756 28.08 51.792 ;
     RECT  28.104 51.756 28.224 51.792 ;
     RECT  28.248 51.756 28.368 51.792 ;
     RECT  28.392 51.756 28.512 51.792 ;
     RECT  28.536 51.756 28.656 51.792 ;
     RECT  28.68 51.756 28.8 51.792 ;
     RECT  28.824 51.756 28.944 51.792 ;
     RECT  28.968 51.756 29.088 51.792 ;
     RECT  29.112 51.756 29.232 51.792 ;
     RECT  29.256 51.756 29.376 51.792 ;
     RECT  29.4 51.756 29.52 51.792 ;
     RECT  29.544 51.756 29.664 51.792 ;
     RECT  29.688 51.756 29.808 51.792 ;
     RECT  29.832 51.756 29.952 51.792 ;
     RECT  29.976 51.756 30.096 51.792 ;
     RECT  30.12 51.756 30.24 51.792 ;
     RECT  30.264 51.756 30.384 51.792 ;
     RECT  30.408 51.756 30.528 51.792 ;
     RECT  30.552 51.756 30.672 51.792 ;
     RECT  30.696 51.756 30.816 51.792 ;
     RECT  30.84 51.756 30.96 51.792 ;
     RECT  30.984 51.756 31.104 51.792 ;
     RECT  31.128 51.756 31.248 51.792 ;
     RECT  31.272 51.756 31.392 51.792 ;
     RECT  31.416 51.756 31.536 51.792 ;
     RECT  31.56 51.756 31.68 51.792 ;
     RECT  31.704 51.756 31.824 51.792 ;
     RECT  31.848 51.756 31.968 51.792 ;
     RECT  31.992 51.756 32.112 51.792 ;
     RECT  32.136 51.756 32.256 51.792 ;
     RECT  32.28 51.756 32.4 51.792 ;
     RECT  32.424 51.756 32.544 51.792 ;
     RECT  32.568 51.756 32.688 51.792 ;
     RECT  32.712 51.756 32.832 51.792 ;
     RECT  32.856 51.756 32.976 51.792 ;
     RECT  33 51.756 33.12 51.792 ;
     RECT  33.144 51.756 33.264 51.792 ;
     RECT  33.288 51.756 33.408 51.792 ;
     RECT  33.432 51.756 33.552 51.792 ;
     RECT  33.576 51.756 33.696 51.792 ;
     RECT  33.72 51.756 33.84 51.792 ;
     RECT  33.864 51.756 33.984 51.792 ;
     RECT  34.008 51.756 34.128 51.792 ;
     RECT  34.152 51.756 34.272 51.792 ;
     RECT  34.296 51.756 34.416 51.792 ;
     RECT  34.44 51.756 34.56 51.792 ;
     RECT  34.584 51.756 34.704 51.792 ;
     RECT  34.728 51.756 34.848 51.792 ;
     RECT  34.872 51.756 34.992 51.792 ;
     RECT  35.016 51.756 35.136 51.792 ;
     RECT  35.16 51.756 35.28 51.792 ;
     RECT  35.304 51.756 35.424 51.792 ;
     RECT  35.448 51.756 35.568 51.792 ;
     RECT  35.592 51.756 35.712 51.792 ;
     RECT  35.736 51.756 35.856 51.792 ;
     RECT  35.88 51.756 36 51.792 ;
     RECT  36.024 51.756 36.144 51.792 ;
     RECT  36.168 51.756 36.288 51.792 ;
     RECT  36.312 51.756 36.432 51.792 ;
     RECT  36.456 51.756 36.576 51.792 ;
     RECT  36.6 51.756 36.72 51.792 ;
     RECT  36.744 51.756 36.864 51.792 ;
     RECT  36.888 51.756 37.008 51.792 ;
     RECT  37.032 51.756 37.152 51.792 ;
     RECT  37.176 51.756 37.296 51.792 ;
     RECT  37.32 51.756 37.44 51.792 ;
     RECT  37.464 51.756 37.584 51.792 ;
     RECT  37.608 51.756 37.728 51.792 ;
     RECT  37.752 51.756 37.872 51.792 ;
     RECT  37.896 51.756 38.016 51.792 ;
     RECT  38.04 51.756 38.16 51.792 ;
     RECT  38.184 51.756 38.304 51.792 ;
     RECT  38.328 51.756 38.448 51.792 ;
     RECT  38.472 51.756 38.592 51.792 ;
     RECT  38.616 51.756 38.736 51.792 ;
     RECT  38.76 51.756 38.88 51.792 ;
     RECT  38.904 51.756 39.024 51.792 ;
     RECT  39.048 51.756 39.168 51.792 ;
     RECT  39.192 51.756 39.312 51.792 ;
     RECT  39.336 51.756 39.456 51.792 ;
     RECT  39.48 51.756 39.6 51.792 ;
     RECT  39.624 51.756 39.744 51.792 ;
     RECT  39.768 51.756 39.888 51.792 ;
     RECT  39.912 51.756 40.032 51.792 ;
     RECT  40.056 51.756 40.176 51.792 ;
     RECT  40.2 51.756 40.32 51.792 ;
     RECT  40.344 51.756 40.464 51.792 ;
     RECT  40.488 51.756 40.608 51.792 ;
     RECT  40.632 51.756 40.752 51.792 ;
     RECT  40.776 51.756 40.896 51.792 ;
     RECT  40.92 51.756 41.04 51.792 ;
     RECT  41.064 51.756 41.184 51.792 ;
     RECT  41.208 51.756 41.328 51.792 ;
     RECT  41.352 51.756 41.472 51.792 ;
     RECT  41.496 51.756 41.616 51.792 ;
     RECT  41.64 51.756 41.76 51.792 ;
     RECT  41.784 51.756 41.904 51.792 ;
     RECT  41.928 51.756 42.048 51.792 ;
     RECT  42.072 51.756 42.192 51.792 ;
     RECT  42.216 51.756 42.336 51.792 ;
     RECT  42.36 51.756 42.48 51.792 ;
     RECT  42.504 51.756 42.624 51.792 ;
     RECT  42.648 51.756 42.768 51.792 ;
     RECT  42.792 51.756 42.912 51.792 ;
     RECT  42.936 51.756 43.056 51.792 ;
     RECT  43.08 51.756 43.2 51.792 ;
     RECT  43.224 51.756 43.344 51.792 ;
     RECT  43.368 51.756 43.488 51.792 ;
     RECT  43.512 51.756 43.632 51.792 ;
     RECT  43.656 51.756 43.776 51.792 ;
     RECT  43.8 51.756 43.92 51.792 ;
     RECT  43.944 51.756 44.064 51.792 ;
     RECT  44.088 51.756 44.208 51.792 ;
     RECT  44.232 51.756 44.352 51.792 ;
     RECT  44.376 51.756 44.496 51.792 ;
     RECT  44.52 51.756 44.64 51.792 ;
     RECT  44.664 51.756 44.784 51.792 ;
     RECT  44.808 51.756 44.928 51.792 ;
     RECT  44.952 51.756 45.072 51.792 ;
     RECT  45.096 51.756 45.216 51.792 ;
     RECT  45.24 51.756 45.36 51.792 ;
     RECT  45.384 51.756 45.504 51.792 ;
     RECT  45.528 51.756 45.648 51.792 ;
     RECT  45.672 51.756 45.792 51.792 ;
     RECT  45.816 51.756 45.936 51.792 ;
     RECT  45.96 51.756 46.08 51.792 ;
     RECT  46.104 51.756 46.224 51.792 ;
     RECT  46.248 51.756 46.368 51.792 ;
     RECT  28.344 0.016 29.424 0.18 ;
     RECT  28.248 0.18 29.52 0.611 ;
     RECT  30.12 0.275 31.248 1.763 ;
     RECT  17.736 0.611 18.72 2.137 ;
     RECT  28.248 0.611 30.096 1.763 ;
     RECT  44.088 1.139 45.216 1.763 ;
     RECT  15 1.763 15.984 3.443 ;
     RECT  16.728 1.763 17.712 2.821 ;
     RECT  19.896 1.763 21.024 1.811 ;
     RECT  21.912 1.763 23.04 1.811 ;
     RECT  27.96 1.763 29.712 1.859 ;
     RECT  36.024 1.763 37.104 2.915 ;
     RECT  37.32 1.763 38.304 1.811 ;
     RECT  40.728 1.763 42.24 5.747 ;
     RECT  43.08 1.763 44.064 1.811 ;
     RECT  44.088 1.763 45.6 1.811 ;
     RECT  21.912 1.811 23.184 1.907 ;
     RECT  37.32 1.811 38.448 5.171 ;
     RECT  43.08 1.811 43.944 2.773 ;
     RECT  29.4 1.859 29.712 2.137 ;
     RECT  21.912 1.907 23.328 2.339 ;
     RECT  46.056 1.907 47.52 1.955 ;
     RECT  13.656 2.339 14.88 5.843 ;
     RECT  33.768 2.339 34.8 5.171 ;
     RECT  43.368 2.773 43.944 2.821 ;
     RECT  35.88 2.915 37.104 3.875 ;
     RECT  11.544 3.155 12.528 5.171 ;
     RECT  30.408 5.077 31.872 5.747 ;
     RECT  11.376 5.171 12.528 5.317 ;
     RECT  10.2 5.317 12.528 5.365 ;
     RECT  10.2 5.365 11.904 6.229 ;
     RECT  35.256 5.701 36.672 5.795 ;
     RECT  45.912 5.795 46.008 6.757 ;
     RECT  13.512 5.843 14.88 5.891 ;
     RECT  10.2 6.229 11.664 6.709 ;
     RECT  42.768 6.323 43.008 7.717 ;
     RECT  11.688 8.003 13.2 8.483 ;
     RECT  17.304 8.579 18.6 12.563 ;
     RECT  8.616 9.589 9.696 9.923 ;
     RECT  6.864 10.883 7.296 11.941 ;
     RECT  8.232 12.517 9.696 13.091 ;
     RECT  8.232 17.701 9.696 19.427 ;
     RECT  43.32 29.123 44.496 30.275 ;
     RECT  43.32 30.275 44.544 33.251 ;
     RECT  43.32 33.251 44.976 33.589 ;
     RECT  43.56 33.589 44.976 34.355 ;
     RECT  43.656 36.949 44.976 41.075 ;
     RECT  26.736 39.923 26.76 40.981 ;
     RECT  34.368 46.451 34.704 46.547 ;
     RECT  34.368 46.547 34.8 46.645 ;
     RECT  33.72 46.645 34.8 49.045 ;
     RECT  25.656 48.997 26.64 49.333 ;
     RECT  27.384 48.997 28.512 49.045 ;
     RECT  30.84 48.997 31.968 49.045 ;
     RECT  32.424 48.997 33.696 49.045 ;
     RECT  36.024 48.997 37.152 49.045 ;
     RECT  32.568 49.045 33.696 49.477 ;
     RECT  33.72 49.045 34.704 49.381 ;
     RECT  22.2 49.333 23.472 51.66 ;
     RECT  22.296 51.66 23.376 51.792 ;
  END
END ot_static_run_target
END LIBRARY
